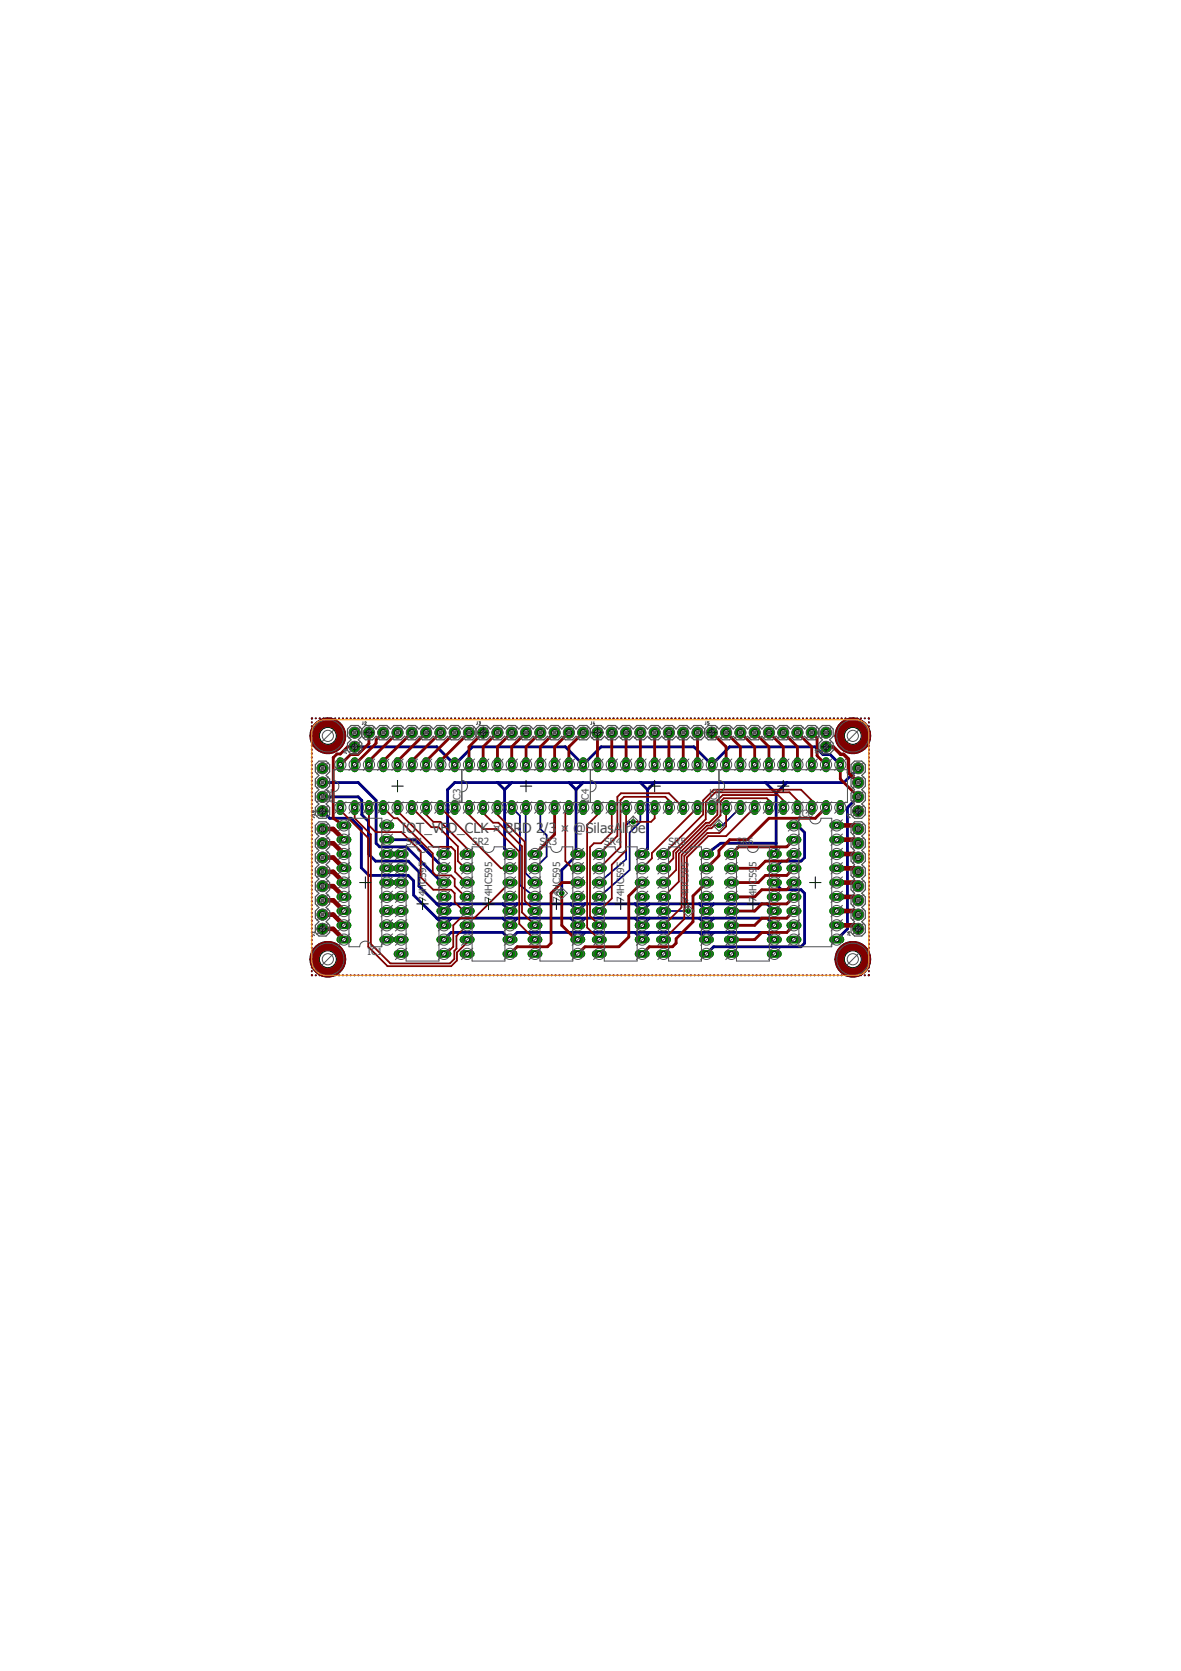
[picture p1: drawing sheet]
<svg xmlns="http://www.w3.org/2000/svg" width="210mm" height="297mm" viewBox="0 0 210 297" stroke-linecap="round" stroke-linejoin="round" font-family="sans-serif">
<defs><g id="words">
<g font-size="2.5" fill="#505050">
<text x="71.3" y="148">IOT_VF</text>
<text x="79.6" y="148">D_CLK ¤</text>
<text x="89.8" y="148">BR</text>
<text x="92.8" y="148">D 2/3</text>
<text x="99.7" y="148">¤</text>
<text x="101.8" y="148">@Silas</text>
<text x="109.1" y="148">A</text>
<text x="110.6" y="148">lroe</text>
</g>
<g font-size="1.8" fill="#505050">
<text x="59" y="142.8" transform="rotate(-90 59 142.8)">IC2</text>
<text x="81.8" y="142.8" transform="rotate(-90 81.8 142.8)">I</text>
<text x="81.8" y="142.1" transform="rotate(-90 81.8 142.1)">C3</text>
<text x="104.7" y="142.8" transform="rotate(-90 104.7 142.8)">I</text>
<text x="104.7" y="142.1" transform="rotate(-90 104.7 142.1)">C4</text>
<text x="127.5" y="142.8" transform="rotate(-90 127.5 142.8)">I</text>
<text x="127.5" y="142.1" transform="rotate(-90 127.5 142.1)">C5</text>
<text x="141.9" y="145.2">IC6</text>
<text x="72.2" y="150.2">SR1</text>
<text x="83.9" y="150.2">SR2</text>
<text x="96" y="150.2">SR3</text>
<text x="107.4" y="150.2">SR4</text>
<text x="118.8" y="150.2">SR5</text>
<text x="130.9" y="150.2">SR6</text>
<text x="134.4" y="154.2" transform="rotate(-90 134.4 154.2)">5</text>
<text x="75.7" y="160.3" transform="rotate(-90 75.7 160.3)">74HC595</text>
<text x="87.5" y="160.3" transform="rotate(-90 87.5 160.3)">74HC595</text>
<text x="99.5" y="160.3" transform="rotate(-90 99.5 160.3)">74HC595</text>
<text x="111" y="160.3" transform="rotate(-90 111 160.3)">74HC595</text>
<text x="122.4" y="160.3" transform="rotate(-90 122.4 160.3)">74HC595</text>
<text x="134.4" y="160.3" transform="rotate(-90 134.4 160.3)">74HC59</text>
<text x="65.3" y="169.8">IC1</text>
</g>
</g></defs>
<g fill="#000080" stroke="#000080" stroke-width=".18">
<path d="M56.2 168.2a3.2 3.2 0 0 1 4.9 .9 3.2 3.2 0 0 1-2.1 4.5 3.2 3.2 0 0 1-3.9-3.1h2.5a.63 .63 0 0 1 .9-.6 .63 .63 0 0 1 .2 1.1 .63 .63 0 0 1-1-.4l-.1-.1h-2.5a3.1 3.1 0 0 1 1.1-2.3z" fill-rule="evenodd"/>
<path d="M56.2 128.4a3.2 3.2 0 0 1 4.9 .9 3.2 3.2 0 0 1-2.1 4.6 3.2 3.2 0 0 1-3.9-3.1h2.5a.63 .63 0 0 1 .9-.6 .63 .63 0 0 1 .2 1 .63 .63 0 0 1-1-.3l-.1-.1h-2.5a3.2 3.2 0 0 1 1.1-2.4z" fill-rule="evenodd"/>
<path d="M149.5 128.4a3.2 3.2 0 0 1 4.9 .9 3.2 3.2 0 0 1-2.1 4.6 3.2 3.2 0 0 1-3.9-3.1h2.5a.64 .64 0 0 1 .9-.6 .64 .64 0 0 1 .2 1 .64 .64 0 0 1-1-.3l-.1-.1h-2.5a3.2 3.2 0 0 1 1.1-2.4z" fill-rule="evenodd"/>
<path d="M149.5 168.2a3.2 3.2 0 0 1 4.9 .9 3.2 3.2 0 0 1-2.1 4.5 3.2 3.2 0 0 1-3.9-3.1h2.5a.64 .64 0 0 1 .9-.6 .64 .64 0 0 1 .2 1.1 .64 .64 0 0 1-1-.4l-.1-.1h-2.5a3.1 3.1 0 0 1 1.1-2.3z" fill-rule="evenodd"/>
</g>
<g fill="none" stroke="#000080" stroke-width=".32">
<path d="M55.4 128.4v.1M55.4 129.1v.1M55.4 129.8h.1M55.4 130.5h.1M55.4 131.1v.1M55.4 131.8v.1M55.4 132.5v.1M55.4 133.2v.1M55.4 133.9v.1M55.4 134.6v.1M55.4 135.3v.1M55.4 136v.1"/>
<path d="M55.4 136.7v.1M55.4 137.4v.1M55.4 138v.1M55.4 138.7v.1M55.4 139.4v.1M55.5 127.7l-.1 .1M56.1 127.7h.1M56.8 127.7h.1M57.3 136v.6M57.5 127.7h.1M58.2 127.7h.1M58.8 127.7h.1"/>
<path d="M59.5 127.7h.1M60.2 127.7h.1M60.9 127.7h.1M61.6 127.7h.1M62.3 127.7h.1M63 127.7h.1M63 130.2l-.1 .3M63.7 127.7h.1M64.3 127.7h.1M65 127.7h.1M65.7 127.7h.1M66.4 127.7h.1"/>
<path d="M67.1 127.7h.1M67.8 127.7h.1M68.5 127.7h.1M69.2 127.7h.1M69.8 127.7h.1M70.5 127.7h.1M71.2 127.7h.1M71.9 127.7h.1M72.6 127.7h.1M73.3 127.7h.1M74 127.7h.1M74.7 127.7h.1"/>
<path d="M75.3 127.7h.1M76 127.7h.1M76.7 127.7h.1M77.4 127.7h.1M78.1 127.7h.1M78.8 127.7h.1M79.5 127.7h.1M80.2 127.7h.1M80.8 127.7h.1M81.5 127.7h.1M82.2 127.7h.1M82.9 127.7h.1"/>
<path d="M83.6 127.7h.1M84.3 127.7h.1M85 127.7h.1M85.6 127.7h.1M86.3 127.7h.1M87 127.7h.1M87.7 127.7h.1M88.4 127.7h.1M89.1 127.7h.1M89.8 127.7h.1M90.5 127.7h.1M91.1 127.7h.1"/>
<path d="M91.8 127.7h.1M92.5 127.7h.1M93.2 127.7h.1M93.9 127.7h.1M94.6 127.7h.1M95.3 127.7h.1M95.9 127.7h.1M96.6 127.7h.1M97.3 127.7h.1M98 127.7h.1M98.7 127.7h.1M99.4 127.7h.1"/>
<path d="M100.1 127.7h.1M100.8 127.7h.1M101.5 127.7h.1M102.1 127.7h.1M102.8 127.7h.1M103.5 127.7h.1M104.2 127.7h.1M104.9 127.7h.1M105.6 127.7h.1M106.3 127.7h.1M107 127.7h.1M107.6 127.7h.1"/>
<path d="M108.3 127.7h.1M109 127.7h.1M109.7 127.7h.1M110.4 127.7h.1M111.1 127.7h.1M111.8 127.7h.1M112.4 127.7h.1M113.1 127.7h.1M113.8 127.7h.1M114.5 127.7h.1M115.2 127.7h.1M115.9 127.7h.1"/>
<path d="M116.6 127.7h.1M117.3 127.7h.1M117.9 127.7h.1M118.6 127.7h.1M119.3 127.7h.1M120 127.7h.1M120.7 127.7h.1M121.4 127.7h.1M122.1 127.7h.1M122.7 127.7h.1M123.4 127.7h.1M124.1 127.7h.1"/>
<path d="M124.8 127.7h.1M125.5 127.7h.1M126.2 127.7h.1M126.9 127.7h.1M127.6 127.7h.1M128.2 127.7h.1M128.9 127.7h.1M129.6 127.7h.1M130.3 127.7h.1M131 127.7h.1M131.7 127.7h.1M132.4 127.7h.1"/>
<path d="M133.1 127.7h.1M133.8 127.7h.1M134.4 127.7h.1M135.1 127.7h.1M135.8 127.7h.1M136.5 127.7h.1M137.2 127.7h.1M137.9 127.7h.1M138.6 127.7h.1M139.2 127.7h.1M139.9 127.7h.1M140.6 127.7h.1"/>
<path d="M141.3 127.7h.1M142 127.7h.1M142.7 127.7h.1M143.4 127.7h.1M144.1 127.7h.1M144.7 127.7h.1M145.4 127.7h.1M146.1 127.7h.1M146.8 127.7h.1M147.5 127.7h.1M148.2 127.7h.1M148.9 127.7h.1"/>
<path d="M149.5 127.7h.1M150.2 127.7h.1M150.9 127.7h.1M151.6 127.7h.1M152.3 127.7h.1M153 127.7h.1M153.7 127.7h.1M154.4 127.7v.1M154.4 128.4v.1M154.4 129.1v.1M154.4 129.8h.1M154.4 130.5h.1"/>
<path d="M154.4 131.1v.1M154.4 131.8v.1M154.4 132.5v.1M154.4 133.2v.1M154.4 133.9v.1M154.4 134.6v.1M154.4 135.3v.1M154.4 136v.1M154.4 136.7v.1M154.4 137.4v.1M154.4 138v.1M154.4 138.7v.1"/>
<path d="M154.4 139.4v.1M55.4 140.1v.1M55.4 140.8v.1M55.4 141.5v.1M55.4 142.2v.1M55.4 142.9v.1M55.4 143.6v.1M55.4 144.3v.1M55.4 145v.1M55.4 145.6v.1M55.4 146.3v.1M55.4 147v.1"/>
<path d="M55.4 147.7v.1M55.4 148.4v.1M55.4 149.1v.1M55.4 149.8v.1M55.4 150.5v.1M55.4 151.2v.1M55.4 151.9v.1M55.4 152.6v.1M55.4 153.2v.1M55.4 153.9v.1M55.4 154.6v.1M55.4 155.3v.1"/>
<path d="M55.4 156v.1M55.4 156.7v.1M55.4 157.4v.1M55.4 158.1v.1M55.4 158.8v.1M55.4 159.5v.1M63 146.1l1 .9M91 143.6l1.4 1.4v12.4l2.7 2M93.5 143.6l-.1 11.6 1.7 1.7M96 143.6v3.8l1.2 1.1v3.8l-2.1 2M112.5 146.1h-.6l-.6 .6v6.1l-4.8 4.1M113.8 143.6v2.5l-1.9 1.9v6.7l-5.4 4.7"/>
<path d="M131.6 143.6l-3.2 3.1h-.6M154.4 140.1v.1M154.4 140.8v.1M154.4 141.5v.1M154.4 142.2v.1M154.4 142.9v.1M154.4 143.6v.1M154.4 144.3v.1M154.4 145v.1M154.4 145.6v.1M154.4 146.3v.1M154.4 147v.1"/>
<path d="M154.4 147.7v.1M154.4 148.4v.1M154.4 149.1v.1M154.4 149.8v.1M154.4 150.5v.1M154.4 151.2v.1M154.4 151.9v.1M154.4 152.6v.1M154.4 153.2v.1M154.4 153.9v.1M154.4 154.6v.1M154.4 155.3v.1"/>
<path d="M154.4 156v.1M154.4 156.7v.1M154.4 157.4v.1M154.4 158.1v.1M154.4 158.8v.1M154.4 159.5v.1M55.4 160.2v.1M55.4 160.9h.1M55.4 161.5v.1M55.4 162.2v.1M55.4 162.9v.1M55.4 163.6v.1"/>
<path d="M55.4 164.3v.1M55.4 165v.1M55.4 165.7v.1M55.4 166.4v.1M55.4 167.1v.1M55.4 167.8v.1M55.4 168.5h.1M55.4 169.1v.1M55.4 169.8v.1M55.4 170.5v.1M55.4 171.2v.1M55.4 171.9v.1"/>
<path d="M55.4 172.6v.1M55.4 173.3l.1 .1M56.1 173.4h.1M56.8 173.4h.1M57.5 173.4h.1M58.2 173.4h.1M58.8 173.4h.1M59.5 173.4h.1M60.2 173.4h.1M60.9 173.4h.1M61.6 173.4h.1M62.3 173.4h.1"/>
<path d="M63 173.4h.1M63.7 173.4h.1M64.3 173.4h.1M65 173.4h.1M65.7 173.4h.1M66.4 173.4h.1M67.1 173.4h.1M67.8 173.4h.1M68.5 173.4h.1M69.2 173.4h.1M69.8 173.4h.1M70.5 173.4h.1"/>
<path d="M71.2 173.4h.1M71.9 173.4h.1M72.6 173.4h.1M73.3 173.4h.1M74 173.4h.1M74.7 173.4h.1M75.3 173.4h.1M76 173.4h.1M76.7 173.4h.1M77.4 173.4h.1M78.1 173.4h.1M78.8 173.4h.1"/>
<path d="M79.5 173.4h.1M80.2 173.4h.1M80.8 173.4h.1M81.5 173.4h.1M82.2 173.4h.1M82.9 173.4h.1M83.6 173.4h.1M84.3 173.4h.1M85 173.4h.1M85.6 173.4h.1M86.3 173.4h.1M87 173.4h.1"/>
<path d="M87.7 173.4h.1M88.4 173.4h.1M89.1 173.4h.1M89.8 173.4h.1M90.5 173.4h.1M91.1 173.4h.1M91.8 173.4h.1M92.5 173.4h.1M93.2 173.4h.1M93.9 173.4h.1M94.6 173.4h.1M95.3 173.4h.1"/>
<path d="M95.9 173.4h.1M96.6 173.4h.1M97.3 173.4h.1M98 173.4h.1M98.7 173.4h.1M99.4 173.4h.1M100.1 173.4h.1M100.8 173.4h.1M101.5 173.4h.1M102.1 173.4h.1M102.8 173.4h.1M103.5 173.4h.1"/>
<path d="M104.2 173.4h.1M104.9 173.4h.1M105.6 173.4h.1M106.3 173.4h.1M107 173.4h.1M107.6 173.4h.1M108.3 173.4h.1M109 173.4h.1M109.7 173.4h.1M110.4 173.4h.1M111.1 173.4h.1M111.8 173.4h.1"/>
<path d="M112.4 173.4h.1M113.1 173.4h.1M113.8 173.4h.1M114.5 173.4h.1M115.2 173.4h.1M115.9 173.4h.1M116.6 173.4h.1M117.3 173.4h.1M117.9 173.4h.1M117.9 161.9h4.4M118.6 173.4h.1M119.3 173.4h.1"/>
<path d="M120 173.4h.1M120.7 173.4h.1M121.4 173.4h.1M122.1 173.4h.1M122.7 173.4h.1M123.4 173.4h.1M124.1 173.4h.1M124.8 173.4h.1M125.5 173.4h.1M126.2 173.4h.1M126.9 173.4h.1M127.6 173.4h.1"/>
<path d="M128.2 173.4h.1M128.9 173.4h.1M129.6 173.4h.1M130.3 173.4h.1M131 173.4h.1M131.7 173.4h.1M132.4 173.4h.1M133.1 173.4h.1M133.8 173.4h.1M134.4 173.4h.1M135.1 173.4h.1M135.8 173.4h.1"/>
<path d="M136.5 173.4h.1M137.2 173.4h.1M137.9 173.4h.1M138.6 173.4h.1M139.2 173.4h.1M139.9 173.4h.1M140.6 173.4h.1M141.3 173.4h.1M142 173.4h.1M142.7 173.4h.1M143.4 173.4h.1M144.1 173.4h.1"/>
<path d="M144.7 173.4h.1M145.4 173.4h.1M146.1 173.4h.1M146.8 173.4h.1M147.5 173.4h.1M148.2 173.4h.1M148.9 173.4h.1M149.5 173.4h.1M150.2 173.4h.1M150.9 173.4h.1M151.6 173.4h.1M152.3 173.4h.1"/>
<path d="M153 173.4h.1M153.7 173.4h.1M154.4 160.2v.1M154.4 160.9h.1M154.4 161.5v.1M154.4 162.2v.1M154.4 162.9v.1M154.4 163.6v.1M154.4 164.3v.1M154.4 165v.1M154.4 165.7v.1M154.4 166.4v.1"/>
<path d="M154.4 167.1v.1M154.4 167.8v.1M154.4 168.5h.1M154.4 169.1v.1M154.4 169.8v.1M154.4 170.5v.1M154.4 171.2v.1M154.4 171.9v.1M154.4 172.6v.1M154.4 173.3v.1"/>
</g>
<g fill="none" stroke="#000080" stroke-width=".51">
<path d="M57.3 139.1h6.4l3.1 3.2v7.6l.7 .6h4.7l6.4 6.4h.3M63 132.8h14.6l3.2 3.1 3.2-3.1h16.5l3.2 3.1 3.1-3.1h16.5l3.2 3.1 3.2-3.1h15.2l1.4 1.3h1.3l1.8 1.8M88.4 139.1l1.3 1.3M91 139.1l-1.3 1.3M101.1 139.1l1.3 1.3M103.7 139.1l-1.3 1.3M113.8 139.1l1.3 1.3M116.4 139.1l-1.3 1.3M136 139.1l1.9 1.9M139.8 139.1l-1.9 1.9M152.5 136.6l-2.5 2.5h-69.2l-1.3 1.3v10.8l-.6 .6M57.3 144.2l1.3 1.3h3.8l1.8 1.8v7l1.4 1.3h7l.9 1v2.5l5.4 5.4 1.3-1.3"/>
<path d="M57.3 141.6h6.4l.6 .7v2.5l1.2 1.2v5.8l1.3 1.3h5.8l1.9 1.9v2.5l4.4 4.4 1.3-1.2M68.7 149.3h5.1l5.1 5M89.7 140.4v10.5l.9 .9M102.4 140.4v10.8l.3 .3v.3l-2.9 2.9v4.1M115.1 140.4v10.5l-1 .9M137.6 156.9l1.3 1.3h3.5l.6 .6v8.9l-.6 .6h-15.6l-1.2 1.3M137.9 141v11.1l-.3-.3M137.9 149.9h-9.8l-2.5 1.9M141.1 146.7h.6l1.3 1.3v4.4l-.6 .7h-3.5l-1.3 1.2M152.5 141.6l-1.9 2v21.5l-1.9 1.9M77.6 163.2h58.8l1.2 1.3M77.6 160.7h58.8l1.2 1.2"/>
<path d="M78.9 167l1.3-1.2h9.2l1.2 1.2 1.3-1.2h44.5l1.2 1.2M89.4 163.2l1.2 1.3 1.3-1.3M89.4 160.7l1.2 1.2 1.3-1.2M101.4 165.8l1.3 1.2 1.3-1.2M101.4 163.2l1.3 1.3 1.3-1.3M101.4 160.7l1.3 1.2 1.3-1.2M112.9 165.8l1.2 1.2 1.3-1.2M112.9 163.2l1.2 1.3 1.3-1.3M112.9 160.7l1.2 1.2 1.3-1.2M124.3 165.8l1.3 1.2 1.2-1.2M124.3 163.2l1.3 1.3 1.2-1.3M124.3 160.7l1.3 1.2 1.2-1.2"/>
<path d="M124.6 160.7v.3"/>
</g>
<circle cx="57.3" cy="165.1" r=".93" fill="#008000" stroke="#008000" stroke-width=".18"/>
<circle cx="57.3" cy="165.1" r=".51" fill="#fff" stroke="#000" stroke-width=".18"/>
<circle cx="57.3" cy="162.6" r=".93" fill="#008000" stroke="#008000" stroke-width=".18"/>
<circle cx="57.3" cy="162.6" r=".51" fill="#fff" stroke="#000" stroke-width=".18"/>
<circle cx="57.3" cy="160" r=".93" fill="#008000" stroke="#008000" stroke-width=".18"/>
<circle cx="57.3" cy="160" r=".51" fill="#fff" stroke="#000" stroke-width=".18"/>
<circle cx="57.3" cy="157.5" r=".93" fill="#008000" stroke="#008000" stroke-width=".18"/>
<circle cx="57.3" cy="157.5" r=".51" fill="#fff" stroke="#000" stroke-width=".18"/>
<circle cx="57.3" cy="155" r=".93" fill="#008000" stroke="#008000" stroke-width=".18"/>
<circle cx="57.3" cy="155" r=".51" fill="#fff" stroke="#000" stroke-width=".18"/>
<circle cx="57.3" cy="152.4" r=".93" fill="#008000" stroke="#008000" stroke-width=".18"/>
<circle cx="57.3" cy="152.4" r=".51" fill="#fff" stroke="#000" stroke-width=".18"/>
<circle cx="57.3" cy="149.9" r=".93" fill="#008000" stroke="#008000" stroke-width=".18"/>
<circle cx="57.3" cy="149.9" r=".51" fill="#fff" stroke="#000" stroke-width=".18"/>
<circle cx="57.3" cy="147.4" r=".93" fill="#008000" stroke="#008000" stroke-width=".18"/>
<circle cx="57.3" cy="147.4" r=".51" fill="#fff" stroke="#000" stroke-width=".18"/>
<circle cx="65.6" cy="130.2" r=".93" fill="#008000" stroke="#008000" stroke-width=".18"/>
<circle cx="65.6" cy="130.2" r=".51" fill="#fff" stroke="#000" stroke-width=".18"/>
<circle cx="68.1" cy="130.2" r=".93" fill="#008000" stroke="#008000" stroke-width=".18"/>
<circle cx="68.1" cy="130.2" r=".51" fill="#fff" stroke="#000" stroke-width=".18"/>
<circle cx="70.7" cy="130.2" r=".93" fill="#008000" stroke="#008000" stroke-width=".18"/>
<circle cx="70.7" cy="130.2" r=".51" fill="#fff" stroke="#000" stroke-width=".18"/>
<circle cx="73.2" cy="130.2" r=".93" fill="#008000" stroke="#008000" stroke-width=".18"/>
<circle cx="73.2" cy="130.2" r=".51" fill="#fff" stroke="#000" stroke-width=".18"/>
<circle cx="75.7" cy="130.2" r=".93" fill="#008000" stroke="#008000" stroke-width=".18"/>
<circle cx="75.7" cy="130.2" r=".51" fill="#fff" stroke="#000" stroke-width=".18"/>
<circle cx="78.3" cy="130.2" r=".93" fill="#008000" stroke="#008000" stroke-width=".18"/>
<circle cx="78.3" cy="130.2" r=".51" fill="#fff" stroke="#000" stroke-width=".18"/>
<circle cx="80.8" cy="130.2" r=".93" fill="#008000" stroke="#008000" stroke-width=".18"/>
<circle cx="80.8" cy="130.2" r=".51" fill="#fff" stroke="#000" stroke-width=".18"/>
<circle cx="83.4" cy="130.2" r=".93" fill="#008000" stroke="#008000" stroke-width=".18"/>
<circle cx="83.4" cy="130.2" r=".51" fill="#fff" stroke="#000" stroke-width=".18"/>
<circle cx="85.9" cy="130.2" r=".93" fill="#008000" stroke="#008000" stroke-width=".18"/>
<circle cx="85.9" cy="130.2" r=".51" fill="#fff" stroke="#000" stroke-width=".18"/>
<circle cx="88.4" cy="130.2" r=".93" fill="#008000" stroke="#008000" stroke-width=".18"/>
<circle cx="88.4" cy="130.2" r=".51" fill="#fff" stroke="#000" stroke-width=".18"/>
<circle cx="91" cy="130.2" r=".93" fill="#008000" stroke="#008000" stroke-width=".18"/>
<circle cx="91" cy="130.2" r=".51" fill="#fff" stroke="#000" stroke-width=".18"/>
<circle cx="93.5" cy="130.2" r=".93" fill="#008000" stroke="#008000" stroke-width=".18"/>
<circle cx="93.5" cy="130.2" r=".51" fill="#fff" stroke="#000" stroke-width=".18"/>
<circle cx="96" cy="130.2" r=".93" fill="#008000" stroke="#008000" stroke-width=".18"/>
<circle cx="96" cy="130.2" r=".51" fill="#fff" stroke="#000" stroke-width=".18"/>
<circle cx="98.6" cy="130.2" r=".93" fill="#008000" stroke="#008000" stroke-width=".18"/>
<circle cx="98.6" cy="130.2" r=".51" fill="#fff" stroke="#000" stroke-width=".18"/>
<circle cx="101.1" cy="130.2" r=".93" fill="#008000" stroke="#008000" stroke-width=".18"/>
<circle cx="101.1" cy="130.2" r=".51" fill="#fff" stroke="#000" stroke-width=".18"/>
<circle cx="103.7" cy="130.2" r=".93" fill="#008000" stroke="#008000" stroke-width=".18"/>
<circle cx="103.7" cy="130.2" r=".51" fill="#fff" stroke="#000" stroke-width=".18"/>
<circle cx="106.2" cy="130.2" r=".93" fill="#008000" stroke="#008000" stroke-width=".18"/>
<circle cx="106.2" cy="130.2" r=".51" fill="#fff" stroke="#000" stroke-width=".18"/>
<circle cx="108.7" cy="130.2" r=".93" fill="#008000" stroke="#008000" stroke-width=".18"/>
<circle cx="108.7" cy="130.2" r=".51" fill="#fff" stroke="#000" stroke-width=".18"/>
<circle cx="111.3" cy="130.2" r=".93" fill="#008000" stroke="#008000" stroke-width=".18"/>
<circle cx="111.3" cy="130.2" r=".51" fill="#fff" stroke="#000" stroke-width=".18"/>
<circle cx="113.8" cy="130.2" r=".93" fill="#008000" stroke="#008000" stroke-width=".18"/>
<circle cx="113.8" cy="130.2" r=".51" fill="#fff" stroke="#000" stroke-width=".18"/>
<circle cx="116.4" cy="130.2" r=".93" fill="#008000" stroke="#008000" stroke-width=".18"/>
<circle cx="116.4" cy="130.2" r=".51" fill="#fff" stroke="#000" stroke-width=".18"/>
<circle cx="118.9" cy="130.2" r=".93" fill="#008000" stroke="#008000" stroke-width=".18"/>
<circle cx="118.9" cy="130.2" r=".51" fill="#fff" stroke="#000" stroke-width=".18"/>
<circle cx="121.4" cy="130.2" r=".93" fill="#008000" stroke="#008000" stroke-width=".18"/>
<circle cx="121.4" cy="130.2" r=".51" fill="#fff" stroke="#000" stroke-width=".18"/>
<circle cx="124" cy="130.2" r=".93" fill="#008000" stroke="#008000" stroke-width=".18"/>
<circle cx="124" cy="130.2" r=".51" fill="#fff" stroke="#000" stroke-width=".18"/>
<circle cx="126.5" cy="130.2" r=".93" fill="#008000" stroke="#008000" stroke-width=".18"/>
<circle cx="126.5" cy="130.2" r=".51" fill="#fff" stroke="#000" stroke-width=".18"/>
<circle cx="129.1" cy="130.2" r=".93" fill="#008000" stroke="#008000" stroke-width=".18"/>
<circle cx="129.1" cy="130.2" r=".51" fill="#fff" stroke="#000" stroke-width=".18"/>
<circle cx="131.6" cy="130.2" r=".93" fill="#008000" stroke="#008000" stroke-width=".18"/>
<circle cx="131.6" cy="130.2" r=".51" fill="#fff" stroke="#000" stroke-width=".18"/>
<circle cx="134.1" cy="130.2" r=".93" fill="#008000" stroke="#008000" stroke-width=".18"/>
<circle cx="134.1" cy="130.2" r=".51" fill="#fff" stroke="#000" stroke-width=".18"/>
<circle cx="136.7" cy="130.2" r=".93" fill="#008000" stroke="#008000" stroke-width=".18"/>
<circle cx="136.7" cy="130.2" r=".51" fill="#fff" stroke="#000" stroke-width=".18"/>
<circle cx="139.2" cy="130.2" r=".93" fill="#008000" stroke="#008000" stroke-width=".18"/>
<circle cx="139.2" cy="130.2" r=".51" fill="#fff" stroke="#000" stroke-width=".18"/>
<circle cx="141.7" cy="130.2" r=".93" fill="#008000" stroke="#008000" stroke-width=".18"/>
<circle cx="141.7" cy="130.2" r=".51" fill="#fff" stroke="#000" stroke-width=".18"/>
<circle cx="144.3" cy="130.2" r=".93" fill="#008000" stroke="#008000" stroke-width=".18"/>
<circle cx="144.3" cy="130.2" r=".51" fill="#fff" stroke="#000" stroke-width=".18"/>
<circle cx="152.5" cy="165.1" r=".93" fill="#008000" stroke="#008000" stroke-width=".18"/>
<circle cx="152.5" cy="165.1" r=".51" fill="#fff" stroke="#000" stroke-width=".18"/>
<circle cx="152.5" cy="162.6" r=".93" fill="#008000" stroke="#008000" stroke-width=".18"/>
<circle cx="152.5" cy="162.6" r=".51" fill="#fff" stroke="#000" stroke-width=".18"/>
<circle cx="152.5" cy="160" r=".93" fill="#008000" stroke="#008000" stroke-width=".18"/>
<circle cx="152.5" cy="160" r=".51" fill="#fff" stroke="#000" stroke-width=".18"/>
<circle cx="152.5" cy="157.5" r=".93" fill="#008000" stroke="#008000" stroke-width=".18"/>
<circle cx="152.5" cy="157.5" r=".51" fill="#fff" stroke="#000" stroke-width=".18"/>
<circle cx="152.5" cy="155" r=".93" fill="#008000" stroke="#008000" stroke-width=".18"/>
<circle cx="152.5" cy="155" r=".51" fill="#fff" stroke="#000" stroke-width=".18"/>
<circle cx="152.5" cy="152.4" r=".93" fill="#008000" stroke="#008000" stroke-width=".18"/>
<circle cx="152.5" cy="152.4" r=".51" fill="#fff" stroke="#000" stroke-width=".18"/>
<circle cx="152.5" cy="149.9" r=".93" fill="#008000" stroke="#008000" stroke-width=".18"/>
<circle cx="152.5" cy="149.9" r=".51" fill="#fff" stroke="#000" stroke-width=".18"/>
<circle cx="152.5" cy="147.4" r=".93" fill="#008000" stroke="#008000" stroke-width=".18"/>
<circle cx="152.5" cy="147.4" r=".51" fill="#fff" stroke="#000" stroke-width=".18"/>
<circle cx="63" cy="132.8" r=".93" fill="#008000" stroke="#008000" stroke-width=".18"/>
<circle cx="63" cy="132.8" r=".51" fill="#fff" stroke="#000" stroke-width=".18"/>
<circle cx="63" cy="130.2" r=".93" fill="#008000" stroke="#008000" stroke-width=".18"/>
<circle cx="63" cy="130.2" r=".51" fill="#fff" stroke="#000" stroke-width=".18"/>
<circle cx="146.8" cy="132.8" r=".93" fill="#008000" stroke="#008000" stroke-width=".18"/>
<circle cx="146.8" cy="132.8" r=".51" fill="#fff" stroke="#000" stroke-width=".18"/>
<circle cx="146.8" cy="130.2" r=".93" fill="#008000" stroke="#008000" stroke-width=".18"/>
<circle cx="146.8" cy="130.2" r=".51" fill="#fff" stroke="#000" stroke-width=".18"/>
<path d="M68.1 167h1.3" fill="none" stroke="#008000" stroke-width="1.3"/>
<circle cx="68.7" cy="167" r=".4" fill="#fff" stroke="#000" stroke-width=".18"/>
<path d="M68.1 164.5h1.3" fill="none" stroke="#008000" stroke-width="1.3"/>
<circle cx="68.7" cy="164.5" r=".4" fill="#fff" stroke="#000" stroke-width=".18"/>
<path d="M68.1 151.8h1.3" fill="none" stroke="#008000" stroke-width="1.3"/>
<circle cx="68.7" cy="151.8" r=".4" fill="#fff" stroke="#000" stroke-width=".18"/>
<path d="M68.1 149.3h1.3" fill="none" stroke="#008000" stroke-width="1.3"/>
<circle cx="68.7" cy="149.3" r=".4" fill="#fff" stroke="#000" stroke-width=".18"/>
<path d="M68.1 161.9h1.3" fill="none" stroke="#008000" stroke-width="1.3"/>
<circle cx="68.7" cy="161.9" r=".4" fill="#fff" stroke="#000" stroke-width=".18"/>
<path d="M68.1 159.4h1.3" fill="none" stroke="#008000" stroke-width="1.3"/>
<circle cx="68.7" cy="159.4" r=".4" fill="#fff" stroke="#000" stroke-width=".18"/>
<path d="M68.1 154.3h1.3" fill="none" stroke="#008000" stroke-width="1.3"/>
<circle cx="68.7" cy="154.3" r=".4" fill="#fff" stroke="#000" stroke-width=".18"/>
<path d="M68.1 156.9h1.3" fill="none" stroke="#008000" stroke-width="1.3"/>
<circle cx="68.7" cy="156.9" r=".4" fill="#fff" stroke="#000" stroke-width=".18"/>
<path d="M68.1 146.7h1.3" fill="none" stroke="#008000" stroke-width="1.3"/>
<circle cx="68.7" cy="146.7" r=".4" fill="#fff" stroke="#000" stroke-width=".18"/>
<path d="M60.5 146.7h1.3" fill="none" stroke="#008000" stroke-width="1.3"/>
<circle cx="61.1" cy="146.7" r=".4" fill="#fff" stroke="#000" stroke-width=".18"/>
<path d="M60.5 149.3h1.3" fill="none" stroke="#008000" stroke-width="1.3"/>
<circle cx="61.1" cy="149.3" r=".4" fill="#fff" stroke="#000" stroke-width=".18"/>
<path d="M60.5 151.8h1.3" fill="none" stroke="#008000" stroke-width="1.3"/>
<circle cx="61.1" cy="151.8" r=".4" fill="#fff" stroke="#000" stroke-width=".18"/>
<path d="M60.5 154.3h1.3" fill="none" stroke="#008000" stroke-width="1.3"/>
<circle cx="61.1" cy="154.3" r=".4" fill="#fff" stroke="#000" stroke-width=".18"/>
<path d="M60.5 156.9h1.3" fill="none" stroke="#008000" stroke-width="1.3"/>
<circle cx="61.1" cy="156.9" r=".4" fill="#fff" stroke="#000" stroke-width=".18"/>
<path d="M60.5 159.4h1.3" fill="none" stroke="#008000" stroke-width="1.3"/>
<circle cx="61.1" cy="159.4" r=".4" fill="#fff" stroke="#000" stroke-width=".18"/>
<path d="M60.5 161.9h1.3" fill="none" stroke="#008000" stroke-width="1.3"/>
<circle cx="61.1" cy="161.9" r=".4" fill="#fff" stroke="#000" stroke-width=".18"/>
<path d="M60.5 164.5h1.3" fill="none" stroke="#008000" stroke-width="1.3"/>
<circle cx="61.1" cy="164.5" r=".4" fill="#fff" stroke="#000" stroke-width=".18"/>
<path d="M60.5 167h1.3" fill="none" stroke="#008000" stroke-width="1.3"/>
<circle cx="61.1" cy="167" r=".4" fill="#fff" stroke="#000" stroke-width=".18"/>
<path d="M60.5 142.9v1.3" fill="none" stroke="#008000" stroke-width="1.3"/>
<circle cx="60.5" cy="143.6" r=".4" fill="#fff" stroke="#000" stroke-width=".18"/>
<path d="M63 142.9v1.3" fill="none" stroke="#008000" stroke-width="1.3"/>
<circle cx="63" cy="143.6" r=".4" fill="#fff" stroke="#000" stroke-width=".18"/>
<path d="M75.7 142.9v1.3" fill="none" stroke="#008000" stroke-width="1.3"/>
<circle cx="75.7" cy="143.6" r=".4" fill="#fff" stroke="#000" stroke-width=".18"/>
<path d="M78.3 142.9v1.3" fill="none" stroke="#008000" stroke-width="1.3"/>
<circle cx="78.3" cy="143.6" r=".4" fill="#fff" stroke="#000" stroke-width=".18"/>
<path d="M65.6 142.9v1.3" fill="none" stroke="#008000" stroke-width="1.3"/>
<circle cx="65.6" cy="143.6" r=".4" fill="#fff" stroke="#000" stroke-width=".18"/>
<path d="M68.1 142.9v1.3" fill="none" stroke="#008000" stroke-width="1.3"/>
<circle cx="68.1" cy="143.6" r=".4" fill="#fff" stroke="#000" stroke-width=".18"/>
<path d="M73.2 142.9v1.3" fill="none" stroke="#008000" stroke-width="1.3"/>
<circle cx="73.2" cy="143.6" r=".4" fill="#fff" stroke="#000" stroke-width=".18"/>
<path d="M70.7 142.9v1.3" fill="none" stroke="#008000" stroke-width="1.3"/>
<circle cx="70.7" cy="143.6" r=".4" fill="#fff" stroke="#000" stroke-width=".18"/>
<path d="M80.8 142.9v1.3" fill="none" stroke="#008000" stroke-width="1.3"/>
<circle cx="80.8" cy="143.6" r=".4" fill="#fff" stroke="#000" stroke-width=".18"/>
<path d="M80.8 135.3v1.3" fill="none" stroke="#008000" stroke-width="1.3"/>
<circle cx="80.8" cy="135.9" r=".4" fill="#fff" stroke="#000" stroke-width=".18"/>
<path d="M78.3 135.3v1.3" fill="none" stroke="#008000" stroke-width="1.3"/>
<circle cx="78.3" cy="135.9" r=".4" fill="#fff" stroke="#000" stroke-width=".18"/>
<path d="M75.7 135.3v1.3" fill="none" stroke="#008000" stroke-width="1.3"/>
<circle cx="75.7" cy="135.9" r=".4" fill="#fff" stroke="#000" stroke-width=".18"/>
<path d="M73.2 135.3v1.3" fill="none" stroke="#008000" stroke-width="1.3"/>
<circle cx="73.2" cy="135.9" r=".4" fill="#fff" stroke="#000" stroke-width=".18"/>
<path d="M70.7 135.3v1.3" fill="none" stroke="#008000" stroke-width="1.3"/>
<circle cx="70.7" cy="135.9" r=".4" fill="#fff" stroke="#000" stroke-width=".18"/>
<path d="M68.1 135.3v1.3" fill="none" stroke="#008000" stroke-width="1.3"/>
<circle cx="68.1" cy="135.9" r=".4" fill="#fff" stroke="#000" stroke-width=".18"/>
<path d="M65.6 135.3v1.3" fill="none" stroke="#008000" stroke-width="1.3"/>
<circle cx="65.6" cy="135.9" r=".4" fill="#fff" stroke="#000" stroke-width=".18"/>
<path d="M63 135.3v1.3" fill="none" stroke="#008000" stroke-width="1.3"/>
<circle cx="63" cy="135.9" r=".4" fill="#fff" stroke="#000" stroke-width=".18"/>
<path d="M60.5 135.3v1.3" fill="none" stroke="#008000" stroke-width="1.3"/>
<circle cx="60.5" cy="135.9" r=".4" fill="#fff" stroke="#000" stroke-width=".18"/>
<path d="M83.4 142.9v1.3" fill="none" stroke="#008000" stroke-width="1.3"/>
<circle cx="83.4" cy="143.6" r=".4" fill="#fff" stroke="#000" stroke-width=".18"/>
<path d="M85.9 142.9v1.3" fill="none" stroke="#008000" stroke-width="1.3"/>
<circle cx="85.9" cy="143.6" r=".4" fill="#fff" stroke="#000" stroke-width=".18"/>
<path d="M98.6 142.9v1.3" fill="none" stroke="#008000" stroke-width="1.3"/>
<circle cx="98.6" cy="143.6" r=".4" fill="#fff" stroke="#000" stroke-width=".18"/>
<path d="M101.1 142.9v1.3" fill="none" stroke="#008000" stroke-width="1.3"/>
<circle cx="101.1" cy="143.6" r=".4" fill="#fff" stroke="#000" stroke-width=".18"/>
<path d="M88.4 142.9v1.3" fill="none" stroke="#008000" stroke-width="1.3"/>
<circle cx="88.4" cy="143.6" r=".4" fill="#fff" stroke="#000" stroke-width=".18"/>
<path d="M91 142.9v1.3" fill="none" stroke="#008000" stroke-width="1.3"/>
<circle cx="91" cy="143.6" r=".4" fill="#fff" stroke="#000" stroke-width=".18"/>
<path d="M96 142.9v1.3" fill="none" stroke="#008000" stroke-width="1.3"/>
<circle cx="96" cy="143.6" r=".4" fill="#fff" stroke="#000" stroke-width=".18"/>
<path d="M93.5 142.9v1.3" fill="none" stroke="#008000" stroke-width="1.3"/>
<circle cx="93.5" cy="143.6" r=".4" fill="#fff" stroke="#000" stroke-width=".18"/>
<path d="M103.7 142.9v1.3" fill="none" stroke="#008000" stroke-width="1.3"/>
<circle cx="103.7" cy="143.6" r=".4" fill="#fff" stroke="#000" stroke-width=".18"/>
<path d="M103.7 135.3v1.3" fill="none" stroke="#008000" stroke-width="1.3"/>
<circle cx="103.7" cy="135.9" r=".4" fill="#fff" stroke="#000" stroke-width=".18"/>
<path d="M101.1 135.3v1.3" fill="none" stroke="#008000" stroke-width="1.3"/>
<circle cx="101.1" cy="135.9" r=".4" fill="#fff" stroke="#000" stroke-width=".18"/>
<path d="M98.6 135.3v1.3" fill="none" stroke="#008000" stroke-width="1.3"/>
<circle cx="98.6" cy="135.9" r=".4" fill="#fff" stroke="#000" stroke-width=".18"/>
<path d="M96 135.3v1.3" fill="none" stroke="#008000" stroke-width="1.3"/>
<circle cx="96" cy="135.9" r=".4" fill="#fff" stroke="#000" stroke-width=".18"/>
<path d="M93.5 135.3v1.3" fill="none" stroke="#008000" stroke-width="1.3"/>
<circle cx="93.5" cy="135.9" r=".4" fill="#fff" stroke="#000" stroke-width=".18"/>
<path d="M91 135.3v1.3" fill="none" stroke="#008000" stroke-width="1.3"/>
<circle cx="91" cy="135.9" r=".4" fill="#fff" stroke="#000" stroke-width=".18"/>
<path d="M88.4 135.3v1.3" fill="none" stroke="#008000" stroke-width="1.3"/>
<circle cx="88.4" cy="135.9" r=".4" fill="#fff" stroke="#000" stroke-width=".18"/>
<path d="M85.9 135.3v1.3" fill="none" stroke="#008000" stroke-width="1.3"/>
<circle cx="85.9" cy="135.9" r=".4" fill="#fff" stroke="#000" stroke-width=".18"/>
<path d="M83.4 135.3v1.3" fill="none" stroke="#008000" stroke-width="1.3"/>
<circle cx="83.4" cy="135.9" r=".4" fill="#fff" stroke="#000" stroke-width=".18"/>
<path d="M106.2 142.9v1.3" fill="none" stroke="#008000" stroke-width="1.3"/>
<circle cx="106.2" cy="143.6" r=".4" fill="#fff" stroke="#000" stroke-width=".18"/>
<path d="M108.7 142.9v1.3" fill="none" stroke="#008000" stroke-width="1.3"/>
<circle cx="108.7" cy="143.6" r=".4" fill="#fff" stroke="#000" stroke-width=".18"/>
<path d="M121.4 142.9v1.3" fill="none" stroke="#008000" stroke-width="1.3"/>
<circle cx="121.4" cy="143.6" r=".4" fill="#fff" stroke="#000" stroke-width=".18"/>
<path d="M124 142.9v1.3" fill="none" stroke="#008000" stroke-width="1.3"/>
<circle cx="124" cy="143.6" r=".4" fill="#fff" stroke="#000" stroke-width=".18"/>
<path d="M111.3 142.9v1.3" fill="none" stroke="#008000" stroke-width="1.3"/>
<circle cx="111.3" cy="143.6" r=".4" fill="#fff" stroke="#000" stroke-width=".18"/>
<path d="M113.8 142.9v1.3" fill="none" stroke="#008000" stroke-width="1.3"/>
<circle cx="113.8" cy="143.6" r=".4" fill="#fff" stroke="#000" stroke-width=".18"/>
<path d="M118.9 142.9v1.3" fill="none" stroke="#008000" stroke-width="1.3"/>
<circle cx="118.9" cy="143.6" r=".4" fill="#fff" stroke="#000" stroke-width=".18"/>
<path d="M116.4 142.9v1.3" fill="none" stroke="#008000" stroke-width="1.3"/>
<circle cx="116.4" cy="143.6" r=".4" fill="#fff" stroke="#000" stroke-width=".18"/>
<path d="M126.5 142.9v1.3" fill="none" stroke="#008000" stroke-width="1.3"/>
<circle cx="126.5" cy="143.6" r=".4" fill="#fff" stroke="#000" stroke-width=".18"/>
<path d="M126.5 135.3v1.3" fill="none" stroke="#008000" stroke-width="1.3"/>
<circle cx="126.5" cy="135.9" r=".4" fill="#fff" stroke="#000" stroke-width=".18"/>
<path d="M124 135.3v1.3" fill="none" stroke="#008000" stroke-width="1.3"/>
<circle cx="124" cy="135.9" r=".4" fill="#fff" stroke="#000" stroke-width=".18"/>
<path d="M121.4 135.3v1.3" fill="none" stroke="#008000" stroke-width="1.3"/>
<circle cx="121.4" cy="135.9" r=".4" fill="#fff" stroke="#000" stroke-width=".18"/>
<path d="M118.9 135.3v1.3" fill="none" stroke="#008000" stroke-width="1.3"/>
<circle cx="118.9" cy="135.9" r=".4" fill="#fff" stroke="#000" stroke-width=".18"/>
<path d="M116.4 135.3v1.3" fill="none" stroke="#008000" stroke-width="1.3"/>
<circle cx="116.4" cy="135.9" r=".4" fill="#fff" stroke="#000" stroke-width=".18"/>
<path d="M113.8 135.3v1.3" fill="none" stroke="#008000" stroke-width="1.3"/>
<circle cx="113.8" cy="135.9" r=".4" fill="#fff" stroke="#000" stroke-width=".18"/>
<path d="M111.3 135.3v1.3" fill="none" stroke="#008000" stroke-width="1.3"/>
<circle cx="111.3" cy="135.9" r=".4" fill="#fff" stroke="#000" stroke-width=".18"/>
<path d="M108.7 135.3v1.3" fill="none" stroke="#008000" stroke-width="1.3"/>
<circle cx="108.7" cy="135.9" r=".4" fill="#fff" stroke="#000" stroke-width=".18"/>
<path d="M106.2 135.3v1.3" fill="none" stroke="#008000" stroke-width="1.3"/>
<circle cx="106.2" cy="135.9" r=".4" fill="#fff" stroke="#000" stroke-width=".18"/>
<path d="M129.1 142.9v1.3" fill="none" stroke="#008000" stroke-width="1.3"/>
<circle cx="129.1" cy="143.6" r=".4" fill="#fff" stroke="#000" stroke-width=".18"/>
<path d="M131.6 142.9v1.3" fill="none" stroke="#008000" stroke-width="1.3"/>
<circle cx="131.6" cy="143.6" r=".4" fill="#fff" stroke="#000" stroke-width=".18"/>
<path d="M144.3 142.9v1.3" fill="none" stroke="#008000" stroke-width="1.3"/>
<circle cx="144.3" cy="143.6" r=".4" fill="#fff" stroke="#000" stroke-width=".18"/>
<path d="M146.8 142.9v1.3" fill="none" stroke="#008000" stroke-width="1.3"/>
<circle cx="146.8" cy="143.6" r=".4" fill="#fff" stroke="#000" stroke-width=".18"/>
<path d="M134.1 142.9v1.3" fill="none" stroke="#008000" stroke-width="1.3"/>
<circle cx="134.1" cy="143.6" r=".4" fill="#fff" stroke="#000" stroke-width=".18"/>
<path d="M136.7 142.9v1.3" fill="none" stroke="#008000" stroke-width="1.3"/>
<circle cx="136.7" cy="143.6" r=".4" fill="#fff" stroke="#000" stroke-width=".18"/>
<path d="M141.7 142.9v1.3" fill="none" stroke="#008000" stroke-width="1.3"/>
<circle cx="141.7" cy="143.6" r=".4" fill="#fff" stroke="#000" stroke-width=".18"/>
<path d="M139.2 142.9v1.3" fill="none" stroke="#008000" stroke-width="1.3"/>
<circle cx="139.2" cy="143.6" r=".4" fill="#fff" stroke="#000" stroke-width=".18"/>
<path d="M149.4 142.9v1.3" fill="none" stroke="#008000" stroke-width="1.3"/>
<circle cx="149.4" cy="143.6" r=".4" fill="#fff" stroke="#000" stroke-width=".18"/>
<path d="M149.4 135.3v1.3" fill="none" stroke="#008000" stroke-width="1.3"/>
<circle cx="149.4" cy="135.9" r=".4" fill="#fff" stroke="#000" stroke-width=".18"/>
<path d="M146.8 135.3v1.3" fill="none" stroke="#008000" stroke-width="1.3"/>
<circle cx="146.8" cy="135.9" r=".4" fill="#fff" stroke="#000" stroke-width=".18"/>
<path d="M144.3 135.3v1.3" fill="none" stroke="#008000" stroke-width="1.3"/>
<circle cx="144.3" cy="135.9" r=".4" fill="#fff" stroke="#000" stroke-width=".18"/>
<path d="M141.7 135.3v1.3" fill="none" stroke="#008000" stroke-width="1.3"/>
<circle cx="141.7" cy="135.9" r=".4" fill="#fff" stroke="#000" stroke-width=".18"/>
<path d="M139.2 135.3v1.3" fill="none" stroke="#008000" stroke-width="1.3"/>
<circle cx="139.2" cy="135.9" r=".4" fill="#fff" stroke="#000" stroke-width=".18"/>
<path d="M136.7 135.3v1.3" fill="none" stroke="#008000" stroke-width="1.3"/>
<circle cx="136.7" cy="135.9" r=".4" fill="#fff" stroke="#000" stroke-width=".18"/>
<path d="M134.1 135.3v1.3" fill="none" stroke="#008000" stroke-width="1.3"/>
<circle cx="134.1" cy="135.9" r=".4" fill="#fff" stroke="#000" stroke-width=".18"/>
<path d="M131.6 135.3v1.3" fill="none" stroke="#008000" stroke-width="1.3"/>
<circle cx="131.6" cy="135.9" r=".4" fill="#fff" stroke="#000" stroke-width=".18"/>
<path d="M129.1 135.3v1.3" fill="none" stroke="#008000" stroke-width="1.3"/>
<circle cx="129.1" cy="135.9" r=".4" fill="#fff" stroke="#000" stroke-width=".18"/>
<path d="M140.4 146.7h1.4" fill="none" stroke="#008000" stroke-width="1.3"/>
<circle cx="141.1" cy="146.7" r=".4" fill="#fff" stroke="#000" stroke-width=".18"/>
<path d="M140.4 149.3h1.4" fill="none" stroke="#008000" stroke-width="1.3"/>
<circle cx="141.1" cy="149.3" r=".4" fill="#fff" stroke="#000" stroke-width=".18"/>
<path d="M140.4 161.9h1.4" fill="none" stroke="#008000" stroke-width="1.3"/>
<circle cx="141.1" cy="161.9" r=".4" fill="#fff" stroke="#000" stroke-width=".18"/>
<path d="M140.4 164.5h1.4" fill="none" stroke="#008000" stroke-width="1.3"/>
<circle cx="141.1" cy="164.5" r=".4" fill="#fff" stroke="#000" stroke-width=".18"/>
<path d="M140.4 151.8h1.4" fill="none" stroke="#008000" stroke-width="1.3"/>
<circle cx="141.1" cy="151.8" r=".4" fill="#fff" stroke="#000" stroke-width=".18"/>
<path d="M140.4 154.3h1.4" fill="none" stroke="#008000" stroke-width="1.3"/>
<circle cx="141.1" cy="154.3" r=".4" fill="#fff" stroke="#000" stroke-width=".18"/>
<path d="M140.4 159.4h1.4" fill="none" stroke="#008000" stroke-width="1.3"/>
<circle cx="141.1" cy="159.4" r=".4" fill="#fff" stroke="#000" stroke-width=".18"/>
<path d="M140.4 156.9h1.4" fill="none" stroke="#008000" stroke-width="1.3"/>
<circle cx="141.1" cy="156.9" r=".4" fill="#fff" stroke="#000" stroke-width=".18"/>
<path d="M140.4 167h1.4" fill="none" stroke="#008000" stroke-width="1.3"/>
<circle cx="141.1" cy="167" r=".4" fill="#fff" stroke="#000" stroke-width=".18"/>
<path d="M148.1 167h1.3" fill="none" stroke="#008000" stroke-width="1.3"/>
<circle cx="148.7" cy="167" r=".4" fill="#fff" stroke="#000" stroke-width=".18"/>
<path d="M148.1 164.5h1.3" fill="none" stroke="#008000" stroke-width="1.3"/>
<circle cx="148.7" cy="164.5" r=".4" fill="#fff" stroke="#000" stroke-width=".18"/>
<path d="M148.1 161.9h1.3" fill="none" stroke="#008000" stroke-width="1.3"/>
<circle cx="148.7" cy="161.9" r=".4" fill="#fff" stroke="#000" stroke-width=".18"/>
<path d="M148.1 159.4h1.3" fill="none" stroke="#008000" stroke-width="1.3"/>
<circle cx="148.7" cy="159.4" r=".4" fill="#fff" stroke="#000" stroke-width=".18"/>
<path d="M148.1 156.9h1.3" fill="none" stroke="#008000" stroke-width="1.3"/>
<circle cx="148.7" cy="156.9" r=".4" fill="#fff" stroke="#000" stroke-width=".18"/>
<path d="M148.1 154.3h1.3" fill="none" stroke="#008000" stroke-width="1.3"/>
<circle cx="148.7" cy="154.3" r=".4" fill="#fff" stroke="#000" stroke-width=".18"/>
<path d="M148.1 151.8h1.3" fill="none" stroke="#008000" stroke-width="1.3"/>
<circle cx="148.7" cy="151.8" r=".4" fill="#fff" stroke="#000" stroke-width=".18"/>
<path d="M148.1 149.3h1.3" fill="none" stroke="#008000" stroke-width="1.3"/>
<circle cx="148.7" cy="149.3" r=".4" fill="#fff" stroke="#000" stroke-width=".18"/>
<path d="M148.1 146.7h1.3" fill="none" stroke="#008000" stroke-width="1.3"/>
<circle cx="148.7" cy="146.7" r=".4" fill="#fff" stroke="#000" stroke-width=".18"/>
<path d="M70.6 151.8h1.3" fill="none" stroke="#008000" stroke-width="1.3"/>
<circle cx="71.3" cy="151.8" r=".4" fill="#fff" stroke="#000" stroke-width=".18"/>
<path d="M70.6 154.3h1.3" fill="none" stroke="#008000" stroke-width="1.3"/>
<circle cx="71.3" cy="154.3" r=".4" fill="#fff" stroke="#000" stroke-width=".18"/>
<path d="M70.6 167h1.3" fill="none" stroke="#008000" stroke-width="1.3"/>
<circle cx="71.3" cy="167" r=".4" fill="#fff" stroke="#000" stroke-width=".18"/>
<path d="M70.6 169.6h1.3" fill="none" stroke="#008000" stroke-width="1.3"/>
<circle cx="71.3" cy="169.6" r=".4" fill="#fff" stroke="#000" stroke-width=".18"/>
<path d="M70.6 156.9h1.3" fill="none" stroke="#008000" stroke-width="1.3"/>
<circle cx="71.3" cy="156.9" r=".4" fill="#fff" stroke="#000" stroke-width=".18"/>
<path d="M70.6 159.4h1.3" fill="none" stroke="#008000" stroke-width="1.3"/>
<circle cx="71.3" cy="159.4" r=".4" fill="#fff" stroke="#000" stroke-width=".18"/>
<path d="M70.6 164.5h1.3" fill="none" stroke="#008000" stroke-width="1.3"/>
<circle cx="71.3" cy="164.5" r=".4" fill="#fff" stroke="#000" stroke-width=".18"/>
<path d="M70.6 161.9h1.3" fill="none" stroke="#008000" stroke-width="1.3"/>
<circle cx="71.3" cy="161.9" r=".4" fill="#fff" stroke="#000" stroke-width=".18"/>
<path d="M78.2 169.6h1.4" fill="none" stroke="#008000" stroke-width="1.3"/>
<circle cx="78.9" cy="169.6" r=".4" fill="#fff" stroke="#000" stroke-width=".18"/>
<path d="M78.2 167h1.4" fill="none" stroke="#008000" stroke-width="1.3"/>
<circle cx="78.9" cy="167" r=".4" fill="#fff" stroke="#000" stroke-width=".18"/>
<path d="M78.2 164.5h1.4" fill="none" stroke="#008000" stroke-width="1.3"/>
<circle cx="78.9" cy="164.5" r=".4" fill="#fff" stroke="#000" stroke-width=".18"/>
<path d="M78.2 161.9h1.4" fill="none" stroke="#008000" stroke-width="1.3"/>
<circle cx="78.9" cy="161.9" r=".4" fill="#fff" stroke="#000" stroke-width=".18"/>
<path d="M78.2 159.4h1.4" fill="none" stroke="#008000" stroke-width="1.3"/>
<circle cx="78.9" cy="159.4" r=".4" fill="#fff" stroke="#000" stroke-width=".18"/>
<path d="M78.2 156.9h1.4" fill="none" stroke="#008000" stroke-width="1.3"/>
<circle cx="78.9" cy="156.9" r=".4" fill="#fff" stroke="#000" stroke-width=".18"/>
<path d="M78.2 154.3h1.4" fill="none" stroke="#008000" stroke-width="1.3"/>
<circle cx="78.9" cy="154.3" r=".4" fill="#fff" stroke="#000" stroke-width=".18"/>
<path d="M78.2 151.8h1.4" fill="none" stroke="#008000" stroke-width="1.3"/>
<circle cx="78.9" cy="151.8" r=".4" fill="#fff" stroke="#000" stroke-width=".18"/>
<path d="M82.4 151.8h1.3" fill="none" stroke="#008000" stroke-width="1.3"/>
<circle cx="83" cy="151.8" r=".4" fill="#fff" stroke="#000" stroke-width=".18"/>
<path d="M82.4 154.3h1.3" fill="none" stroke="#008000" stroke-width="1.3"/>
<circle cx="83" cy="154.3" r=".4" fill="#fff" stroke="#000" stroke-width=".18"/>
<path d="M82.4 167h1.3" fill="none" stroke="#008000" stroke-width="1.3"/>
<circle cx="83" cy="167" r=".4" fill="#fff" stroke="#000" stroke-width=".18"/>
<path d="M82.4 169.6h1.3" fill="none" stroke="#008000" stroke-width="1.3"/>
<circle cx="83" cy="169.6" r=".4" fill="#fff" stroke="#000" stroke-width=".18"/>
<path d="M82.4 156.9h1.3" fill="none" stroke="#008000" stroke-width="1.3"/>
<circle cx="83" cy="156.9" r=".4" fill="#fff" stroke="#000" stroke-width=".18"/>
<path d="M82.4 159.4h1.3" fill="none" stroke="#008000" stroke-width="1.3"/>
<circle cx="83" cy="159.4" r=".4" fill="#fff" stroke="#000" stroke-width=".18"/>
<path d="M82.4 164.5h1.3" fill="none" stroke="#008000" stroke-width="1.3"/>
<circle cx="83" cy="164.5" r=".4" fill="#fff" stroke="#000" stroke-width=".18"/>
<path d="M82.4 161.9h1.3" fill="none" stroke="#008000" stroke-width="1.3"/>
<circle cx="83" cy="161.9" r=".4" fill="#fff" stroke="#000" stroke-width=".18"/>
<path d="M90 169.6h1.3" fill="none" stroke="#008000" stroke-width="1.3"/>
<circle cx="90.6" cy="169.6" r=".4" fill="#fff" stroke="#000" stroke-width=".18"/>
<path d="M90 167h1.3" fill="none" stroke="#008000" stroke-width="1.3"/>
<circle cx="90.6" cy="167" r=".4" fill="#fff" stroke="#000" stroke-width=".18"/>
<path d="M90 164.5h1.3" fill="none" stroke="#008000" stroke-width="1.3"/>
<circle cx="90.6" cy="164.5" r=".4" fill="#fff" stroke="#000" stroke-width=".18"/>
<path d="M90 161.9h1.3" fill="none" stroke="#008000" stroke-width="1.3"/>
<circle cx="90.6" cy="161.9" r=".4" fill="#fff" stroke="#000" stroke-width=".18"/>
<path d="M90 159.4h1.3" fill="none" stroke="#008000" stroke-width="1.3"/>
<circle cx="90.6" cy="159.4" r=".4" fill="#fff" stroke="#000" stroke-width=".18"/>
<path d="M90 156.9h1.3" fill="none" stroke="#008000" stroke-width="1.3"/>
<circle cx="90.6" cy="156.9" r=".4" fill="#fff" stroke="#000" stroke-width=".18"/>
<path d="M90 154.3h1.3" fill="none" stroke="#008000" stroke-width="1.3"/>
<circle cx="90.6" cy="154.3" r=".4" fill="#fff" stroke="#000" stroke-width=".18"/>
<path d="M90 151.8h1.3" fill="none" stroke="#008000" stroke-width="1.3"/>
<circle cx="90.6" cy="151.8" r=".4" fill="#fff" stroke="#000" stroke-width=".18"/>
<path d="M94.4 151.8h1.3" fill="none" stroke="#008000" stroke-width="1.3"/>
<circle cx="95.1" cy="151.8" r=".4" fill="#fff" stroke="#000" stroke-width=".18"/>
<path d="M94.4 154.3h1.3" fill="none" stroke="#008000" stroke-width="1.3"/>
<circle cx="95.1" cy="154.3" r=".4" fill="#fff" stroke="#000" stroke-width=".18"/>
<path d="M94.4 167h1.3" fill="none" stroke="#008000" stroke-width="1.3"/>
<circle cx="95.1" cy="167" r=".4" fill="#fff" stroke="#000" stroke-width=".18"/>
<path d="M94.4 169.6h1.3" fill="none" stroke="#008000" stroke-width="1.3"/>
<circle cx="95.1" cy="169.6" r=".4" fill="#fff" stroke="#000" stroke-width=".18"/>
<path d="M94.4 156.9h1.3" fill="none" stroke="#008000" stroke-width="1.3"/>
<circle cx="95.1" cy="156.9" r=".4" fill="#fff" stroke="#000" stroke-width=".18"/>
<path d="M94.4 159.4h1.3" fill="none" stroke="#008000" stroke-width="1.3"/>
<circle cx="95.1" cy="159.4" r=".4" fill="#fff" stroke="#000" stroke-width=".18"/>
<path d="M94.4 164.5h1.3" fill="none" stroke="#008000" stroke-width="1.3"/>
<circle cx="95.1" cy="164.5" r=".4" fill="#fff" stroke="#000" stroke-width=".18"/>
<path d="M94.4 161.9h1.3" fill="none" stroke="#008000" stroke-width="1.3"/>
<circle cx="95.1" cy="161.9" r=".4" fill="#fff" stroke="#000" stroke-width=".18"/>
<path d="M102 169.6h1.4" fill="none" stroke="#008000" stroke-width="1.3"/>
<circle cx="102.7" cy="169.6" r=".4" fill="#fff" stroke="#000" stroke-width=".18"/>
<path d="M102 167h1.4" fill="none" stroke="#008000" stroke-width="1.3"/>
<circle cx="102.7" cy="167" r=".4" fill="#fff" stroke="#000" stroke-width=".18"/>
<path d="M102 164.5h1.4" fill="none" stroke="#008000" stroke-width="1.3"/>
<circle cx="102.7" cy="164.5" r=".4" fill="#fff" stroke="#000" stroke-width=".18"/>
<path d="M102 161.9h1.4" fill="none" stroke="#008000" stroke-width="1.3"/>
<circle cx="102.7" cy="161.9" r=".4" fill="#fff" stroke="#000" stroke-width=".18"/>
<path d="M102 159.4h1.4" fill="none" stroke="#008000" stroke-width="1.3"/>
<circle cx="102.7" cy="159.4" r=".4" fill="#fff" stroke="#000" stroke-width=".18"/>
<path d="M102 156.9h1.4" fill="none" stroke="#008000" stroke-width="1.3"/>
<circle cx="102.7" cy="156.9" r=".4" fill="#fff" stroke="#000" stroke-width=".18"/>
<path d="M102 154.3h1.4" fill="none" stroke="#008000" stroke-width="1.3"/>
<circle cx="102.7" cy="154.3" r=".4" fill="#fff" stroke="#000" stroke-width=".18"/>
<path d="M102 151.8h1.4" fill="none" stroke="#008000" stroke-width="1.3"/>
<circle cx="102.7" cy="151.8" r=".4" fill="#fff" stroke="#000" stroke-width=".18"/>
<path d="M105.9 151.8h1.3" fill="none" stroke="#008000" stroke-width="1.3"/>
<circle cx="106.5" cy="151.8" r=".4" fill="#fff" stroke="#000" stroke-width=".18"/>
<path d="M105.9 154.3h1.3" fill="none" stroke="#008000" stroke-width="1.3"/>
<circle cx="106.5" cy="154.3" r=".4" fill="#fff" stroke="#000" stroke-width=".18"/>
<path d="M105.9 167h1.3" fill="none" stroke="#008000" stroke-width="1.3"/>
<circle cx="106.5" cy="167" r=".4" fill="#fff" stroke="#000" stroke-width=".18"/>
<path d="M105.9 169.6h1.3" fill="none" stroke="#008000" stroke-width="1.3"/>
<circle cx="106.5" cy="169.6" r=".4" fill="#fff" stroke="#000" stroke-width=".18"/>
<path d="M105.9 156.9h1.3" fill="none" stroke="#008000" stroke-width="1.3"/>
<circle cx="106.5" cy="156.9" r=".4" fill="#fff" stroke="#000" stroke-width=".18"/>
<path d="M105.9 159.4h1.3" fill="none" stroke="#008000" stroke-width="1.3"/>
<circle cx="106.5" cy="159.4" r=".4" fill="#fff" stroke="#000" stroke-width=".18"/>
<path d="M105.9 164.5h1.3" fill="none" stroke="#008000" stroke-width="1.3"/>
<circle cx="106.5" cy="164.5" r=".4" fill="#fff" stroke="#000" stroke-width=".18"/>
<path d="M105.9 161.9h1.3" fill="none" stroke="#008000" stroke-width="1.3"/>
<circle cx="106.5" cy="161.9" r=".4" fill="#fff" stroke="#000" stroke-width=".18"/>
<path d="M113.5 169.6h1.3" fill="none" stroke="#008000" stroke-width="1.3"/>
<circle cx="114.1" cy="169.6" r=".4" fill="#fff" stroke="#000" stroke-width=".18"/>
<path d="M113.5 167h1.3" fill="none" stroke="#008000" stroke-width="1.3"/>
<circle cx="114.1" cy="167" r=".4" fill="#fff" stroke="#000" stroke-width=".18"/>
<path d="M113.5 164.5h1.3" fill="none" stroke="#008000" stroke-width="1.3"/>
<circle cx="114.1" cy="164.5" r=".4" fill="#fff" stroke="#000" stroke-width=".18"/>
<path d="M113.5 161.9h1.3" fill="none" stroke="#008000" stroke-width="1.3"/>
<circle cx="114.1" cy="161.9" r=".4" fill="#fff" stroke="#000" stroke-width=".18"/>
<path d="M113.5 159.4h1.3" fill="none" stroke="#008000" stroke-width="1.3"/>
<circle cx="114.1" cy="159.4" r=".4" fill="#fff" stroke="#000" stroke-width=".18"/>
<path d="M113.5 156.9h1.3" fill="none" stroke="#008000" stroke-width="1.3"/>
<circle cx="114.1" cy="156.9" r=".4" fill="#fff" stroke="#000" stroke-width=".18"/>
<path d="M113.5 154.3h1.3" fill="none" stroke="#008000" stroke-width="1.3"/>
<circle cx="114.1" cy="154.3" r=".4" fill="#fff" stroke="#000" stroke-width=".18"/>
<path d="M113.5 151.8h1.3" fill="none" stroke="#008000" stroke-width="1.3"/>
<circle cx="114.1" cy="151.8" r=".4" fill="#fff" stroke="#000" stroke-width=".18"/>
<path d="M117.3 151.8h1.3" fill="none" stroke="#008000" stroke-width="1.3"/>
<circle cx="117.9" cy="151.8" r=".4" fill="#fff" stroke="#000" stroke-width=".18"/>
<path d="M117.3 154.3h1.3" fill="none" stroke="#008000" stroke-width="1.3"/>
<circle cx="117.9" cy="154.3" r=".4" fill="#fff" stroke="#000" stroke-width=".18"/>
<path d="M117.3 167h1.3" fill="none" stroke="#008000" stroke-width="1.3"/>
<circle cx="117.9" cy="167" r=".4" fill="#fff" stroke="#000" stroke-width=".18"/>
<path d="M117.3 169.6h1.3" fill="none" stroke="#008000" stroke-width="1.3"/>
<circle cx="117.9" cy="169.6" r=".4" fill="#fff" stroke="#000" stroke-width=".18"/>
<path d="M117.3 156.9h1.3" fill="none" stroke="#008000" stroke-width="1.3"/>
<circle cx="117.9" cy="156.9" r=".4" fill="#fff" stroke="#000" stroke-width=".18"/>
<path d="M117.3 159.4h1.3" fill="none" stroke="#008000" stroke-width="1.3"/>
<circle cx="117.9" cy="159.4" r=".4" fill="#fff" stroke="#000" stroke-width=".18"/>
<path d="M117.3 164.5h1.3" fill="none" stroke="#008000" stroke-width="1.3"/>
<circle cx="117.9" cy="164.5" r=".4" fill="#fff" stroke="#000" stroke-width=".18"/>
<path d="M117.3 161.9h1.3" fill="none" stroke="#008000" stroke-width="1.3"/>
<circle cx="117.9" cy="161.9" r=".4" fill="#fff" stroke="#000" stroke-width=".18"/>
<path d="M124.9 169.6h1.3" fill="none" stroke="#008000" stroke-width="1.3"/>
<circle cx="125.6" cy="169.6" r=".4" fill="#fff" stroke="#000" stroke-width=".18"/>
<path d="M124.9 167h1.3" fill="none" stroke="#008000" stroke-width="1.3"/>
<circle cx="125.6" cy="167" r=".4" fill="#fff" stroke="#000" stroke-width=".18"/>
<path d="M124.9 164.5h1.3" fill="none" stroke="#008000" stroke-width="1.3"/>
<circle cx="125.6" cy="164.5" r=".4" fill="#fff" stroke="#000" stroke-width=".18"/>
<path d="M124.9 161.9h1.3" fill="none" stroke="#008000" stroke-width="1.3"/>
<circle cx="125.6" cy="161.9" r=".4" fill="#fff" stroke="#000" stroke-width=".18"/>
<path d="M124.9 159.4h1.3" fill="none" stroke="#008000" stroke-width="1.3"/>
<circle cx="125.6" cy="159.4" r=".4" fill="#fff" stroke="#000" stroke-width=".18"/>
<path d="M124.9 156.9h1.3" fill="none" stroke="#008000" stroke-width="1.3"/>
<circle cx="125.6" cy="156.9" r=".4" fill="#fff" stroke="#000" stroke-width=".18"/>
<path d="M124.9 154.3h1.3" fill="none" stroke="#008000" stroke-width="1.3"/>
<circle cx="125.6" cy="154.3" r=".4" fill="#fff" stroke="#000" stroke-width=".18"/>
<path d="M124.9 151.8h1.3" fill="none" stroke="#008000" stroke-width="1.3"/>
<circle cx="125.6" cy="151.8" r=".4" fill="#fff" stroke="#000" stroke-width=".18"/>
<path d="M129.3 151.8h1.4" fill="none" stroke="#008000" stroke-width="1.3"/>
<circle cx="130" cy="151.8" r=".4" fill="#fff" stroke="#000" stroke-width=".18"/>
<path d="M129.3 154.3h1.4" fill="none" stroke="#008000" stroke-width="1.3"/>
<circle cx="130" cy="154.3" r=".4" fill="#fff" stroke="#000" stroke-width=".18"/>
<path d="M129.3 167h1.4" fill="none" stroke="#008000" stroke-width="1.3"/>
<circle cx="130" cy="167" r=".4" fill="#fff" stroke="#000" stroke-width=".18"/>
<path d="M129.3 169.6h1.4" fill="none" stroke="#008000" stroke-width="1.3"/>
<circle cx="130" cy="169.6" r=".4" fill="#fff" stroke="#000" stroke-width=".18"/>
<path d="M129.3 156.9h1.4" fill="none" stroke="#008000" stroke-width="1.3"/>
<circle cx="130" cy="156.9" r=".4" fill="#fff" stroke="#000" stroke-width=".18"/>
<path d="M129.3 159.4h1.4" fill="none" stroke="#008000" stroke-width="1.3"/>
<circle cx="130" cy="159.4" r=".4" fill="#fff" stroke="#000" stroke-width=".18"/>
<path d="M129.3 164.5h1.4" fill="none" stroke="#008000" stroke-width="1.3"/>
<circle cx="130" cy="164.5" r=".4" fill="#fff" stroke="#000" stroke-width=".18"/>
<path d="M129.3 161.9h1.4" fill="none" stroke="#008000" stroke-width="1.3"/>
<circle cx="130" cy="161.9" r=".4" fill="#fff" stroke="#000" stroke-width=".18"/>
<path d="M136.9 169.6h1.4" fill="none" stroke="#008000" stroke-width="1.3"/>
<circle cx="137.6" cy="169.6" r=".4" fill="#fff" stroke="#000" stroke-width=".18"/>
<path d="M136.9 167h1.4" fill="none" stroke="#008000" stroke-width="1.3"/>
<circle cx="137.6" cy="167" r=".4" fill="#fff" stroke="#000" stroke-width=".18"/>
<path d="M136.9 164.5h1.4" fill="none" stroke="#008000" stroke-width="1.3"/>
<circle cx="137.6" cy="164.5" r=".4" fill="#fff" stroke="#000" stroke-width=".18"/>
<path d="M136.9 161.9h1.4" fill="none" stroke="#008000" stroke-width="1.3"/>
<circle cx="137.6" cy="161.9" r=".4" fill="#fff" stroke="#000" stroke-width=".18"/>
<path d="M136.9 159.4h1.4" fill="none" stroke="#008000" stroke-width="1.3"/>
<circle cx="137.6" cy="159.4" r=".4" fill="#fff" stroke="#000" stroke-width=".18"/>
<path d="M136.9 156.9h1.4" fill="none" stroke="#008000" stroke-width="1.3"/>
<circle cx="137.6" cy="156.9" r=".4" fill="#fff" stroke="#000" stroke-width=".18"/>
<path d="M136.9 154.3h1.4" fill="none" stroke="#008000" stroke-width="1.3"/>
<circle cx="137.6" cy="154.3" r=".4" fill="#fff" stroke="#000" stroke-width=".18"/>
<path d="M136.9 151.8h1.4" fill="none" stroke="#008000" stroke-width="1.3"/>
<circle cx="137.6" cy="151.8" r=".4" fill="#fff" stroke="#000" stroke-width=".18"/>
<circle cx="152.5" cy="144.2" r=".93" fill="#008000" stroke="#008000" stroke-width=".18"/>
<circle cx="152.5" cy="144.2" r=".51" fill="#fff" stroke="#000" stroke-width=".18"/>
<circle cx="152.5" cy="141.6" r=".93" fill="#008000" stroke="#008000" stroke-width=".18"/>
<circle cx="152.5" cy="141.6" r=".51" fill="#fff" stroke="#000" stroke-width=".18"/>
<circle cx="152.5" cy="139.1" r=".93" fill="#008000" stroke="#008000" stroke-width=".18"/>
<circle cx="152.5" cy="139.1" r=".51" fill="#fff" stroke="#000" stroke-width=".18"/>
<circle cx="152.5" cy="136.6" r=".93" fill="#008000" stroke="#008000" stroke-width=".18"/>
<circle cx="152.5" cy="136.6" r=".51" fill="#fff" stroke="#000" stroke-width=".18"/>
<circle cx="57.3" cy="144.2" r=".93" fill="#008000" stroke="#008000" stroke-width=".18"/>
<circle cx="57.3" cy="144.2" r=".51" fill="#fff" stroke="#000" stroke-width=".18"/>
<circle cx="57.3" cy="141.6" r=".93" fill="#008000" stroke="#008000" stroke-width=".18"/>
<circle cx="57.3" cy="141.6" r=".51" fill="#fff" stroke="#000" stroke-width=".18"/>
<circle cx="57.3" cy="139.1" r=".93" fill="#008000" stroke="#008000" stroke-width=".18"/>
<circle cx="57.3" cy="139.1" r=".51" fill="#fff" stroke="#000" stroke-width=".18"/>
<circle cx="57.3" cy="136.6" r=".93" fill="#008000" stroke="#008000" stroke-width=".18"/>
<circle cx="57.3" cy="136.6" r=".51" fill="#fff" stroke="#000" stroke-width=".18"/>
<circle cx="99.8" cy="158.8" r=".38" fill="#008000" stroke="#008000" stroke-width=".18"/>
<circle cx="99.8" cy="158.8" r=".17" fill="#fff" stroke="#000" stroke-width=".18"/>
<circle cx="112.5" cy="146.1" r=".38" fill="#008000" stroke="#008000" stroke-width=".18"/>
<circle cx="112.5" cy="146.1" r=".17" fill="#fff" stroke="#000" stroke-width=".18"/>
<circle cx="122.3" cy="161.9" r=".38" fill="#008000" stroke="#008000" stroke-width=".18"/>
<circle cx="122.3" cy="161.9" r=".17" fill="#fff" stroke="#000" stroke-width=".18"/>
<circle cx="127.8" cy="146.7" r=".38" fill="#008000" stroke="#008000" stroke-width=".18"/>
<circle cx="127.8" cy="146.7" r=".17" fill="#fff" stroke="#000" stroke-width=".18"/>
<g fill="none" stroke="#800000" stroke-width=".32">
<path d="M55.4 128.4v.1M55.4 129.1v.1M55.4 129.8h.1M55.4 130.5h.1M55.4 131.1v.1M55.4 131.8v.1M55.4 132.5v.1M55.4 133.2v.1M55.4 133.9v.1M55.4 134.6v.1M55.4 135.3v.1M55.4 136v.1"/>
<path d="M55.4 136.7v.1M55.4 137.4v.1M55.4 138v.1M55.4 138.7v.1M55.4 139.4v.1M55.5 127.7l-.1 .1M56.1 127.7h.1M56.8 127.7h.1M57.5 127.7h.1M58.2 127.7h.1M58.8 127.7h.1M59.5 127.7h.1"/>
<path d="M60.2 127.7h.1M60.9 127.7h.1M61.6 127.7h.1M62.3 127.7h.1M63 127.7h.1M63.7 127.7h.1M64.3 127.7h.1M65 127.7h.1M65.7 127.7h.1M66.4 127.7h.1M67.1 127.7h.1M67.8 127.7h.1"/>
<path d="M68.5 127.7h.1M69.2 127.7h.1M69.8 127.7h.1M70.5 127.7h.1M71.2 127.7h.1M71.9 127.7h.1M72.6 127.7h.1M73.3 127.7h.1M74 127.7h.1M74.7 127.7h.1M75.3 127.7h.1M76 127.7h.1"/>
<path d="M76.7 127.7h.1M77.4 127.7h.1M78.1 127.7h.1M78.8 127.7h.1M79.5 127.7h.1M80.2 127.7h.1M80.8 127.7h.1M81.5 127.7h.1M82.2 127.7h.1M82.9 127.7h.1M83.6 127.7h.1M84.3 127.7h.1"/>
<path d="M85 127.7h.1M85.6 127.7h.1M86.3 127.7h.1M87 127.7h.1M87.7 127.7h.1M88.4 127.7h.1M89.1 127.7h.1M89.8 127.7h.1M90.5 127.7h.1M91.1 127.7h.1M91.8 127.7h.1M92.5 127.7h.1"/>
<path d="M93.2 127.7h.1M93.9 127.7h.1M94.6 127.7h.1M95.3 127.7h.1M95.9 127.7h.1M96.6 127.7h.1M97.3 127.7h.1M98 127.7h.1M98.7 127.7h.1M99.4 127.7h.1M100.1 127.7h.1M100.8 127.7h.1"/>
<path d="M101.5 127.7h.1M102.1 127.7h.1M102.8 127.7h.1M103.5 127.7h.1M103.7 135.9v.1M104.2 127.7h.1M104.9 127.7h.1M105.6 127.7h.1M106.3 127.7h.1M107 127.7h.1M107.6 127.7h.1M108.3 127.7h.1"/>
<path d="M109 127.7h.1M109.7 127.7h.1M110.4 127.7h.1M111.1 127.7h.1M111.8 127.7h.1M112.4 127.7h.1M113.1 127.7h.1M113.8 127.7h.1M114.5 127.7h.1M115.2 127.7h.1M115.9 127.7h.1M116.6 127.7h.1"/>
<path d="M117.3 127.7h.1M117.9 127.7h.1M118.6 127.7h.1M119.3 127.7h.1M120 127.7h.1M120.7 127.7h.1M121.4 127.7h.1M122.1 127.7h.1M122.7 127.7h.1M123.4 127.7h.1M124.1 127.7h.1M124.8 127.7h.1"/>
<path d="M125.5 127.7h.1M126.2 127.7h.1M126.9 127.7h.1M127.6 127.7h.1M128.2 127.7h.1M128.9 127.7h.1M129.6 127.7h.1M130.3 127.7h.1M131 127.7h.1M131.7 127.7h.1M132.4 127.7h.1M133.1 127.7h.1"/>
<path d="M133.8 127.7h.1M134.4 127.7h.1M135.1 127.7h.1M135.8 127.7h.1M136.5 127.7h.1M137.2 127.7h.1M137.9 127.7h.1M138.6 127.7h.1M139.2 127.7h.1M139.9 127.7h.1M140.6 127.7h.1M141.3 127.7h.1"/>
<path d="M142 127.7h.1M142.7 127.7h.1M143.4 127.7h.1M144.1 127.7h.1M144.7 127.7h.1M145.4 127.7h.1M146.1 127.7h.1M146.8 127.7h.1M147.5 127.7h.1M148.2 127.7h.1M148.9 127.7h.1M149.5 127.7h.1"/>
<path d="M150.2 127.7h.1M150.9 127.7h.1M151.6 127.7h.1M152.3 127.7h.1M153 127.7h.1M153.7 127.7h.1M154.4 127.7v.1M154.4 128.4v.1M154.4 129.1v.1M154.4 129.8h.1M154.4 130.5h.1M154.4 131.1v.1"/>
<path d="M154.4 131.8v.1M154.4 132.5v.1M154.4 133.2v.1M154.4 133.9v.1M154.4 134.6v.1M154.4 135.3v.1M154.4 136v.1M154.4 136.7v.1M154.4 137.4v.1M154.4 138v.1M154.4 138.7v.1M154.4 139.4v.1"/>
<path d="M55.4 140.1v.1M55.4 140.8v.1M55.4 141.5v.1M55.4 142.2v.1M55.4 142.9v.1M55.4 143.6v.1M55.4 144.3v.1M55.4 145v.1M55.4 145.6v.1M55.4 146.3v.1M55.4 147v.1M55.4 147.7v.1"/>
<path d="M55.4 148.4v.1M55.4 149.1v.1M55.4 149.8v.1M55.4 150.5v.1M55.4 151.2v.1M55.4 151.9v.1M55.4 152.6v.1M55.4 153.2v.1M55.4 153.9v.1M55.4 154.6v.1M55.4 155.3v.1M55.4 156v.1"/>
<path d="M55.4 156.7v.1M55.4 157.4v.1M55.4 158.1v.1M55.4 158.8v.1M55.4 159.5v.1M60.5 143.6v.4l4.9 5v19.3l3.5 3.4h11.3l1-1v-1.4l1.8-1.8v-.5M63 143.6v1.9l2.9 2.8v19.5l3.5 3.5h10.6l.8-.8v-1.5l.3-.4v-2.2l1.9-1.9M65.6 143.6v3.1l1.2 1.2h4.6l3.4 3.4v4.6l2.2 2.3h3.2l.6 .6v1.6l1.6 1.5h.6M68.1 143.6l1.9 1.9h.7l6.2 6.2v3.3l.6 .6h2.7l.6 .7v1.2l1.9 1.9h.3M70.7 143.6v.6l6.3 6.3h3.2l.7 .8v3.7l1.9 1.9h.2M73.2 143.6l3.5 3.4h1.3l3.4 3.5v2.6l1.3 1.2h.3M75.7 143.6v1.2l1.3 1.3h1.3l4.7 4.8v.9"/>
<path d="M78.3 143.6l10.7 10.7h1.6M83.4 143.6v1.2l2.5 2.6h2.4l4 4v12.8l2.8 2.8M85.9 143.6v.9l1.7 1.7h1l4.2 4.3v11.7l2.3 2.3M88.4 143.6v1.2l4.9 4.8v10.5l1.8 1.8M90.6 156.9l-6.3 6.3h-2.5l-1.2 1.3v3.8l-1.7 1.6v-.3M101.1 143.6l-.6 .6v8.9l1.2 1.2h1M106.2 143.6v1.2l-1.8 1.9v18.2l2.1 2.1M108.7 143.6v4.4l-1.9 1.9h-1.2l-.7 .7v12.2l1.6 1.7M111.3 143.6v7.6l-2.6 2.5v6l-2.2 2.2M116.4 143.6v1.9l-.7 .6h-3.2M118.9 143.6v-1.3l-.6-.7h-7.4l-.6 .7v8.3l-3.8 3.7M121.4 143.6l-2.5-2.6h-8.5l-.7 .6v7l-3.2 3.2"/>
<path d="M124 143.6l-8.1 8v1l-1.8 1.7M127.8 146.7h-.8l-.6 .5h-.5l-4.8 4.8v9.3l-3.2 3.2M129.1 143.6v3.3l-1.2 1.2h-2.2l-4.1 4.1v11.2l-3.7 3.6M134.1 143.6l-5 5h-3.2l-3.8 3.8v8.1l.2 .2v1.2M136.7 143.6v-1.3l-.4-.4h-7.7l-.5 .6v2.4l-1.8 1.8h-.6l-5.1 5.1v4.9l-2.7 2.7M139.2 143.6v-1.3l-.9-1h-9.8l-1 1v2.5l-1.5 1.5h-.5l-5.3 5.3v3l-2.3 2.3M141.7 143.6v-1.3l-1.4-1.5h-13.2l-1.7 1.8v3l-5.7 5.8v1.2l-1.8 1.7M144.3 143.6v-1.3l-1.9-1.9h-15.5l-1.9 1.9v2.5l-7.1 7M152.4 141.5l.1 .1M154.4 140.1v.1M154.4 140.8v.1M154.4 141.5v.1"/>
<path d="M154.4 142.2v.1M154.4 142.9v.1M154.4 143.6v.1M154.4 144.3v.1M154.4 145v.1M154.4 145.6v.1M154.4 146.3v.1M154.4 147v.1M154.4 147.7v.1M154.4 148.4v.1M154.4 149.1v.1M154.4 149.8v.1"/>
<path d="M154.4 150.5v.1M154.4 151.2v.1M154.4 151.9v.1M154.4 152.6v.1M154.4 153.2v.1M154.4 153.9v.1M154.4 154.6v.1M154.4 155.3v.1M154.4 156v.1M154.4 156.7v.1M154.4 157.4v.1M154.4 158.1v.1"/>
<path d="M154.4 158.8v.1M154.4 159.5v.1M55.4 160.2v.1M55.4 160.9h.1M55.4 161.5v.1M55.4 162.2v.1M55.4 162.9v.1M55.4 163.6v.1M55.4 164.3v.1M55.4 165v.1M55.4 165.7v.1M55.4 166.4v.1"/>
<path d="M55.4 167.1v.1M55.4 167.8v.1M55.4 168.5h.1M55.4 169.1v.1M55.4 169.8v.1M55.4 170.5v.1M55.4 171.2v.1M55.4 171.9v.1M55.4 172.6v.1M55.4 173.3l.1 .1M56.1 173.4h.1M56.8 173.4h.1"/>
<path d="M57.5 173.4h.1M58.2 173.4h.1M58.8 173.4h.1M59.5 173.4h.1M60.2 173.4h.1M60.9 173.4h.1M61.6 173.4h.1M62.3 173.4h.1M63 173.4h.1M63.7 173.4h.1M64.3 173.4h.1M65 173.4h.1"/>
<path d="M65.7 173.4h.1M66.4 173.4h.1M67.1 173.4h.1M67.8 173.4h.1M68.5 173.4h.1M69.2 173.4h.1M69.8 173.4h.1M70.5 173.4h.1M71.2 173.4h.1M71.3 169.6v.4M71.9 173.4h.1M72.6 173.4h.1"/>
<path d="M73.3 173.4h.1M74 173.4h.1M74.7 173.4h.1M75.3 173.4h.1M76 173.4h.1M76.7 173.4h.1M77.4 173.4h.1M78.1 173.4h.1M78.8 173.4h.1M79.5 173.4h.1M80.2 173.4h.1M80.8 173.4h.1"/>
<path d="M81.5 173.4h.1M82.2 173.4h.1M82.9 173.4h.1M83.6 173.4h.1M84.3 173.4h.1M85 173.4h.1M85.6 173.4h.1M86.3 173.4h.1M87 173.4h.1M87.7 173.4h.1M88.4 173.4h.1M89.1 173.4h.1"/>
<path d="M89.8 173.4h.1M90.5 173.4h.1M91.1 173.4h.1M91.8 173.4h.1M92.5 173.4h.1M93.2 173.4h.1M93.9 173.4h.1M94.6 173.4h.1M95.3 173.4h.1M95.9 173.4h.1M96.6 173.4h.1M97.3 173.4h.1"/>
<path d="M98 173.4h.1M98.7 173.4h.1M99.4 173.4h.1M100.1 173.4h.1M100.8 173.4h.1M101.5 173.4h.1M102.1 173.4h.1M102.8 173.4h.1M103.5 173.4h.1M104.2 173.4h.1M104.9 173.4h.1M105.6 173.4h.1"/>
<path d="M106.3 173.4h.1M107 173.4h.1M107.6 173.4h.1M108.3 173.4h.1M109 173.4h.1M109.7 173.4h.1M110.4 173.4h.1M111.1 173.4h.1M111.8 173.4h.1M112.4 173.4h.1M113.1 173.4h.1M113.8 173.4h.1"/>
<path d="M114.5 173.4h.1M115.2 173.4h.1M115.9 173.4h.1M116.6 173.4h.1M117.3 173.4h.1M117.9 173.4h.1M118.6 173.4h.1M119.3 173.4h.1M120 173.4h.1M120.7 173.4h.1M121.4 173.4h.1M122.1 173.4h.1"/>
<path d="M122.7 173.4h.1M123.4 173.4h.1M124.1 173.4h.1M124.8 173.4h.1M125.5 173.4h.1M126.2 173.4h.1M126.9 173.4h.1M127.6 173.4h.1M128.2 173.4h.1M128.9 173.4h.1M129.6 173.4h.1M130.3 173.4h.1"/>
<path d="M131 173.4h.1M131.7 173.4h.1M132.4 173.4h.1M133.1 173.4h.1M133.8 173.4h.1M134.4 173.4h.1M135.1 173.4h.1M135.8 173.4h.1M136.5 173.4h.1M137.2 173.4h.1M137.9 173.4h.1M138.6 173.4h.1"/>
<path d="M139.2 173.4h.1M139.9 173.4h.1M140.6 173.4h.1M141.3 173.4h.1M142 173.4h.1M142.7 173.4h.1M143.4 173.4h.1M144.1 173.4h.1M144.7 173.4h.1M145.4 173.4h.1M146.1 173.4h.1M146.8 173.4h.1"/>
<path d="M147.5 173.4h.1M148.2 173.4h.1M148.9 173.4h.1M149.5 173.4h.1M150.2 173.4h.1M150.9 173.4h.1M151.6 173.4h.1M152.3 173.4h.1M153 173.4h.1M153.7 173.4h.1M154.4 160.2v.1M154.4 160.9h.1"/>
<path d="M154.4 161.5v.1M154.4 162.2v.1M154.4 162.9v.1M154.4 163.6v.1M154.4 164.3v.1M154.4 165v.1M154.4 165.7v.1M154.4 166.4v.1M154.4 167.1v.1M154.4 167.8v.1M154.4 168.5h.1M154.4 169.1v.1"/>
<path d="M154.4 169.8v.1M154.4 170.5v.1M154.4 171.2v.1M154.4 171.9v.1M154.4 172.6v.1M154.4 173.3v.1"/>
</g>
<path d="M146.8 132.8h1.3l1.3 1.3h.5l.9 .8v2.5l1.7 1.7" fill="none" stroke="#800000" stroke-width=".61"/>
<g fill="none" stroke="#800000" stroke-width=".51">
<path d="M59.2 134.7v10.8l1.9 1.2M59.2 134.7h.1M63 132.8h-1.2l-1.3 1.2h-.6l-.7 .7M65.6 130.2v2l-2 1.9h-1.3l-1.8 1.8M68.1 130.2l-1.3 1.3v.6l-3.8 3.8M70.7 130.2l-5.1 5.1v.6M73.2 130.2l-5.1 5.1v.6M75.7 130.2l-5 5.1v.6M78.3 130.2l-5.1 5.1v.6M80.8 130.2l-5.1 5.1v.6M83.4 130.2l-5.1 5.1v.6M85.9 130.2l-2.5 2.6v3.1"/>
<path d="M88.4 130.2l-2.5 2.6v3.1M91 130.2l-2.6 2.6v3.1M93.5 130.2l-2.5 2.6v3.1M96 130.2l-2.5 2.6v3.1M98.6 130.2l-2.6 2.6v3.1M101.1 130.2l-2.5 2.6v3.1M103.7 130.2l-2.6 2.6v3.1M106.2 130.2v5.7M108.7 130.2v5.7M111.3 130.2v5.7M113.8 130.2v5.7M116.4 130.2v5.7"/>
<path d="M118.9 130.2v5.7M121.4 130.2v5.7M124 130.2v5.7M126.5 130.2l2.6 2.6v3.1M129.1 130.2l2.5 2.6v3.1M131.6 130.2l2.5 2.6v3.1M134.1 130.2l2.6 2.6v3.1M136.7 130.2l2.5 2.6v3.1M139.2 130.2l2.5 2.6v3.1M141.7 130.2l2.6 2.6v3.1M144.3 130.2l.9 1v3.1l1.6 1.6M149.4 135.9v2.6l3.1 3.1"/>
<path d="M98.6 143.6v4.7l-3.5 3.5M99.8 158.8v5.7l2.6 2.5h.3M102.7 156.9h-2.9l-1.9 1.9v8.9l-.6 .6h-5.4l-1.3 1.3M114.1 156.9l-2.3 2.4v7.3l-1.8 1.7h-6l-1.3 1.3M125.6 156.9l-2.4 2.4v4.6l-3 3v.8l-.7 .6h-4.1l-1.3 1.3M141.1 154.3l-1.3 1.3h-3.8l-1.2 1.3h-4.8M141.1 149.3l-1.3 1.2h-8.5l-1.3 1.3M141.1 151.8l-1.3 1.3h-3.8l-1.2 1.2h-4.8M141.1 156.9l-1.3 1.3h-4.4l-1.3 1.2h-4.1M141.1 159.4l-1.3 1.3h-4.4l-1.3 1.2h-4.1M146.8 143.6l-1.9 1.9h-8.2l-3.8 3.8h-3.2l-1.9 1.9v.9l-2.2 2.2M141.1 164.5l-1.3 1.3h-4.4l-1.3 1.2h-4.1"/>
<path d="M141.1 161.9l-1.3 1.3h-4.4l-1.3 1.3h-4.1"/>
</g>
<g fill="none" stroke="#800000" stroke-width=".83">
<path d="M57.3 147.4h1.9l1.9 1.9M57.3 149.9h1.9l1.9 1.9M57.3 157.5h1.9l1.9 1.9M57.3 155h1.9l1.9 1.9M57.3 152.4h1.9l1.9 1.9M68.7 151.8h2.6M68.7 154.3h2.6M68.7 156.9h2.6M68.7 159.4h2.6M148.7 151.8h3.2l.6 .6M148.7 154.3h3.2l.6 .7M148.7 156.9h3.2l.6 .6"/>
<path d="M148.7 159.4h3.2l.6 .6M148.7 149.3h3.2l.6 .6M148.7 146.7h3.2l.6 .7M57.3 165.1h1.9l1.9 1.9M57.3 162.6h1.9l1.9 1.9M57.3 160h1.9l1.9 1.9M68.7 161.9h2.6M68.7 164.5h2.6M68.7 167h2.6M148.7 161.9h3.2l.6 .7M148.7 164.5h3.2l.6 .6"/>
</g>
<circle cx="57.3" cy="165.1" r=".93" fill="#008000" stroke="#008000" stroke-width=".18"/>
<circle cx="57.3" cy="165.1" r=".51" fill="#fff" stroke="#000" stroke-width=".18"/>
<circle cx="57.3" cy="162.6" r=".93" fill="#008000" stroke="#008000" stroke-width=".18"/>
<circle cx="57.3" cy="162.6" r=".51" fill="#fff" stroke="#000" stroke-width=".18"/>
<circle cx="57.3" cy="160" r=".93" fill="#008000" stroke="#008000" stroke-width=".18"/>
<circle cx="57.3" cy="160" r=".51" fill="#fff" stroke="#000" stroke-width=".18"/>
<circle cx="57.3" cy="157.5" r=".93" fill="#008000" stroke="#008000" stroke-width=".18"/>
<circle cx="57.3" cy="157.5" r=".51" fill="#fff" stroke="#000" stroke-width=".18"/>
<circle cx="57.3" cy="155" r=".93" fill="#008000" stroke="#008000" stroke-width=".18"/>
<circle cx="57.3" cy="155" r=".51" fill="#fff" stroke="#000" stroke-width=".18"/>
<circle cx="57.3" cy="152.4" r=".93" fill="#008000" stroke="#008000" stroke-width=".18"/>
<circle cx="57.3" cy="152.4" r=".51" fill="#fff" stroke="#000" stroke-width=".18"/>
<circle cx="57.3" cy="149.9" r=".93" fill="#008000" stroke="#008000" stroke-width=".18"/>
<circle cx="57.3" cy="149.9" r=".51" fill="#fff" stroke="#000" stroke-width=".18"/>
<circle cx="57.3" cy="147.4" r=".93" fill="#008000" stroke="#008000" stroke-width=".18"/>
<circle cx="57.3" cy="147.4" r=".51" fill="#fff" stroke="#000" stroke-width=".18"/>
<circle cx="65.6" cy="130.2" r=".93" fill="#008000" stroke="#008000" stroke-width=".18"/>
<circle cx="65.6" cy="130.2" r=".51" fill="#fff" stroke="#000" stroke-width=".18"/>
<circle cx="68.1" cy="130.2" r=".93" fill="#008000" stroke="#008000" stroke-width=".18"/>
<circle cx="68.1" cy="130.2" r=".51" fill="#fff" stroke="#000" stroke-width=".18"/>
<circle cx="70.7" cy="130.2" r=".93" fill="#008000" stroke="#008000" stroke-width=".18"/>
<circle cx="70.7" cy="130.2" r=".51" fill="#fff" stroke="#000" stroke-width=".18"/>
<circle cx="73.2" cy="130.2" r=".93" fill="#008000" stroke="#008000" stroke-width=".18"/>
<circle cx="73.2" cy="130.2" r=".51" fill="#fff" stroke="#000" stroke-width=".18"/>
<circle cx="75.7" cy="130.2" r=".93" fill="#008000" stroke="#008000" stroke-width=".18"/>
<circle cx="75.7" cy="130.2" r=".51" fill="#fff" stroke="#000" stroke-width=".18"/>
<circle cx="78.3" cy="130.2" r=".93" fill="#008000" stroke="#008000" stroke-width=".18"/>
<circle cx="78.3" cy="130.2" r=".51" fill="#fff" stroke="#000" stroke-width=".18"/>
<circle cx="80.8" cy="130.2" r=".93" fill="#008000" stroke="#008000" stroke-width=".18"/>
<circle cx="80.8" cy="130.2" r=".51" fill="#fff" stroke="#000" stroke-width=".18"/>
<circle cx="83.4" cy="130.2" r=".93" fill="#008000" stroke="#008000" stroke-width=".18"/>
<circle cx="83.4" cy="130.2" r=".51" fill="#fff" stroke="#000" stroke-width=".18"/>
<circle cx="85.9" cy="130.2" r=".93" fill="#008000" stroke="#008000" stroke-width=".18"/>
<circle cx="85.9" cy="130.2" r=".51" fill="#fff" stroke="#000" stroke-width=".18"/>
<circle cx="88.4" cy="130.2" r=".93" fill="#008000" stroke="#008000" stroke-width=".18"/>
<circle cx="88.4" cy="130.2" r=".51" fill="#fff" stroke="#000" stroke-width=".18"/>
<circle cx="91" cy="130.2" r=".93" fill="#008000" stroke="#008000" stroke-width=".18"/>
<circle cx="91" cy="130.2" r=".51" fill="#fff" stroke="#000" stroke-width=".18"/>
<circle cx="93.5" cy="130.2" r=".93" fill="#008000" stroke="#008000" stroke-width=".18"/>
<circle cx="93.5" cy="130.2" r=".51" fill="#fff" stroke="#000" stroke-width=".18"/>
<circle cx="96" cy="130.2" r=".93" fill="#008000" stroke="#008000" stroke-width=".18"/>
<circle cx="96" cy="130.2" r=".51" fill="#fff" stroke="#000" stroke-width=".18"/>
<circle cx="98.6" cy="130.2" r=".93" fill="#008000" stroke="#008000" stroke-width=".18"/>
<circle cx="98.6" cy="130.2" r=".51" fill="#fff" stroke="#000" stroke-width=".18"/>
<circle cx="101.1" cy="130.2" r=".93" fill="#008000" stroke="#008000" stroke-width=".18"/>
<circle cx="101.1" cy="130.2" r=".51" fill="#fff" stroke="#000" stroke-width=".18"/>
<circle cx="103.7" cy="130.2" r=".93" fill="#008000" stroke="#008000" stroke-width=".18"/>
<circle cx="103.7" cy="130.2" r=".51" fill="#fff" stroke="#000" stroke-width=".18"/>
<circle cx="106.2" cy="130.2" r=".93" fill="#008000" stroke="#008000" stroke-width=".18"/>
<circle cx="106.2" cy="130.2" r=".51" fill="#fff" stroke="#000" stroke-width=".18"/>
<circle cx="108.7" cy="130.2" r=".93" fill="#008000" stroke="#008000" stroke-width=".18"/>
<circle cx="108.7" cy="130.2" r=".51" fill="#fff" stroke="#000" stroke-width=".18"/>
<circle cx="111.3" cy="130.2" r=".93" fill="#008000" stroke="#008000" stroke-width=".18"/>
<circle cx="111.3" cy="130.2" r=".51" fill="#fff" stroke="#000" stroke-width=".18"/>
<circle cx="113.8" cy="130.2" r=".93" fill="#008000" stroke="#008000" stroke-width=".18"/>
<circle cx="113.8" cy="130.2" r=".51" fill="#fff" stroke="#000" stroke-width=".18"/>
<circle cx="116.4" cy="130.2" r=".93" fill="#008000" stroke="#008000" stroke-width=".18"/>
<circle cx="116.4" cy="130.2" r=".51" fill="#fff" stroke="#000" stroke-width=".18"/>
<circle cx="118.9" cy="130.2" r=".93" fill="#008000" stroke="#008000" stroke-width=".18"/>
<circle cx="118.9" cy="130.2" r=".51" fill="#fff" stroke="#000" stroke-width=".18"/>
<circle cx="121.4" cy="130.2" r=".93" fill="#008000" stroke="#008000" stroke-width=".18"/>
<circle cx="121.4" cy="130.2" r=".51" fill="#fff" stroke="#000" stroke-width=".18"/>
<circle cx="124" cy="130.2" r=".93" fill="#008000" stroke="#008000" stroke-width=".18"/>
<circle cx="124" cy="130.2" r=".51" fill="#fff" stroke="#000" stroke-width=".18"/>
<circle cx="126.5" cy="130.2" r=".93" fill="#008000" stroke="#008000" stroke-width=".18"/>
<circle cx="126.5" cy="130.2" r=".51" fill="#fff" stroke="#000" stroke-width=".18"/>
<circle cx="129.1" cy="130.2" r=".93" fill="#008000" stroke="#008000" stroke-width=".18"/>
<circle cx="129.1" cy="130.2" r=".51" fill="#fff" stroke="#000" stroke-width=".18"/>
<circle cx="131.6" cy="130.2" r=".93" fill="#008000" stroke="#008000" stroke-width=".18"/>
<circle cx="131.6" cy="130.2" r=".51" fill="#fff" stroke="#000" stroke-width=".18"/>
<circle cx="134.1" cy="130.2" r=".93" fill="#008000" stroke="#008000" stroke-width=".18"/>
<circle cx="134.1" cy="130.2" r=".51" fill="#fff" stroke="#000" stroke-width=".18"/>
<circle cx="136.7" cy="130.2" r=".93" fill="#008000" stroke="#008000" stroke-width=".18"/>
<circle cx="136.7" cy="130.2" r=".51" fill="#fff" stroke="#000" stroke-width=".18"/>
<circle cx="139.2" cy="130.2" r=".93" fill="#008000" stroke="#008000" stroke-width=".18"/>
<circle cx="139.2" cy="130.2" r=".51" fill="#fff" stroke="#000" stroke-width=".18"/>
<circle cx="141.7" cy="130.2" r=".93" fill="#008000" stroke="#008000" stroke-width=".18"/>
<circle cx="141.7" cy="130.2" r=".51" fill="#fff" stroke="#000" stroke-width=".18"/>
<circle cx="144.3" cy="130.2" r=".93" fill="#008000" stroke="#008000" stroke-width=".18"/>
<circle cx="144.3" cy="130.2" r=".51" fill="#fff" stroke="#000" stroke-width=".18"/>
<circle cx="152.5" cy="165.1" r=".93" fill="#008000" stroke="#008000" stroke-width=".18"/>
<circle cx="152.5" cy="165.1" r=".51" fill="#fff" stroke="#000" stroke-width=".18"/>
<circle cx="152.5" cy="162.6" r=".93" fill="#008000" stroke="#008000" stroke-width=".18"/>
<circle cx="152.5" cy="162.6" r=".51" fill="#fff" stroke="#000" stroke-width=".18"/>
<circle cx="152.5" cy="160" r=".93" fill="#008000" stroke="#008000" stroke-width=".18"/>
<circle cx="152.5" cy="160" r=".51" fill="#fff" stroke="#000" stroke-width=".18"/>
<circle cx="152.5" cy="157.5" r=".93" fill="#008000" stroke="#008000" stroke-width=".18"/>
<circle cx="152.5" cy="157.5" r=".51" fill="#fff" stroke="#000" stroke-width=".18"/>
<circle cx="152.5" cy="155" r=".93" fill="#008000" stroke="#008000" stroke-width=".18"/>
<circle cx="152.5" cy="155" r=".51" fill="#fff" stroke="#000" stroke-width=".18"/>
<circle cx="152.5" cy="152.4" r=".93" fill="#008000" stroke="#008000" stroke-width=".18"/>
<circle cx="152.5" cy="152.4" r=".51" fill="#fff" stroke="#000" stroke-width=".18"/>
<circle cx="152.5" cy="149.9" r=".93" fill="#008000" stroke="#008000" stroke-width=".18"/>
<circle cx="152.5" cy="149.9" r=".51" fill="#fff" stroke="#000" stroke-width=".18"/>
<circle cx="152.5" cy="147.4" r=".93" fill="#008000" stroke="#008000" stroke-width=".18"/>
<circle cx="152.5" cy="147.4" r=".51" fill="#fff" stroke="#000" stroke-width=".18"/>
<circle cx="63" cy="132.8" r=".93" fill="#008000" stroke="#008000" stroke-width=".18"/>
<circle cx="63" cy="132.8" r=".51" fill="#fff" stroke="#000" stroke-width=".18"/>
<circle cx="63" cy="130.2" r=".93" fill="#008000" stroke="#008000" stroke-width=".18"/>
<circle cx="63" cy="130.2" r=".51" fill="#fff" stroke="#000" stroke-width=".18"/>
<circle cx="146.8" cy="132.8" r=".93" fill="#008000" stroke="#008000" stroke-width=".18"/>
<circle cx="146.8" cy="132.8" r=".51" fill="#fff" stroke="#000" stroke-width=".18"/>
<circle cx="146.8" cy="130.2" r=".93" fill="#008000" stroke="#008000" stroke-width=".18"/>
<circle cx="146.8" cy="130.2" r=".51" fill="#fff" stroke="#000" stroke-width=".18"/>
<path d="M68.1 167h1.3" fill="none" stroke="#008000" stroke-width="1.3"/>
<circle cx="68.7" cy="167" r=".4" fill="#fff" stroke="#000" stroke-width=".18"/>
<path d="M68.1 164.5h1.3" fill="none" stroke="#008000" stroke-width="1.3"/>
<circle cx="68.7" cy="164.5" r=".4" fill="#fff" stroke="#000" stroke-width=".18"/>
<path d="M68.1 151.8h1.3" fill="none" stroke="#008000" stroke-width="1.3"/>
<circle cx="68.7" cy="151.8" r=".4" fill="#fff" stroke="#000" stroke-width=".18"/>
<path d="M68.1 149.3h1.3" fill="none" stroke="#008000" stroke-width="1.3"/>
<circle cx="68.7" cy="149.3" r=".4" fill="#fff" stroke="#000" stroke-width=".18"/>
<path d="M68.1 161.9h1.3" fill="none" stroke="#008000" stroke-width="1.3"/>
<circle cx="68.7" cy="161.9" r=".4" fill="#fff" stroke="#000" stroke-width=".18"/>
<path d="M68.1 159.4h1.3" fill="none" stroke="#008000" stroke-width="1.3"/>
<circle cx="68.7" cy="159.4" r=".4" fill="#fff" stroke="#000" stroke-width=".18"/>
<path d="M68.1 154.3h1.3" fill="none" stroke="#008000" stroke-width="1.3"/>
<circle cx="68.7" cy="154.3" r=".4" fill="#fff" stroke="#000" stroke-width=".18"/>
<path d="M68.1 156.9h1.3" fill="none" stroke="#008000" stroke-width="1.3"/>
<circle cx="68.7" cy="156.9" r=".4" fill="#fff" stroke="#000" stroke-width=".18"/>
<path d="M68.1 146.7h1.3" fill="none" stroke="#008000" stroke-width="1.3"/>
<circle cx="68.7" cy="146.7" r=".4" fill="#fff" stroke="#000" stroke-width=".18"/>
<path d="M60.5 146.7h1.3" fill="none" stroke="#008000" stroke-width="1.3"/>
<circle cx="61.1" cy="146.7" r=".4" fill="#fff" stroke="#000" stroke-width=".18"/>
<path d="M60.5 149.3h1.3" fill="none" stroke="#008000" stroke-width="1.3"/>
<circle cx="61.1" cy="149.3" r=".4" fill="#fff" stroke="#000" stroke-width=".18"/>
<path d="M60.5 151.8h1.3" fill="none" stroke="#008000" stroke-width="1.3"/>
<circle cx="61.1" cy="151.8" r=".4" fill="#fff" stroke="#000" stroke-width=".18"/>
<path d="M60.5 154.3h1.3" fill="none" stroke="#008000" stroke-width="1.3"/>
<circle cx="61.1" cy="154.3" r=".4" fill="#fff" stroke="#000" stroke-width=".18"/>
<path d="M60.5 156.9h1.3" fill="none" stroke="#008000" stroke-width="1.3"/>
<circle cx="61.1" cy="156.9" r=".4" fill="#fff" stroke="#000" stroke-width=".18"/>
<path d="M60.5 159.4h1.3" fill="none" stroke="#008000" stroke-width="1.3"/>
<circle cx="61.1" cy="159.4" r=".4" fill="#fff" stroke="#000" stroke-width=".18"/>
<path d="M60.5 161.9h1.3" fill="none" stroke="#008000" stroke-width="1.3"/>
<circle cx="61.1" cy="161.9" r=".4" fill="#fff" stroke="#000" stroke-width=".18"/>
<path d="M60.5 164.5h1.3" fill="none" stroke="#008000" stroke-width="1.3"/>
<circle cx="61.1" cy="164.5" r=".4" fill="#fff" stroke="#000" stroke-width=".18"/>
<path d="M60.5 167h1.3" fill="none" stroke="#008000" stroke-width="1.3"/>
<circle cx="61.1" cy="167" r=".4" fill="#fff" stroke="#000" stroke-width=".18"/>
<path d="M60.5 142.9v1.3" fill="none" stroke="#008000" stroke-width="1.3"/>
<circle cx="60.5" cy="143.6" r=".4" fill="#fff" stroke="#000" stroke-width=".18"/>
<path d="M63 142.9v1.3" fill="none" stroke="#008000" stroke-width="1.3"/>
<circle cx="63" cy="143.6" r=".4" fill="#fff" stroke="#000" stroke-width=".18"/>
<path d="M75.7 142.9v1.3" fill="none" stroke="#008000" stroke-width="1.3"/>
<circle cx="75.7" cy="143.6" r=".4" fill="#fff" stroke="#000" stroke-width=".18"/>
<path d="M78.3 142.9v1.3" fill="none" stroke="#008000" stroke-width="1.3"/>
<circle cx="78.3" cy="143.6" r=".4" fill="#fff" stroke="#000" stroke-width=".18"/>
<path d="M65.6 142.9v1.3" fill="none" stroke="#008000" stroke-width="1.3"/>
<circle cx="65.6" cy="143.6" r=".4" fill="#fff" stroke="#000" stroke-width=".18"/>
<path d="M68.1 142.9v1.3" fill="none" stroke="#008000" stroke-width="1.3"/>
<circle cx="68.1" cy="143.6" r=".4" fill="#fff" stroke="#000" stroke-width=".18"/>
<path d="M73.2 142.9v1.3" fill="none" stroke="#008000" stroke-width="1.3"/>
<circle cx="73.2" cy="143.6" r=".4" fill="#fff" stroke="#000" stroke-width=".18"/>
<path d="M70.7 142.9v1.3" fill="none" stroke="#008000" stroke-width="1.3"/>
<circle cx="70.7" cy="143.6" r=".4" fill="#fff" stroke="#000" stroke-width=".18"/>
<path d="M80.8 142.9v1.3" fill="none" stroke="#008000" stroke-width="1.3"/>
<circle cx="80.8" cy="143.6" r=".4" fill="#fff" stroke="#000" stroke-width=".18"/>
<path d="M80.8 135.3v1.3" fill="none" stroke="#008000" stroke-width="1.3"/>
<circle cx="80.8" cy="135.9" r=".4" fill="#fff" stroke="#000" stroke-width=".18"/>
<path d="M78.3 135.3v1.3" fill="none" stroke="#008000" stroke-width="1.3"/>
<circle cx="78.3" cy="135.9" r=".4" fill="#fff" stroke="#000" stroke-width=".18"/>
<path d="M75.7 135.3v1.3" fill="none" stroke="#008000" stroke-width="1.3"/>
<circle cx="75.7" cy="135.9" r=".4" fill="#fff" stroke="#000" stroke-width=".18"/>
<path d="M73.2 135.3v1.3" fill="none" stroke="#008000" stroke-width="1.3"/>
<circle cx="73.2" cy="135.9" r=".4" fill="#fff" stroke="#000" stroke-width=".18"/>
<path d="M70.7 135.3v1.3" fill="none" stroke="#008000" stroke-width="1.3"/>
<circle cx="70.7" cy="135.9" r=".4" fill="#fff" stroke="#000" stroke-width=".18"/>
<path d="M68.1 135.3v1.3" fill="none" stroke="#008000" stroke-width="1.3"/>
<circle cx="68.1" cy="135.9" r=".4" fill="#fff" stroke="#000" stroke-width=".18"/>
<path d="M65.6 135.3v1.3" fill="none" stroke="#008000" stroke-width="1.3"/>
<circle cx="65.6" cy="135.9" r=".4" fill="#fff" stroke="#000" stroke-width=".18"/>
<path d="M63 135.3v1.3" fill="none" stroke="#008000" stroke-width="1.3"/>
<circle cx="63" cy="135.9" r=".4" fill="#fff" stroke="#000" stroke-width=".18"/>
<path d="M60.5 135.3v1.3" fill="none" stroke="#008000" stroke-width="1.3"/>
<circle cx="60.5" cy="135.9" r=".4" fill="#fff" stroke="#000" stroke-width=".18"/>
<path d="M83.4 142.9v1.3" fill="none" stroke="#008000" stroke-width="1.3"/>
<circle cx="83.4" cy="143.6" r=".4" fill="#fff" stroke="#000" stroke-width=".18"/>
<path d="M85.9 142.9v1.3" fill="none" stroke="#008000" stroke-width="1.3"/>
<circle cx="85.9" cy="143.6" r=".4" fill="#fff" stroke="#000" stroke-width=".18"/>
<path d="M98.6 142.9v1.3" fill="none" stroke="#008000" stroke-width="1.3"/>
<circle cx="98.6" cy="143.6" r=".4" fill="#fff" stroke="#000" stroke-width=".18"/>
<path d="M101.1 142.9v1.3" fill="none" stroke="#008000" stroke-width="1.3"/>
<circle cx="101.1" cy="143.6" r=".4" fill="#fff" stroke="#000" stroke-width=".18"/>
<path d="M88.4 142.9v1.3" fill="none" stroke="#008000" stroke-width="1.3"/>
<circle cx="88.4" cy="143.6" r=".4" fill="#fff" stroke="#000" stroke-width=".18"/>
<path d="M91 142.9v1.3" fill="none" stroke="#008000" stroke-width="1.3"/>
<circle cx="91" cy="143.6" r=".4" fill="#fff" stroke="#000" stroke-width=".18"/>
<path d="M96 142.9v1.3" fill="none" stroke="#008000" stroke-width="1.3"/>
<circle cx="96" cy="143.6" r=".4" fill="#fff" stroke="#000" stroke-width=".18"/>
<path d="M93.5 142.9v1.3" fill="none" stroke="#008000" stroke-width="1.3"/>
<circle cx="93.5" cy="143.6" r=".4" fill="#fff" stroke="#000" stroke-width=".18"/>
<path d="M103.7 142.9v1.3" fill="none" stroke="#008000" stroke-width="1.3"/>
<circle cx="103.7" cy="143.6" r=".4" fill="#fff" stroke="#000" stroke-width=".18"/>
<path d="M103.7 135.3v1.3" fill="none" stroke="#008000" stroke-width="1.3"/>
<circle cx="103.7" cy="135.9" r=".4" fill="#fff" stroke="#000" stroke-width=".18"/>
<path d="M101.1 135.3v1.3" fill="none" stroke="#008000" stroke-width="1.3"/>
<circle cx="101.1" cy="135.9" r=".4" fill="#fff" stroke="#000" stroke-width=".18"/>
<path d="M98.6 135.3v1.3" fill="none" stroke="#008000" stroke-width="1.3"/>
<circle cx="98.6" cy="135.9" r=".4" fill="#fff" stroke="#000" stroke-width=".18"/>
<path d="M96 135.3v1.3" fill="none" stroke="#008000" stroke-width="1.3"/>
<circle cx="96" cy="135.9" r=".4" fill="#fff" stroke="#000" stroke-width=".18"/>
<path d="M93.5 135.3v1.3" fill="none" stroke="#008000" stroke-width="1.3"/>
<circle cx="93.5" cy="135.9" r=".4" fill="#fff" stroke="#000" stroke-width=".18"/>
<path d="M91 135.3v1.3" fill="none" stroke="#008000" stroke-width="1.3"/>
<circle cx="91" cy="135.9" r=".4" fill="#fff" stroke="#000" stroke-width=".18"/>
<path d="M88.4 135.3v1.3" fill="none" stroke="#008000" stroke-width="1.3"/>
<circle cx="88.4" cy="135.9" r=".4" fill="#fff" stroke="#000" stroke-width=".18"/>
<path d="M85.9 135.3v1.3" fill="none" stroke="#008000" stroke-width="1.3"/>
<circle cx="85.9" cy="135.9" r=".4" fill="#fff" stroke="#000" stroke-width=".18"/>
<path d="M83.4 135.3v1.3" fill="none" stroke="#008000" stroke-width="1.3"/>
<circle cx="83.4" cy="135.9" r=".4" fill="#fff" stroke="#000" stroke-width=".18"/>
<path d="M106.2 142.9v1.3" fill="none" stroke="#008000" stroke-width="1.3"/>
<circle cx="106.2" cy="143.6" r=".4" fill="#fff" stroke="#000" stroke-width=".18"/>
<path d="M108.7 142.9v1.3" fill="none" stroke="#008000" stroke-width="1.3"/>
<circle cx="108.7" cy="143.6" r=".4" fill="#fff" stroke="#000" stroke-width=".18"/>
<path d="M121.4 142.9v1.3" fill="none" stroke="#008000" stroke-width="1.3"/>
<circle cx="121.4" cy="143.6" r=".4" fill="#fff" stroke="#000" stroke-width=".18"/>
<path d="M124 142.9v1.3" fill="none" stroke="#008000" stroke-width="1.3"/>
<circle cx="124" cy="143.6" r=".4" fill="#fff" stroke="#000" stroke-width=".18"/>
<path d="M111.3 142.9v1.3" fill="none" stroke="#008000" stroke-width="1.3"/>
<circle cx="111.3" cy="143.6" r=".4" fill="#fff" stroke="#000" stroke-width=".18"/>
<path d="M113.8 142.9v1.3" fill="none" stroke="#008000" stroke-width="1.3"/>
<circle cx="113.8" cy="143.6" r=".4" fill="#fff" stroke="#000" stroke-width=".18"/>
<path d="M118.9 142.9v1.3" fill="none" stroke="#008000" stroke-width="1.3"/>
<circle cx="118.9" cy="143.6" r=".4" fill="#fff" stroke="#000" stroke-width=".18"/>
<path d="M116.4 142.9v1.3" fill="none" stroke="#008000" stroke-width="1.3"/>
<circle cx="116.4" cy="143.6" r=".4" fill="#fff" stroke="#000" stroke-width=".18"/>
<path d="M126.5 142.9v1.3" fill="none" stroke="#008000" stroke-width="1.3"/>
<circle cx="126.5" cy="143.6" r=".4" fill="#fff" stroke="#000" stroke-width=".18"/>
<path d="M126.5 135.3v1.3" fill="none" stroke="#008000" stroke-width="1.3"/>
<circle cx="126.5" cy="135.9" r=".4" fill="#fff" stroke="#000" stroke-width=".18"/>
<path d="M124 135.3v1.3" fill="none" stroke="#008000" stroke-width="1.3"/>
<circle cx="124" cy="135.9" r=".4" fill="#fff" stroke="#000" stroke-width=".18"/>
<path d="M121.4 135.3v1.3" fill="none" stroke="#008000" stroke-width="1.3"/>
<circle cx="121.4" cy="135.9" r=".4" fill="#fff" stroke="#000" stroke-width=".18"/>
<path d="M118.9 135.3v1.3" fill="none" stroke="#008000" stroke-width="1.3"/>
<circle cx="118.9" cy="135.9" r=".4" fill="#fff" stroke="#000" stroke-width=".18"/>
<path d="M116.4 135.3v1.3" fill="none" stroke="#008000" stroke-width="1.3"/>
<circle cx="116.4" cy="135.9" r=".4" fill="#fff" stroke="#000" stroke-width=".18"/>
<path d="M113.8 135.3v1.3" fill="none" stroke="#008000" stroke-width="1.3"/>
<circle cx="113.8" cy="135.9" r=".4" fill="#fff" stroke="#000" stroke-width=".18"/>
<path d="M111.3 135.3v1.3" fill="none" stroke="#008000" stroke-width="1.3"/>
<circle cx="111.3" cy="135.9" r=".4" fill="#fff" stroke="#000" stroke-width=".18"/>
<path d="M108.7 135.3v1.3" fill="none" stroke="#008000" stroke-width="1.3"/>
<circle cx="108.7" cy="135.9" r=".4" fill="#fff" stroke="#000" stroke-width=".18"/>
<path d="M106.2 135.3v1.3" fill="none" stroke="#008000" stroke-width="1.3"/>
<circle cx="106.2" cy="135.9" r=".4" fill="#fff" stroke="#000" stroke-width=".18"/>
<path d="M129.1 142.9v1.3" fill="none" stroke="#008000" stroke-width="1.3"/>
<circle cx="129.1" cy="143.6" r=".4" fill="#fff" stroke="#000" stroke-width=".18"/>
<path d="M131.6 142.9v1.3" fill="none" stroke="#008000" stroke-width="1.3"/>
<circle cx="131.6" cy="143.6" r=".4" fill="#fff" stroke="#000" stroke-width=".18"/>
<path d="M144.3 142.9v1.3" fill="none" stroke="#008000" stroke-width="1.3"/>
<circle cx="144.3" cy="143.6" r=".4" fill="#fff" stroke="#000" stroke-width=".18"/>
<path d="M146.8 142.9v1.3" fill="none" stroke="#008000" stroke-width="1.3"/>
<circle cx="146.8" cy="143.6" r=".4" fill="#fff" stroke="#000" stroke-width=".18"/>
<path d="M134.1 142.9v1.3" fill="none" stroke="#008000" stroke-width="1.3"/>
<circle cx="134.1" cy="143.6" r=".4" fill="#fff" stroke="#000" stroke-width=".18"/>
<path d="M136.7 142.9v1.3" fill="none" stroke="#008000" stroke-width="1.3"/>
<circle cx="136.7" cy="143.6" r=".4" fill="#fff" stroke="#000" stroke-width=".18"/>
<path d="M141.7 142.9v1.3" fill="none" stroke="#008000" stroke-width="1.3"/>
<circle cx="141.7" cy="143.6" r=".4" fill="#fff" stroke="#000" stroke-width=".18"/>
<path d="M139.2 142.9v1.3" fill="none" stroke="#008000" stroke-width="1.3"/>
<circle cx="139.2" cy="143.6" r=".4" fill="#fff" stroke="#000" stroke-width=".18"/>
<path d="M149.4 142.9v1.3" fill="none" stroke="#008000" stroke-width="1.3"/>
<circle cx="149.4" cy="143.6" r=".4" fill="#fff" stroke="#000" stroke-width=".18"/>
<path d="M149.4 135.3v1.3" fill="none" stroke="#008000" stroke-width="1.3"/>
<circle cx="149.4" cy="135.9" r=".4" fill="#fff" stroke="#000" stroke-width=".18"/>
<path d="M146.8 135.3v1.3" fill="none" stroke="#008000" stroke-width="1.3"/>
<circle cx="146.8" cy="135.9" r=".4" fill="#fff" stroke="#000" stroke-width=".18"/>
<path d="M144.3 135.3v1.3" fill="none" stroke="#008000" stroke-width="1.3"/>
<circle cx="144.3" cy="135.9" r=".4" fill="#fff" stroke="#000" stroke-width=".18"/>
<path d="M141.7 135.3v1.3" fill="none" stroke="#008000" stroke-width="1.3"/>
<circle cx="141.7" cy="135.9" r=".4" fill="#fff" stroke="#000" stroke-width=".18"/>
<path d="M139.2 135.3v1.3" fill="none" stroke="#008000" stroke-width="1.3"/>
<circle cx="139.2" cy="135.9" r=".4" fill="#fff" stroke="#000" stroke-width=".18"/>
<path d="M136.7 135.3v1.3" fill="none" stroke="#008000" stroke-width="1.3"/>
<circle cx="136.7" cy="135.9" r=".4" fill="#fff" stroke="#000" stroke-width=".18"/>
<path d="M134.1 135.3v1.3" fill="none" stroke="#008000" stroke-width="1.3"/>
<circle cx="134.1" cy="135.9" r=".4" fill="#fff" stroke="#000" stroke-width=".18"/>
<path d="M131.6 135.3v1.3" fill="none" stroke="#008000" stroke-width="1.3"/>
<circle cx="131.6" cy="135.9" r=".4" fill="#fff" stroke="#000" stroke-width=".18"/>
<path d="M129.1 135.3v1.3" fill="none" stroke="#008000" stroke-width="1.3"/>
<circle cx="129.1" cy="135.9" r=".4" fill="#fff" stroke="#000" stroke-width=".18"/>
<path d="M140.4 146.7h1.4" fill="none" stroke="#008000" stroke-width="1.3"/>
<circle cx="141.1" cy="146.7" r=".4" fill="#fff" stroke="#000" stroke-width=".18"/>
<path d="M140.4 149.3h1.4" fill="none" stroke="#008000" stroke-width="1.3"/>
<circle cx="141.1" cy="149.3" r=".4" fill="#fff" stroke="#000" stroke-width=".18"/>
<path d="M140.4 161.9h1.4" fill="none" stroke="#008000" stroke-width="1.3"/>
<circle cx="141.1" cy="161.9" r=".4" fill="#fff" stroke="#000" stroke-width=".18"/>
<path d="M140.4 164.5h1.4" fill="none" stroke="#008000" stroke-width="1.3"/>
<circle cx="141.1" cy="164.5" r=".4" fill="#fff" stroke="#000" stroke-width=".18"/>
<path d="M140.4 151.8h1.4" fill="none" stroke="#008000" stroke-width="1.3"/>
<circle cx="141.1" cy="151.8" r=".4" fill="#fff" stroke="#000" stroke-width=".18"/>
<path d="M140.4 154.3h1.4" fill="none" stroke="#008000" stroke-width="1.3"/>
<circle cx="141.1" cy="154.3" r=".4" fill="#fff" stroke="#000" stroke-width=".18"/>
<path d="M140.4 159.4h1.4" fill="none" stroke="#008000" stroke-width="1.3"/>
<circle cx="141.1" cy="159.4" r=".4" fill="#fff" stroke="#000" stroke-width=".18"/>
<path d="M140.4 156.9h1.4" fill="none" stroke="#008000" stroke-width="1.3"/>
<circle cx="141.1" cy="156.9" r=".4" fill="#fff" stroke="#000" stroke-width=".18"/>
<path d="M140.4 167h1.4" fill="none" stroke="#008000" stroke-width="1.3"/>
<circle cx="141.1" cy="167" r=".4" fill="#fff" stroke="#000" stroke-width=".18"/>
<path d="M148.1 167h1.3" fill="none" stroke="#008000" stroke-width="1.3"/>
<circle cx="148.7" cy="167" r=".4" fill="#fff" stroke="#000" stroke-width=".18"/>
<path d="M148.1 164.5h1.3" fill="none" stroke="#008000" stroke-width="1.3"/>
<circle cx="148.7" cy="164.5" r=".4" fill="#fff" stroke="#000" stroke-width=".18"/>
<path d="M148.1 161.9h1.3" fill="none" stroke="#008000" stroke-width="1.3"/>
<circle cx="148.7" cy="161.9" r=".4" fill="#fff" stroke="#000" stroke-width=".18"/>
<path d="M148.1 159.4h1.3" fill="none" stroke="#008000" stroke-width="1.3"/>
<circle cx="148.7" cy="159.4" r=".4" fill="#fff" stroke="#000" stroke-width=".18"/>
<path d="M148.1 156.9h1.3" fill="none" stroke="#008000" stroke-width="1.3"/>
<circle cx="148.7" cy="156.9" r=".4" fill="#fff" stroke="#000" stroke-width=".18"/>
<path d="M148.1 154.3h1.3" fill="none" stroke="#008000" stroke-width="1.3"/>
<circle cx="148.7" cy="154.3" r=".4" fill="#fff" stroke="#000" stroke-width=".18"/>
<path d="M148.1 151.8h1.3" fill="none" stroke="#008000" stroke-width="1.3"/>
<circle cx="148.7" cy="151.8" r=".4" fill="#fff" stroke="#000" stroke-width=".18"/>
<path d="M148.1 149.3h1.3" fill="none" stroke="#008000" stroke-width="1.3"/>
<circle cx="148.7" cy="149.3" r=".4" fill="#fff" stroke="#000" stroke-width=".18"/>
<path d="M148.1 146.7h1.3" fill="none" stroke="#008000" stroke-width="1.3"/>
<circle cx="148.7" cy="146.7" r=".4" fill="#fff" stroke="#000" stroke-width=".18"/>
<path d="M70.6 151.8h1.3" fill="none" stroke="#008000" stroke-width="1.3"/>
<circle cx="71.3" cy="151.8" r=".4" fill="#fff" stroke="#000" stroke-width=".18"/>
<path d="M70.6 154.3h1.3" fill="none" stroke="#008000" stroke-width="1.3"/>
<circle cx="71.3" cy="154.3" r=".4" fill="#fff" stroke="#000" stroke-width=".18"/>
<path d="M70.6 167h1.3" fill="none" stroke="#008000" stroke-width="1.3"/>
<circle cx="71.3" cy="167" r=".4" fill="#fff" stroke="#000" stroke-width=".18"/>
<path d="M70.6 169.6h1.3" fill="none" stroke="#008000" stroke-width="1.3"/>
<circle cx="71.3" cy="169.6" r=".4" fill="#fff" stroke="#000" stroke-width=".18"/>
<path d="M70.6 156.9h1.3" fill="none" stroke="#008000" stroke-width="1.3"/>
<circle cx="71.3" cy="156.9" r=".4" fill="#fff" stroke="#000" stroke-width=".18"/>
<path d="M70.6 159.4h1.3" fill="none" stroke="#008000" stroke-width="1.3"/>
<circle cx="71.3" cy="159.4" r=".4" fill="#fff" stroke="#000" stroke-width=".18"/>
<path d="M70.6 164.5h1.3" fill="none" stroke="#008000" stroke-width="1.3"/>
<circle cx="71.3" cy="164.5" r=".4" fill="#fff" stroke="#000" stroke-width=".18"/>
<path d="M70.6 161.9h1.3" fill="none" stroke="#008000" stroke-width="1.3"/>
<circle cx="71.3" cy="161.9" r=".4" fill="#fff" stroke="#000" stroke-width=".18"/>
<path d="M78.2 169.6h1.4" fill="none" stroke="#008000" stroke-width="1.3"/>
<circle cx="78.9" cy="169.6" r=".4" fill="#fff" stroke="#000" stroke-width=".18"/>
<path d="M78.2 167h1.4" fill="none" stroke="#008000" stroke-width="1.3"/>
<circle cx="78.9" cy="167" r=".4" fill="#fff" stroke="#000" stroke-width=".18"/>
<path d="M78.2 164.5h1.4" fill="none" stroke="#008000" stroke-width="1.3"/>
<circle cx="78.9" cy="164.5" r=".4" fill="#fff" stroke="#000" stroke-width=".18"/>
<path d="M78.2 161.9h1.4" fill="none" stroke="#008000" stroke-width="1.3"/>
<circle cx="78.9" cy="161.9" r=".4" fill="#fff" stroke="#000" stroke-width=".18"/>
<path d="M78.2 159.4h1.4" fill="none" stroke="#008000" stroke-width="1.3"/>
<circle cx="78.9" cy="159.4" r=".4" fill="#fff" stroke="#000" stroke-width=".18"/>
<path d="M78.2 156.9h1.4" fill="none" stroke="#008000" stroke-width="1.3"/>
<circle cx="78.9" cy="156.9" r=".4" fill="#fff" stroke="#000" stroke-width=".18"/>
<path d="M78.2 154.3h1.4" fill="none" stroke="#008000" stroke-width="1.3"/>
<circle cx="78.9" cy="154.3" r=".4" fill="#fff" stroke="#000" stroke-width=".18"/>
<path d="M78.2 151.8h1.4" fill="none" stroke="#008000" stroke-width="1.3"/>
<circle cx="78.9" cy="151.8" r=".4" fill="#fff" stroke="#000" stroke-width=".18"/>
<path d="M82.4 151.8h1.3" fill="none" stroke="#008000" stroke-width="1.3"/>
<circle cx="83" cy="151.8" r=".4" fill="#fff" stroke="#000" stroke-width=".18"/>
<path d="M82.4 154.3h1.3" fill="none" stroke="#008000" stroke-width="1.3"/>
<circle cx="83" cy="154.3" r=".4" fill="#fff" stroke="#000" stroke-width=".18"/>
<path d="M82.4 167h1.3" fill="none" stroke="#008000" stroke-width="1.3"/>
<circle cx="83" cy="167" r=".4" fill="#fff" stroke="#000" stroke-width=".18"/>
<path d="M82.4 169.6h1.3" fill="none" stroke="#008000" stroke-width="1.3"/>
<circle cx="83" cy="169.6" r=".4" fill="#fff" stroke="#000" stroke-width=".18"/>
<path d="M82.4 156.9h1.3" fill="none" stroke="#008000" stroke-width="1.3"/>
<circle cx="83" cy="156.9" r=".4" fill="#fff" stroke="#000" stroke-width=".18"/>
<path d="M82.4 159.4h1.3" fill="none" stroke="#008000" stroke-width="1.3"/>
<circle cx="83" cy="159.4" r=".4" fill="#fff" stroke="#000" stroke-width=".18"/>
<path d="M82.4 164.5h1.3" fill="none" stroke="#008000" stroke-width="1.3"/>
<circle cx="83" cy="164.5" r=".4" fill="#fff" stroke="#000" stroke-width=".18"/>
<path d="M82.4 161.9h1.3" fill="none" stroke="#008000" stroke-width="1.3"/>
<circle cx="83" cy="161.9" r=".4" fill="#fff" stroke="#000" stroke-width=".18"/>
<path d="M90 169.6h1.3" fill="none" stroke="#008000" stroke-width="1.3"/>
<circle cx="90.6" cy="169.6" r=".4" fill="#fff" stroke="#000" stroke-width=".18"/>
<path d="M90 167h1.3" fill="none" stroke="#008000" stroke-width="1.3"/>
<circle cx="90.6" cy="167" r=".4" fill="#fff" stroke="#000" stroke-width=".18"/>
<path d="M90 164.5h1.3" fill="none" stroke="#008000" stroke-width="1.3"/>
<circle cx="90.6" cy="164.5" r=".4" fill="#fff" stroke="#000" stroke-width=".18"/>
<path d="M90 161.9h1.3" fill="none" stroke="#008000" stroke-width="1.3"/>
<circle cx="90.6" cy="161.9" r=".4" fill="#fff" stroke="#000" stroke-width=".18"/>
<path d="M90 159.4h1.3" fill="none" stroke="#008000" stroke-width="1.3"/>
<circle cx="90.6" cy="159.4" r=".4" fill="#fff" stroke="#000" stroke-width=".18"/>
<path d="M90 156.9h1.3" fill="none" stroke="#008000" stroke-width="1.3"/>
<circle cx="90.6" cy="156.9" r=".4" fill="#fff" stroke="#000" stroke-width=".18"/>
<path d="M90 154.3h1.3" fill="none" stroke="#008000" stroke-width="1.3"/>
<circle cx="90.6" cy="154.3" r=".4" fill="#fff" stroke="#000" stroke-width=".18"/>
<path d="M90 151.8h1.3" fill="none" stroke="#008000" stroke-width="1.3"/>
<circle cx="90.6" cy="151.8" r=".4" fill="#fff" stroke="#000" stroke-width=".18"/>
<path d="M94.4 151.8h1.3" fill="none" stroke="#008000" stroke-width="1.3"/>
<circle cx="95.1" cy="151.8" r=".4" fill="#fff" stroke="#000" stroke-width=".18"/>
<path d="M94.4 154.3h1.3" fill="none" stroke="#008000" stroke-width="1.3"/>
<circle cx="95.1" cy="154.3" r=".4" fill="#fff" stroke="#000" stroke-width=".18"/>
<path d="M94.4 167h1.3" fill="none" stroke="#008000" stroke-width="1.3"/>
<circle cx="95.1" cy="167" r=".4" fill="#fff" stroke="#000" stroke-width=".18"/>
<path d="M94.4 169.6h1.3" fill="none" stroke="#008000" stroke-width="1.3"/>
<circle cx="95.1" cy="169.6" r=".4" fill="#fff" stroke="#000" stroke-width=".18"/>
<path d="M94.4 156.9h1.3" fill="none" stroke="#008000" stroke-width="1.3"/>
<circle cx="95.1" cy="156.9" r=".4" fill="#fff" stroke="#000" stroke-width=".18"/>
<path d="M94.4 159.4h1.3" fill="none" stroke="#008000" stroke-width="1.3"/>
<circle cx="95.1" cy="159.4" r=".4" fill="#fff" stroke="#000" stroke-width=".18"/>
<path d="M94.4 164.5h1.3" fill="none" stroke="#008000" stroke-width="1.3"/>
<circle cx="95.1" cy="164.5" r=".4" fill="#fff" stroke="#000" stroke-width=".18"/>
<path d="M94.4 161.9h1.3" fill="none" stroke="#008000" stroke-width="1.3"/>
<circle cx="95.1" cy="161.9" r=".4" fill="#fff" stroke="#000" stroke-width=".18"/>
<path d="M102 169.6h1.4" fill="none" stroke="#008000" stroke-width="1.3"/>
<circle cx="102.7" cy="169.6" r=".4" fill="#fff" stroke="#000" stroke-width=".18"/>
<path d="M102 167h1.4" fill="none" stroke="#008000" stroke-width="1.3"/>
<circle cx="102.7" cy="167" r=".4" fill="#fff" stroke="#000" stroke-width=".18"/>
<path d="M102 164.5h1.4" fill="none" stroke="#008000" stroke-width="1.3"/>
<circle cx="102.7" cy="164.5" r=".4" fill="#fff" stroke="#000" stroke-width=".18"/>
<path d="M102 161.9h1.4" fill="none" stroke="#008000" stroke-width="1.3"/>
<circle cx="102.7" cy="161.9" r=".4" fill="#fff" stroke="#000" stroke-width=".18"/>
<path d="M102 159.4h1.4" fill="none" stroke="#008000" stroke-width="1.3"/>
<circle cx="102.7" cy="159.4" r=".4" fill="#fff" stroke="#000" stroke-width=".18"/>
<path d="M102 156.9h1.4" fill="none" stroke="#008000" stroke-width="1.3"/>
<circle cx="102.7" cy="156.9" r=".4" fill="#fff" stroke="#000" stroke-width=".18"/>
<path d="M102 154.3h1.4" fill="none" stroke="#008000" stroke-width="1.3"/>
<circle cx="102.7" cy="154.3" r=".4" fill="#fff" stroke="#000" stroke-width=".18"/>
<path d="M102 151.8h1.4" fill="none" stroke="#008000" stroke-width="1.3"/>
<circle cx="102.7" cy="151.8" r=".4" fill="#fff" stroke="#000" stroke-width=".18"/>
<path d="M105.9 151.8h1.3" fill="none" stroke="#008000" stroke-width="1.3"/>
<circle cx="106.5" cy="151.8" r=".4" fill="#fff" stroke="#000" stroke-width=".18"/>
<path d="M105.9 154.3h1.3" fill="none" stroke="#008000" stroke-width="1.3"/>
<circle cx="106.5" cy="154.3" r=".4" fill="#fff" stroke="#000" stroke-width=".18"/>
<path d="M105.9 167h1.3" fill="none" stroke="#008000" stroke-width="1.3"/>
<circle cx="106.5" cy="167" r=".4" fill="#fff" stroke="#000" stroke-width=".18"/>
<path d="M105.9 169.6h1.3" fill="none" stroke="#008000" stroke-width="1.3"/>
<circle cx="106.5" cy="169.6" r=".4" fill="#fff" stroke="#000" stroke-width=".18"/>
<path d="M105.9 156.9h1.3" fill="none" stroke="#008000" stroke-width="1.3"/>
<circle cx="106.5" cy="156.9" r=".4" fill="#fff" stroke="#000" stroke-width=".18"/>
<path d="M105.9 159.4h1.3" fill="none" stroke="#008000" stroke-width="1.3"/>
<circle cx="106.5" cy="159.4" r=".4" fill="#fff" stroke="#000" stroke-width=".18"/>
<path d="M105.9 164.5h1.3" fill="none" stroke="#008000" stroke-width="1.3"/>
<circle cx="106.5" cy="164.5" r=".4" fill="#fff" stroke="#000" stroke-width=".18"/>
<path d="M105.9 161.9h1.3" fill="none" stroke="#008000" stroke-width="1.3"/>
<circle cx="106.5" cy="161.9" r=".4" fill="#fff" stroke="#000" stroke-width=".18"/>
<path d="M113.5 169.6h1.3" fill="none" stroke="#008000" stroke-width="1.3"/>
<circle cx="114.1" cy="169.6" r=".4" fill="#fff" stroke="#000" stroke-width=".18"/>
<path d="M113.5 167h1.3" fill="none" stroke="#008000" stroke-width="1.3"/>
<circle cx="114.1" cy="167" r=".4" fill="#fff" stroke="#000" stroke-width=".18"/>
<path d="M113.5 164.5h1.3" fill="none" stroke="#008000" stroke-width="1.3"/>
<circle cx="114.1" cy="164.5" r=".4" fill="#fff" stroke="#000" stroke-width=".18"/>
<path d="M113.5 161.9h1.3" fill="none" stroke="#008000" stroke-width="1.3"/>
<circle cx="114.1" cy="161.9" r=".4" fill="#fff" stroke="#000" stroke-width=".18"/>
<path d="M113.5 159.4h1.3" fill="none" stroke="#008000" stroke-width="1.3"/>
<circle cx="114.1" cy="159.4" r=".4" fill="#fff" stroke="#000" stroke-width=".18"/>
<path d="M113.5 156.9h1.3" fill="none" stroke="#008000" stroke-width="1.3"/>
<circle cx="114.1" cy="156.9" r=".4" fill="#fff" stroke="#000" stroke-width=".18"/>
<path d="M113.5 154.3h1.3" fill="none" stroke="#008000" stroke-width="1.3"/>
<circle cx="114.1" cy="154.3" r=".4" fill="#fff" stroke="#000" stroke-width=".18"/>
<path d="M113.5 151.8h1.3" fill="none" stroke="#008000" stroke-width="1.3"/>
<circle cx="114.1" cy="151.8" r=".4" fill="#fff" stroke="#000" stroke-width=".18"/>
<path d="M117.3 151.8h1.3" fill="none" stroke="#008000" stroke-width="1.3"/>
<circle cx="117.9" cy="151.8" r=".4" fill="#fff" stroke="#000" stroke-width=".18"/>
<path d="M117.3 154.3h1.3" fill="none" stroke="#008000" stroke-width="1.3"/>
<circle cx="117.9" cy="154.3" r=".4" fill="#fff" stroke="#000" stroke-width=".18"/>
<path d="M117.3 167h1.3" fill="none" stroke="#008000" stroke-width="1.3"/>
<circle cx="117.9" cy="167" r=".4" fill="#fff" stroke="#000" stroke-width=".18"/>
<path d="M117.3 169.6h1.3" fill="none" stroke="#008000" stroke-width="1.3"/>
<circle cx="117.9" cy="169.6" r=".4" fill="#fff" stroke="#000" stroke-width=".18"/>
<path d="M117.3 156.9h1.3" fill="none" stroke="#008000" stroke-width="1.3"/>
<circle cx="117.9" cy="156.9" r=".4" fill="#fff" stroke="#000" stroke-width=".18"/>
<path d="M117.3 159.4h1.3" fill="none" stroke="#008000" stroke-width="1.3"/>
<circle cx="117.9" cy="159.4" r=".4" fill="#fff" stroke="#000" stroke-width=".18"/>
<path d="M117.3 164.5h1.3" fill="none" stroke="#008000" stroke-width="1.3"/>
<circle cx="117.9" cy="164.5" r=".4" fill="#fff" stroke="#000" stroke-width=".18"/>
<path d="M117.3 161.9h1.3" fill="none" stroke="#008000" stroke-width="1.3"/>
<circle cx="117.9" cy="161.9" r=".4" fill="#fff" stroke="#000" stroke-width=".18"/>
<path d="M124.9 169.6h1.3" fill="none" stroke="#008000" stroke-width="1.3"/>
<circle cx="125.6" cy="169.6" r=".4" fill="#fff" stroke="#000" stroke-width=".18"/>
<path d="M124.9 167h1.3" fill="none" stroke="#008000" stroke-width="1.3"/>
<circle cx="125.6" cy="167" r=".4" fill="#fff" stroke="#000" stroke-width=".18"/>
<path d="M124.9 164.5h1.3" fill="none" stroke="#008000" stroke-width="1.3"/>
<circle cx="125.6" cy="164.5" r=".4" fill="#fff" stroke="#000" stroke-width=".18"/>
<path d="M124.9 161.9h1.3" fill="none" stroke="#008000" stroke-width="1.3"/>
<circle cx="125.6" cy="161.9" r=".4" fill="#fff" stroke="#000" stroke-width=".18"/>
<path d="M124.9 159.4h1.3" fill="none" stroke="#008000" stroke-width="1.3"/>
<circle cx="125.6" cy="159.4" r=".4" fill="#fff" stroke="#000" stroke-width=".18"/>
<path d="M124.9 156.9h1.3" fill="none" stroke="#008000" stroke-width="1.3"/>
<circle cx="125.6" cy="156.9" r=".4" fill="#fff" stroke="#000" stroke-width=".18"/>
<path d="M124.9 154.3h1.3" fill="none" stroke="#008000" stroke-width="1.3"/>
<circle cx="125.6" cy="154.3" r=".4" fill="#fff" stroke="#000" stroke-width=".18"/>
<path d="M124.9 151.8h1.3" fill="none" stroke="#008000" stroke-width="1.3"/>
<circle cx="125.6" cy="151.8" r=".4" fill="#fff" stroke="#000" stroke-width=".18"/>
<path d="M129.3 151.8h1.4" fill="none" stroke="#008000" stroke-width="1.3"/>
<circle cx="130" cy="151.8" r=".4" fill="#fff" stroke="#000" stroke-width=".18"/>
<path d="M129.3 154.3h1.4" fill="none" stroke="#008000" stroke-width="1.3"/>
<circle cx="130" cy="154.3" r=".4" fill="#fff" stroke="#000" stroke-width=".18"/>
<path d="M129.3 167h1.4" fill="none" stroke="#008000" stroke-width="1.3"/>
<circle cx="130" cy="167" r=".4" fill="#fff" stroke="#000" stroke-width=".18"/>
<path d="M129.3 169.6h1.4" fill="none" stroke="#008000" stroke-width="1.3"/>
<circle cx="130" cy="169.6" r=".4" fill="#fff" stroke="#000" stroke-width=".18"/>
<path d="M129.3 156.9h1.4" fill="none" stroke="#008000" stroke-width="1.3"/>
<circle cx="130" cy="156.9" r=".4" fill="#fff" stroke="#000" stroke-width=".18"/>
<path d="M129.3 159.4h1.4" fill="none" stroke="#008000" stroke-width="1.3"/>
<circle cx="130" cy="159.4" r=".4" fill="#fff" stroke="#000" stroke-width=".18"/>
<path d="M129.3 164.5h1.4" fill="none" stroke="#008000" stroke-width="1.3"/>
<circle cx="130" cy="164.5" r=".4" fill="#fff" stroke="#000" stroke-width=".18"/>
<path d="M129.3 161.9h1.4" fill="none" stroke="#008000" stroke-width="1.3"/>
<circle cx="130" cy="161.9" r=".4" fill="#fff" stroke="#000" stroke-width=".18"/>
<path d="M136.9 169.6h1.4" fill="none" stroke="#008000" stroke-width="1.3"/>
<circle cx="137.6" cy="169.6" r=".4" fill="#fff" stroke="#000" stroke-width=".18"/>
<path d="M136.9 167h1.4" fill="none" stroke="#008000" stroke-width="1.3"/>
<circle cx="137.6" cy="167" r=".4" fill="#fff" stroke="#000" stroke-width=".18"/>
<path d="M136.9 164.5h1.4" fill="none" stroke="#008000" stroke-width="1.3"/>
<circle cx="137.6" cy="164.5" r=".4" fill="#fff" stroke="#000" stroke-width=".18"/>
<path d="M136.9 161.9h1.4" fill="none" stroke="#008000" stroke-width="1.3"/>
<circle cx="137.6" cy="161.9" r=".4" fill="#fff" stroke="#000" stroke-width=".18"/>
<path d="M136.9 159.4h1.4" fill="none" stroke="#008000" stroke-width="1.3"/>
<circle cx="137.6" cy="159.4" r=".4" fill="#fff" stroke="#000" stroke-width=".18"/>
<path d="M136.9 156.9h1.4" fill="none" stroke="#008000" stroke-width="1.3"/>
<circle cx="137.6" cy="156.9" r=".4" fill="#fff" stroke="#000" stroke-width=".18"/>
<path d="M136.9 154.3h1.4" fill="none" stroke="#008000" stroke-width="1.3"/>
<circle cx="137.6" cy="154.3" r=".4" fill="#fff" stroke="#000" stroke-width=".18"/>
<path d="M136.9 151.8h1.4" fill="none" stroke="#008000" stroke-width="1.3"/>
<circle cx="137.6" cy="151.8" r=".4" fill="#fff" stroke="#000" stroke-width=".18"/>
<circle cx="152.5" cy="144.2" r=".93" fill="#008000" stroke="#008000" stroke-width=".18"/>
<circle cx="152.5" cy="144.2" r=".51" fill="#fff" stroke="#000" stroke-width=".18"/>
<circle cx="152.5" cy="141.6" r=".93" fill="#008000" stroke="#008000" stroke-width=".18"/>
<circle cx="152.5" cy="141.6" r=".51" fill="#fff" stroke="#000" stroke-width=".18"/>
<circle cx="152.5" cy="139.1" r=".93" fill="#008000" stroke="#008000" stroke-width=".18"/>
<circle cx="152.5" cy="139.1" r=".51" fill="#fff" stroke="#000" stroke-width=".18"/>
<circle cx="152.5" cy="136.6" r=".93" fill="#008000" stroke="#008000" stroke-width=".18"/>
<circle cx="152.5" cy="136.6" r=".51" fill="#fff" stroke="#000" stroke-width=".18"/>
<circle cx="57.3" cy="144.2" r=".93" fill="#008000" stroke="#008000" stroke-width=".18"/>
<circle cx="57.3" cy="144.2" r=".51" fill="#fff" stroke="#000" stroke-width=".18"/>
<circle cx="57.3" cy="141.6" r=".93" fill="#008000" stroke="#008000" stroke-width=".18"/>
<circle cx="57.3" cy="141.6" r=".51" fill="#fff" stroke="#000" stroke-width=".18"/>
<circle cx="57.3" cy="139.1" r=".93" fill="#008000" stroke="#008000" stroke-width=".18"/>
<circle cx="57.3" cy="139.1" r=".51" fill="#fff" stroke="#000" stroke-width=".18"/>
<circle cx="57.3" cy="136.6" r=".93" fill="#008000" stroke="#008000" stroke-width=".18"/>
<circle cx="57.3" cy="136.6" r=".51" fill="#fff" stroke="#000" stroke-width=".18"/>
<circle cx="99.8" cy="158.8" r=".38" fill="#008000" stroke="#008000" stroke-width=".18"/>
<circle cx="99.8" cy="158.8" r=".17" fill="#fff" stroke="#000" stroke-width=".18"/>
<circle cx="112.5" cy="146.1" r=".38" fill="#008000" stroke="#008000" stroke-width=".18"/>
<circle cx="112.5" cy="146.1" r=".17" fill="#fff" stroke="#000" stroke-width=".18"/>
<circle cx="122.3" cy="161.9" r=".38" fill="#008000" stroke="#008000" stroke-width=".18"/>
<circle cx="122.3" cy="161.9" r=".17" fill="#fff" stroke="#000" stroke-width=".18"/>
<circle cx="127.8" cy="146.7" r=".38" fill="#008000" stroke="#008000" stroke-width=".18"/>
<circle cx="127.8" cy="146.7" r=".17" fill="#fff" stroke="#000" stroke-width=".18"/>
<g fill="#800000" stroke="#800000" stroke-width=".18">
<path d="M56.2 168.2a3.2 3.2 0 0 1 4.9 .9 3.2 3.2 0 0 1-2.1 4.5 3.2 3.2 0 0 1-3.9-3.1h2.5a.63 .63 0 0 1 .9-.6 .63 .63 0 0 1 .2 1.1 .63 .63 0 0 1-1-.4l-.1-.1h-2.5a3.1 3.1 0 0 1 1.1-2.3z" fill-rule="evenodd"/>
<path d="M149.5 168.2a3.2 3.2 0 0 1 4.9 .9 3.2 3.2 0 0 1-2.1 4.5 3.2 3.2 0 0 1-3.9-3.1h2.5a.64 .64 0 0 1 .9-.6 .64 .64 0 0 1 .2 1.1 .64 .64 0 0 1-1-.4l-.1-.1h-2.5a3.1 3.1 0 0 1 1.1-2.3z" fill-rule="evenodd"/>
<path d="M56.2 128.4a3.2 3.2 0 0 1 4.9 .9 3.2 3.2 0 0 1-2.1 4.6 3.2 3.2 0 0 1-3.9-3.1h2.5a.63 .63 0 0 1 .9-.6 .63 .63 0 0 1 .2 1 .63 .63 0 0 1-1-.3l-.1-.1h-2.5a3.2 3.2 0 0 1 1.1-2.4z" fill-rule="evenodd"/>
<path d="M149.5 128.4a3.2 3.2 0 0 1 4.9 .9 3.2 3.2 0 0 1-2.1 4.6 3.2 3.2 0 0 1-3.9-3.1h2.5a.64 .64 0 0 1 .9-.6 .64 .64 0 0 1 .2 1 .64 .64 0 0 1-1-.3l-.1-.1h-2.5a3.2 3.2 0 0 1 1.1-2.4z" fill-rule="evenodd"/>
</g>
<g fill="none" stroke="#505050" stroke-width=".18">
<path d="M59.2 136.8h91.4v5.9h-91.4v-1.9a1.02 1.02 0 0 0 1-1.1 1.02 1.02 0 0 0-1-1zM61.1 133.8h.4l.1 .2M64.5 128.3v.4l-.1 .1M64.8 128.4h.3l-.3 .4h.3M82.1 138.7a1.02 1.02 0 0 1 1 1 1.02 1.02 0 0 1-1 1.1M82.1 136.8v5.9M84.8 128.3v.4l-.1 .1M85.1 128.3l.3 .1-.2 .1M85.3 128.5l.1 .2-.3 .1M104.9 138.7a1.02 1.02 0 0 1 1.1 1 1.02 1.02 0 0 1-1.1 1.1M104.9 136.8v5.9M105.2 128.3v.4l-.2 .1"/>
<path d="M105.6 128.3l-.1 .4h.2M105.6 128.5v.3M125.5 128.3v.4l-.2 .1M126 128.3h-.2v.2l.2 .1v.2h-.2M127.8 138.7a1.02 1.02 0 0 1 1 1 1.02 1.02 0 0 1-1 1.1M127.8 136.8v5.9M144.9 133.8h.3l.2 .2M145 133.5h.1M145.1 133.2l-.1 .3M145.1 133.2l-.2 .1 .1 .2M145.1 133.2l.3 .3M55.4 145.2h.4l.1 .2"/>
<path d="M55.4 144.2a.22 .22 0 0 1 .3-.1 .22 .22 0 0 1 .1 .3h-.4zM55.5 144.1l.3 .3M55.9 144.7v.2M55.9 144.8h-.5l.1 .1M62 145.5h5.9v22.8h-1.9a1.02 1.02 0 0 0-1.1-1 1.02 1.02 0 0 0-1 1h-1.9zM72.2 150.5h1.9a1.02 1.02 0 0 0 1 1 1.02 1.02 0 0 0 1-1h1.9v20.3h-5.8zM83.9 150.5h1.9a1.02 1.02 0 0 0 1 1 1.02 1.02 0 0 0 1-1h1.9v20.3h-5.8zM96 150.5h1.9a1.02 1.02 0 0 0 1 1 1.02 1.02 0 0 0 1-1h1.9v20.3h-5.8zM107.4 150.5h1.9a1.02 1.02 0 0 0 1 1 1.02 1.02 0 0 0 1-1h1.9v20.3h-5.8zM118.8 150.5h1.9a1.02 1.02 0 0 0 1.1 1 1.02 1.02 0 0 0 1-1h1.9v20.3h-5.9zM130.9 150.5h1.9a1.02 1.02 0 0 0 1 1 1.02 1.02 0 0 0 1-1h1.9v20.3h-5.8zM142 145.5h1.9a1.02 1.02 0 0 0 1 1 1.02 1.02 0 0 0 1-1h1.9v22.8h-5.8z"/>
<path d="M150.6 145.2h.4l.1 .2M151.1 144.8l-.5-.1v.2M55.4 166.2h.4l.1 .1M55.9 165.6v.3M55.9 165.7h-.5l.1 .2M150.6 166.2h.4l.1 .1M150.6 165.7l.2 .2M150.9 165.6l-.1 .3M150.9 165.6h.1M150.9 165.6l.2 .2-.3 .1"/>
<circle cx="58.3" cy="130.8" r="2.86"/>
<circle cx="61.2" cy="133.4" r=".11"/>
<circle cx="61.4" cy="133.4" r=".14"/>
<circle cx="151.6" cy="130.8" r="2.86"/>
<circle cx="58.3" cy="170.5" r="2.86"/>
<circle cx="151.6" cy="170.5" r="2.86"/>
</g>
<g fill="none" stroke="#505050" stroke-width=".21">
<path d="M56.7 135.3h1.3l.6 .6v1.3l-.6 .6 .6 .7v1.2l-.6 .7 .6 .6v1.3l-.6 .6 .6 .7v1.2l-.6 .7h-1.3l-.7-.7v-1.2l.7-.7-.7-.6v-1.3l.7-.6-.7-.7v-1.2l.7-.7-.7-.6v-1.3zM64.3 130.9l.6 .6h1.3l.6-.6 .7 .6h1.2l.7-.6 .6 .6h1.3l.6-.6 .7 .6h1.2l.7-.6 .6 .6h1.3l.6-.6 .6 .6h1.3l.6-.6 .7 .6h1.2l.7-.6 .6 .6h1.3l.6-.6M64.3 129.6l.6-.6h1.3l.6 .6 .7-.6h1.2l.7 .6 .6-.6h1.3l.6 .6 .7-.6h1.2l.7 .6 .6-.6h1.3l.6 .6 .6-.6h1.3l.6 .6 .7-.6h1.2l.7 .6 .6-.6h1.3l.6 .6M64.3 129.6l-.6-.6h-1.3l-.6 .6v1.3l.6 .6-.6 .6v1.3l.6 .6h1.3l.6-.6v-1.3l-.6-.6 .6-.6M64.3 129.6v1.3M84.6 129.6l.6-.6h1.3l.6 .6 .7-.6h1.2l.7 .6 .6-.6h1.3l.6 .6 .7-.6h1.2l.7 .6 .6-.6h1.3l.6 .6 .6-.6h1.3l.6 .6 .7-.6h1.2l.7 .6 .6-.6h1.3l.6 .6M84.6 130.9l.6 .6h1.3l.6-.6 .7 .6h1.2l.7-.6 .6 .6h1.3l.6-.6 .7 .6h1.2l.7-.6 .6 .6h1.3l.6-.6 .6 .6h1.3l.6-.6 .7 .6h1.2l.7-.6 .6 .6h1.3l.6-.6M84.6 129.6v1.3M104.9 129.6l.7-.6h1.2l.7 .6 .6-.6h1.3l.6 .6 .6-.6h1.3l.6 .6 .7-.6h1.2l.7 .6 .6-.6h1.3l.6 .6 .7-.6h1.2l.7 .6 .6-.6h1.3l.6 .6 .6-.6h1.3l.6 .6M104.9 130.9l.7 .6h1.2l.7-.6 .6 .6h1.3l.6-.6 .6 .6h1.3l.6-.6 .7 .6h1.2l.7-.6 .6 .6h1.3l.6-.6 .7 .6h1.2l.7-.6 .6 .6h1.3l.6-.6 .6 .6h1.3l.6-.6M104.9 129.6v1.3M125.2 129.6l.7-.6h1.2l.7 .6 .6-.6h1.3l.6 .6 .7-.6h1.2l.7 .6 .6-.6h1.3l.6 .6 .6-.6h1.3l.6 .6 .7-.6h1.2l.7 .6 .6-.6h1.3l.6 .6 .6-.6h1.3l.6 .6"/>
<path d="M125.2 130.9l.7 .6h1.2l.7-.6 .6 .6h1.3l.6-.6 .7 .6h1.2l.7-.6 .6 .6h1.3l.6-.6 .6 .6h1.3l.6-.6 .7 .6h1.2l.7-.6 .6 .6h1.3l.6-.6 .6 .6h1.3l.6-.6M125.2 129.6v1.3M145.5 129.6l.7-.6h1.2l.7 .6v1.3l-.7 .6 .7 .6v1.3l-.7 .6h-1.2l-.7-.6v-1.3l.7-.6-.7-.6M145.5 129.6v1.3M151.9 135.3h1.3l.6 .6v1.3l-.6 .6 .6 .7v1.2l-.6 .7 .6 .6v1.3l-.6 .6 .6 .7v1.2l-.6 .7h-1.3l-.6-.7v-1.2l.6-.7-.6-.6v-1.3l.6-.6-.6-.7v-1.2l.6-.7-.6-.6v-1.3zM56.7 146.1h1.3l.6 .6v1.3l-.6 .6 .6 .7v1.2l-.6 .7 .6 .6v1.3l-.6 .6 .6 .6v1.3l-.6 .7 .6 .6v1.3l-.6 .6 .6 .6v1.3l-.6 .6 .6 .6v1.3l-.6 .7 .6 .6v1.3l-.6 .6h-1.3l-.7-.6v-1.3l.7-.6-.7-.7v-1.3l.7-.6-.7-.6v-1.3l.7-.6-.7-.6v-1.3l.7-.6-.7-.7v-1.3l.7-.6-.7-.6v-1.3l.7-.6-.7-.7v-1.2l.7-.7-.7-.6v-1.3zM151.3 146.7l.6-.6h1.3l.6 .6v1.3l-.6 .6 .6 .7v1.2l-.6 .7 .6 .6v1.3l-.6 .6 .6 .6v1.3l-.6 .7 .6 .6v1.3l-.6 .6 .6 .6v1.3l-.6 .6 .6 .6v1.3l-.6 .7 .6 .6v1.3l-.6 .6h-1.3l-.6-.6v-1.3l.6-.6-.6-.7v-1.3l.6-.6-.6-.6v-1.3l.6-.6-.6-.6v-1.3l.6-.6-.6-.7v-1.3l.6-.6-.6-.6v-1.3l.6-.6-.6-.7v-1.2l.6-.7-.6-.6z"/>
</g>
<g fill="#505050" stroke="#505050" stroke-width=".18">
<path d="M57.1 149.6h.5v.6h-.5z"/>
<path d="M57.1 152.2h.5v.5h-.5z"/>
<path d="M57.1 154.7h.5v.5h-.5z"/>
<path d="M57.1 157.3h.5v.5h-.5z"/>
<path d="M57.1 159.8h.5v.5h-.5z"/>
<path d="M57.1 162.3h.5v.5h-.5z"/>
<path d="M57.1 164.9h.5v.5h-.5z"/>
<path d="M57.1 147.1h.5v.5h-.5z"/>
<path d="M80.6 130h.5v.5h-.5z"/>
<path d="M78 130h.5v.5h-.5z"/>
<path d="M75.5 130h.5v.5h-.5z"/>
<path d="M72.9 130h.5v.5h-.5z"/>
<path d="M70.4 130h.5v.5h-.5z"/>
<path d="M67.9 130h.5v.5h-.5z"/>
<path d="M65.3 130h.5v.5h-.5z"/>
<path d="M83.1 130h.5v.5h-.5z"/>
<path d="M100.9 130h.5v.5h-.5z"/>
<path d="M98.3 130h.5v.5h-.5z"/>
<path d="M95.8 130h.5v.5h-.5z"/>
<path d="M93.2 130h.5v.5h-.5z"/>
<path d="M90.7 130h.5v.5h-.5z"/>
<path d="M88.2 130h.5v.5h-.5z"/>
<path d="M85.6 130h.5v.5h-.5z"/>
<path d="M103.4 130h.5v.5h-.5z"/>
<path d="M121.2 130h.5v.5h-.5z"/>
<path d="M118.6 130h.5v.5h-.5z"/>
<path d="M116.1 130h.5v.5h-.5z"/>
<path d="M113.6 130h.5v.5h-.5z"/>
<path d="M111 130h.5v.5h-.5z"/>
<path d="M108.5 130h.5v.5h-.5z"/>
<path d="M105.9 130h.5v.5h-.5z"/>
<path d="M123.7 130h.5v.5h-.5z"/>
<path d="M141.5 130h.5v.5h-.5z"/>
<path d="M139 130h.5v.5h-.5z"/>
<path d="M136.4 130h.5v.5h-.5z"/>
<path d="M133.9 130h.5v.5h-.5z"/>
<path d="M131.3 130h.5v.5h-.5z"/>
<path d="M128.8 130h.5v.5h-.5z"/>
<path d="M126.3 130h.5v.5h-.5z"/>
<path d="M144 130h.5v.5h-.5z"/>
<path d="M152.3 149.6h.5v.6h-.5z"/>
<path d="M152.3 152.2h.5v.5h-.5z"/>
<path d="M152.3 154.7h.5v.5h-.5z"/>
<path d="M152.3 157.3h.5v.5h-.5z"/>
<path d="M152.3 159.8h.5v.5h-.5z"/>
<path d="M152.3 162.3h.5v.5h-.5z"/>
<path d="M152.3 164.9h.5v.5h-.5z"/>
<path d="M152.3 147.1h.5v.5h-.5z"/>
<path d="M62.8 130h.5v.5h-.5z"/>
<path d="M62.8 132.5h.5v.5h-.5z"/>
<path d="M146.6 130h.5v.5h-.5z"/>
<path d="M146.6 132.5h.5v.5h-.5z"/>
<path d="M152.3 136.3h.5v.5h-.5z"/>
<path d="M152.3 138.9h.5v.5h-.5z"/>
<path d="M152.3 141.4h.5v.5h-.5z"/>
<path d="M152.3 143.9h.5v.5h-.5z"/>
<path d="M57.1 136.3h.5v.5h-.5z"/>
<path d="M57.1 138.9h.5v.5h-.5z"/>
<path d="M57.1 141.4h.5v.5h-.5z"/>
<path d="M57.1 143.9h.5v.5h-.5z"/>
</g>
<g fill="none" stroke="#000" stroke-width=".18">
<path d="M62 132.8h2.1M63 131.8v2M64.6 130.2h2M65.6 129.2v2.1M69.6 139.7h2.1M70.7 138.7v2.1M84.9 130.2h2M85.9 129.2v2.1M92.5 139.7h2M93.5 138.7v2.1M105.2 130.2h2M106.2 129.2v2.1"/>
<path d="M115.3 139.7h2.1M116.4 138.7v2.1M125.5 130.2h2M126.5 129.2v2.1M138.2 139.7h2M139.2 138.7v2.1M145.8 132.8h2M146.8 131.8v2M56.3 144.2h2M57.3 143.2v2M63.9 156.9h2.1M64.9 155.9v2"/>
<path d="M75.1 159.7v2M86.8 159.7v2M98.9 159.7v2M110.3 159.7v2M121.8 159.7v2M133.8 159.7v2M143.9 156.9h2M144.9 155.9v2M151.5 144.2h2M152.5 143.2v2M56.3 165.1h2M57.3 164.1v2"/>
<path d="M74.1 160.7h2M85.8 160.7h2M97.9 160.7h2M109.3 160.7h2M120.7 160.7h2.1M132.8 160.7h2M151.5 165.1h2M152.5 164.1v2"/>
</g>
<g fill="none" stroke="#f90" stroke-width=".18">
<path d="M55.9 128.8l.3-.3a2.12 2.12 0 0 1 1.5-.5h94.4a2.26 2.26 0 0 1 2.3 2.2v40.9a2.29 2.29 0 0 1-2.3 2.3h-94.1a2.54 2.54 0 0 1-2.6-2.6v-40.6l.2-.7z"/>
<circle cx="58.3" cy="170.5" r="1.5"/>
</g>
<circle cx="58.3" cy="170.5" r="1.5" fill="#fff" stroke="#000" stroke-width=".18"/>
<circle cx="58.3" cy="130.8" r="1.5" fill="none" stroke="#f90" stroke-width=".18"/>
<circle cx="58.3" cy="130.8" r="1.5" fill="#fff" stroke="#000" stroke-width=".18"/>
<circle cx="151.6" cy="130.8" r="1.5" fill="none" stroke="#f90" stroke-width=".18"/>
<circle cx="151.6" cy="130.8" r="1.5" fill="#fff" stroke="#000" stroke-width=".18"/>
<circle cx="151.6" cy="170.5" r="1.5" fill="none" stroke="#f90" stroke-width=".18"/>
<circle cx="151.6" cy="170.5" r="1.5" fill="#fff" stroke="#000" stroke-width=".18"/>
<g fill="none" stroke="#505050" stroke-width=".18">
<path d="M58.3 138.1l-2 2M58.3 135.6l-2 2M59.3 129.8l-2 2M61.5 134.9l-2 2M64.1 131.8l-2.1 2M64.1 129.2l-2.1 2.1M64.1 134.9l-2.1 2M66.6 129.2l-2 2.1M66.6 134.9l-2 2M69.1 129.2l-2 2.1M69.1 134.9l-2 2M71.7 129.2l-2.1 2.1"/>
<path d="M71.7 134.9l-2.1 2M74.2 129.2l-2 2.1M74.2 134.9l-2 2M76.8 129.2l-2.1 2.1M76.8 134.9l-2.1 2M79.3 129.2l-2 2.1M79.3 134.9l-2 2M81.8 129.2l-2 2.1M81.8 134.9l-2 2M84.3 129.2l-2 2.1M84.3 134.9l-2 2M86.9 129.2l-2 2.1"/>
<path d="M86.9 134.9l-2 2M89.4 129.2l-2 2.1M89.4 134.9l-2 2M92 129.2l-2.1 2.1M92 134.9l-2.1 2M94.5 129.2l-2 2.1M94.5 134.9l-2 2M97 129.2l-2 2.1M97 134.9l-2 2M99.6 129.2l-2 2.1M99.6 134.9l-2 2M102.1 129.2l-2 2.1"/>
<path d="M102.1 134.9l-2 2M104.7 129.2l-2.1 2.1M104.7 134.9l-2.1 2M107.2 129.2l-2 2.1M107.2 134.9l-2 2M109.7 129.2l-2 2.1M109.7 134.9l-2 2M112.3 129.2l-2 2.1M112.3 134.9l-2 2M114.8 129.2l-2 2.1M114.8 134.9l-2 2M117.4 129.2l-2.1 2.1"/>
<path d="M117.4 134.9l-2.1 2M119.9 129.2l-2 2.1M119.9 134.9l-2 2M122.4 129.2l-2 2.1M122.4 134.9l-2 2M125 129.2l-2 2.1M125 134.9l-2 2M127.5 129.2l-2 2.1M127.5 134.9l-2 2M130.1 129.2l-2.1 2.1M130.1 134.9l-2.1 2M132.6 129.2l-2 2.1"/>
<path d="M132.6 134.9l-2 2M135.1 129.2l-2 2.1M135.1 134.9l-2 2M137.7 129.2l-2 2.1M137.7 134.9l-2 2M140.2 129.2l-2 2.1M140.2 134.9l-2 2M142.7 129.2l-2 2.1M142.7 134.9l-2 2M145.3 129.2l-2 2.1M145.3 134.9l-2 2M147.8 131.8l-2 2"/>
<path d="M147.8 129.2l-2 2.1M147.8 134.9l-2 2M150.4 134.9l-2.1 2M152.6 129.8l-2 2M153.5 138.1l-2 2M153.5 135.6l-2 2M58.3 159l-2 2.1M58.3 156.5l-2 2M58.3 154l-2 2M58.3 151.4l-2 2.1M58.3 148.9l-2 2M58.3 146.3l-2 2.1"/>
<path d="M58.3 140.6l-2 2.1M58.3 143.2l-2 2M61.5 142.5l-2 2.1M62.1 155.9l-2 2M62.1 153.3l-2 2.1M62.1 145.7l-2 2M62.1 148.3l-2 2M62.1 150.8l-2 2M62.1 158.4l-2 2M64.1 142.5l-2.1 2.1M66.6 142.5l-2 2.1M69.1 142.5l-2 2.1"/>
<path d="M69.8 150.8l-2.1 2M69.8 148.3l-2.1 2M69.8 158.4l-2.1 2M69.8 153.3l-2.1 2.1M69.8 155.9l-2.1 2M69.8 145.7l-2.1 2M71.7 142.5l-2.1 2.1M72.3 150.8l-2 2M72.3 155.9l-2 2M72.3 153.3l-2 2.1M72.3 158.4l-2 2M74.2 142.5l-2 2.1"/>
<path d="M76.8 142.5l-2.1 2.1M79.3 142.5l-2 2.1M79.9 155.9l-2 2M79.9 150.8l-2 2M79.9 158.4l-2 2M79.9 153.3l-2 2.1M81.8 142.5l-2 2.1M84 150.8l-2 2M84 153.3l-2 2.1M84 155.9l-2 2M84 158.4l-2 2M84.3 142.5l-2 2.1"/>
<path d="M86.9 142.5l-2 2.1M89.4 142.5l-2 2.1M91.7 150.8l-2.1 2M91.7 158.4l-2.1 2M91.7 155.9l-2.1 2M91.7 153.3l-2.1 2.1M92 142.5l-2.1 2.1M94.5 142.5l-2 2.1M96.1 150.8l-2 2M96.1 153.3l-2 2.1M96.1 155.9l-2 2M96.1 158.4l-2 2"/>
<path d="M97 142.5l-2 2.1M98.8 158.8l1-1 1.1 1-1.1 1zM99.6 142.5l-2 2.1M99.8 157.8v1M102.1 142.5l-2 2.1M103.7 155.9l-2 2M103.7 153.3l-2 2.1M103.7 158.4l-2 2M103.7 150.8l-2 2M104.7 142.5l-2.1 2.1M107.2 142.5l-2 2.1M107.5 150.8l-2 2"/>
<path d="M107.5 153.3l-2 2.1M107.5 155.9l-2 2M107.5 158.4l-2 2M109.7 142.5l-2 2.1M111.5 146.1l1-1 1.1 1-1.1 1zM112.3 142.5l-2 2.1M112.5 145.1v1M114.8 142.5l-2 2.1M115.1 153.3l-2 2.1M115.1 158.4l-2 2M115.1 155.9l-2 2M115.1 150.8l-2 2"/>
<path d="M117.4 142.5l-2.1 2.1M119 153.3l-2.1 2.1M119 150.8l-2.1 2M119 155.9l-2.1 2M119 158.4l-2.1 2M119.9 142.5l-2 2.1M122.4 142.5l-2 2.1M125 142.5l-2 2.1M126.6 153.3l-2.1 2.1M126.6 158.4l-2.1 2M126.6 155.9l-2.1 2M126.6 150.8l-2.1 2"/>
<path d="M127.5 142.5l-2 2.1M127.8 145.7v1M127.8 145.7l1 1-1 1-1-1zM130.1 142.5l-2.1 2.1M131 150.8l-2 2M131 153.3l-2 2.1M131 155.9l-2 2M131 158.4l-2 2M132.6 142.5l-2 2.1M135.1 142.5l-2 2.1M137.7 142.5l-2 2.1M138.6 153.3l-2 2.1"/>
<path d="M138.6 158.4l-2 2M138.6 155.9l-2 2M138.6 150.8l-2 2M140.2 142.5l-2 2.1M142.1 145.7l-2 2M142.1 148.3l-2 2M142.1 150.8l-2 2M142.1 153.3l-2 2.1M142.1 158.4l-2 2M142.1 155.9l-2 2M142.7 142.5l-2 2.1M145.3 142.5l-2 2.1"/>
<path d="M147.8 142.5l-2 2.1M149.7 158.4l-2 2M149.7 155.9l-2 2M149.7 153.3l-2 2.1M149.7 150.8l-2 2M149.7 148.3l-2 2M149.7 145.7l-2 2M150.4 142.5l-2.1 2.1M153.5 159l-2 2.1M153.5 156.5l-2 2M153.5 154l-2 2M153.5 151.4l-2 2.1"/>
<path d="M153.5 148.9l-2 2M153.5 146.3l-2 2.1M153.5 143.2l-2 2M153.5 140.6l-2 2.1M58.3 164.1l-2 2M58.3 161.6l-2 2M59.3 169.5l-2 2M62.1 160.9l-2 2.1M62.1 163.5l-2 2M62.1 166l-2 2M69.8 166l-2.1 2M69.8 163.5l-2.1 2"/>
<path d="M69.8 160.9l-2.1 2.1M72.3 163.5l-2 2M72.3 160.9l-2 2.1M72.3 166l-2 2M72.3 168.6l-2 2M79.9 160.9l-2 2.1M79.9 168.6l-2 2M79.9 166l-2 2M79.9 163.5l-2 2M84 166l-2 2M84 168.6l-2 2M84 163.5l-2 2"/>
<path d="M84 160.9l-2 2.1M91.7 168.6l-2.1 2M91.7 166l-2.1 2M91.7 163.5l-2.1 2M91.7 160.9l-2.1 2.1M96.1 166l-2 2M96.1 168.6l-2 2M96.1 163.5l-2 2M96.1 160.9l-2 2.1M103.7 160.9l-2 2.1M103.7 168.6l-2 2M103.7 166l-2 2"/>
<path d="M103.7 163.5l-2 2M107.5 166l-2 2M107.5 168.6l-2 2M107.5 163.5l-2 2M107.5 160.9l-2 2.1M115.1 160.9l-2 2.1M115.1 168.6l-2 2M115.1 166l-2 2M115.1 163.5l-2 2M119 166l-2.1 2M119 168.6l-2.1 2M119 163.5l-2.1 2"/>
<path d="M119 160.9l-2.1 2.1M122.3 160.9l1 1-1 1.1-1-1.1zM122.3 160.9v1M126.6 160.9l-2.1 2.1M126.6 168.6l-2.1 2M126.6 166l-2.1 2M126.6 163.5l-2.1 2M131 166l-2 2M131 168.6l-2 2M131 163.5l-2 2M131 160.9l-2 2.1M138.6 160.9l-2 2.1"/>
<path d="M138.6 168.6l-2 2M138.6 166l-2 2M138.6 163.5l-2 2M142.1 160.9l-2 2.1M142.1 163.5l-2 2M142.1 166l-2 2M149.7 166l-2 2M149.7 163.5l-2 2M149.7 160.9l-2 2.1M152.6 169.5l-2 2M153.5 164.1l-2 2M153.5 161.6l-2 2"/>
<circle cx="57.3" cy="136.6" r=".99"/>
<circle cx="57.3" cy="139.1" r=".99"/>
<circle cx="58.3" cy="130.8" r=".99"/>
<circle cx="60.5" cy="135.9" r=".99"/>
<circle cx="63" cy="132.8" r=".99"/>
<circle cx="63" cy="130.2" r=".99"/>
<circle cx="63" cy="135.9" r=".99"/>
<circle cx="65.6" cy="135.9" r=".99"/>
<circle cx="65.6" cy="130.2" r=".99"/>
<circle cx="68.1" cy="130.2" r=".99"/>
<circle cx="68.1" cy="135.9" r=".99"/>
<circle cx="70.7" cy="130.2" r=".99"/>
<circle cx="70.7" cy="135.9" r=".99"/>
<circle cx="73.2" cy="130.2" r=".99"/>
<circle cx="73.2" cy="135.9" r=".99"/>
<circle cx="75.7" cy="130.2" r=".99"/>
<circle cx="75.7" cy="135.9" r=".99"/>
<circle cx="78.3" cy="135.9" r=".99"/>
<circle cx="78.3" cy="130.2" r=".99"/>
<circle cx="80.8" cy="135.9" r=".99"/>
<circle cx="80.8" cy="130.2" r=".99"/>
<circle cx="83.4" cy="130.2" r=".99"/>
<circle cx="83.4" cy="135.9" r=".99"/>
<circle cx="85.9" cy="135.9" r=".99"/>
<circle cx="85.9" cy="130.2" r=".99"/>
<circle cx="88.4" cy="130.2" r=".99"/>
<circle cx="88.4" cy="135.9" r=".99"/>
<circle cx="91" cy="135.9" r=".99"/>
<circle cx="91" cy="130.2" r=".99"/>
<circle cx="93.5" cy="135.9" r=".99"/>
<circle cx="93.5" cy="130.2" r=".99"/>
<circle cx="96" cy="130.2" r=".99"/>
<circle cx="96" cy="135.9" r=".99"/>
<circle cx="98.6" cy="130.2" r=".99"/>
<circle cx="98.6" cy="135.9" r=".99"/>
<circle cx="101.1" cy="130.2" r=".99"/>
<circle cx="101.1" cy="135.9" r=".99"/>
<circle cx="103.7" cy="135.9" r=".99"/>
<circle cx="103.7" cy="130.2" r=".99"/>
<circle cx="106.2" cy="130.2" r=".99"/>
<circle cx="106.2" cy="135.9" r=".99"/>
<circle cx="108.7" cy="130.2" r=".99"/>
<circle cx="108.7" cy="135.9" r=".99"/>
<circle cx="111.3" cy="130.2" r=".99"/>
<circle cx="111.3" cy="135.9" r=".99"/>
<circle cx="113.8" cy="135.9" r=".99"/>
<circle cx="113.8" cy="130.2" r=".99"/>
<circle cx="116.4" cy="130.2" r=".99"/>
<circle cx="116.4" cy="135.9" r=".99"/>
<circle cx="118.9" cy="130.2" r=".99"/>
<circle cx="118.9" cy="135.9" r=".99"/>
<circle cx="121.4" cy="130.2" r=".99"/>
<circle cx="121.4" cy="135.9" r=".99"/>
<circle cx="124" cy="130.2" r=".99"/>
<circle cx="124" cy="135.9" r=".99"/>
<circle cx="126.5" cy="130.2" r=".99"/>
<circle cx="126.5" cy="135.9" r=".99"/>
<circle cx="129.1" cy="130.2" r=".99"/>
<circle cx="129.1" cy="135.9" r=".99"/>
<circle cx="131.6" cy="135.9" r=".99"/>
<circle cx="131.6" cy="130.2" r=".99"/>
<circle cx="134.1" cy="130.2" r=".99"/>
<circle cx="134.1" cy="135.9" r=".99"/>
<circle cx="136.7" cy="130.2" r=".99"/>
<circle cx="136.7" cy="135.9" r=".99"/>
<circle cx="139.2" cy="130.2" r=".99"/>
<circle cx="139.2" cy="135.9" r=".99"/>
<circle cx="141.7" cy="135.9" r=".99"/>
<circle cx="141.7" cy="130.2" r=".99"/>
<circle cx="144.3" cy="130.2" r=".99"/>
<circle cx="144.3" cy="135.9" r=".99"/>
<circle cx="146.8" cy="132.8" r=".99"/>
<circle cx="146.8" cy="135.9" r=".99"/>
<circle cx="146.8" cy="130.2" r=".99"/>
<circle cx="149.4" cy="135.9" r=".99"/>
<circle cx="151.6" cy="130.8" r=".99"/>
<circle cx="152.5" cy="136.6" r=".99"/>
<circle cx="152.5" cy="139.1" r=".99"/>
<circle cx="57.3" cy="147.4" r=".99"/>
<circle cx="57.3" cy="141.6" r=".99"/>
<circle cx="57.3" cy="155" r=".99"/>
<circle cx="57.3" cy="157.5" r=".99"/>
<circle cx="57.3" cy="152.4" r=".99"/>
<circle cx="57.3" cy="149.9" r=".99"/>
<circle cx="57.3" cy="144.2" r=".99"/>
<circle cx="60.5" cy="143.6" r=".99"/>
<circle cx="61.1" cy="149.3" r=".99"/>
<circle cx="61.1" cy="151.8" r=".99"/>
<circle cx="61.1" cy="156.9" r=".99"/>
<circle cx="61.1" cy="146.7" r=".99"/>
<circle cx="61.1" cy="154.3" r=".99"/>
<circle cx="61.1" cy="159.4" r=".99"/>
<circle cx="63" cy="143.6" r=".99"/>
<circle cx="65.6" cy="143.6" r=".99"/>
<circle cx="68.1" cy="143.6" r=".99"/>
<circle cx="68.7" cy="151.8" r=".99"/>
<circle cx="68.7" cy="149.3" r=".99"/>
<circle cx="68.7" cy="156.9" r=".99"/>
<circle cx="68.7" cy="159.4" r=".99"/>
<circle cx="68.7" cy="154.3" r=".99"/>
<circle cx="68.7" cy="146.7" r=".99"/>
<circle cx="70.7" cy="143.6" r=".99"/>
<circle cx="71.3" cy="151.8" r=".99"/>
<circle cx="71.3" cy="154.3" r=".99"/>
<circle cx="71.3" cy="156.9" r=".99"/>
<circle cx="71.3" cy="159.4" r=".99"/>
<circle cx="73.2" cy="143.6" r=".99"/>
<circle cx="75.7" cy="143.6" r=".99"/>
<circle cx="78.3" cy="143.6" r=".99"/>
<circle cx="78.9" cy="151.8" r=".99"/>
<circle cx="78.9" cy="159.4" r=".99"/>
<circle cx="78.9" cy="156.9" r=".99"/>
<circle cx="78.9" cy="154.3" r=".99"/>
<circle cx="80.8" cy="143.6" r=".99"/>
<circle cx="83" cy="151.8" r=".99"/>
<circle cx="83" cy="156.9" r=".99"/>
<circle cx="83" cy="154.3" r=".99"/>
<circle cx="83" cy="159.4" r=".99"/>
<circle cx="83.4" cy="143.6" r=".99"/>
<circle cx="85.9" cy="143.6" r=".99"/>
<circle cx="88.4" cy="143.6" r=".99"/>
<circle cx="90.6" cy="156.9" r=".99"/>
<circle cx="90.6" cy="151.8" r=".99"/>
<circle cx="90.6" cy="159.4" r=".99"/>
<circle cx="90.6" cy="154.3" r=".99"/>
<circle cx="91" cy="143.6" r=".99"/>
<circle cx="93.5" cy="143.6" r=".99"/>
<circle cx="95.1" cy="151.8" r=".99"/>
<circle cx="95.1" cy="156.9" r=".99"/>
<circle cx="95.1" cy="159.4" r=".99"/>
<circle cx="95.1" cy="154.3" r=".99"/>
<circle cx="96" cy="143.6" r=".99"/>
<circle cx="98.6" cy="143.6" r=".99"/>
<circle cx="101.1" cy="143.6" r=".99"/>
<circle cx="102.7" cy="154.3" r=".99"/>
<circle cx="102.7" cy="151.8" r=".99"/>
<circle cx="102.7" cy="156.9" r=".99"/>
<circle cx="102.7" cy="159.4" r=".99"/>
<circle cx="103.7" cy="143.6" r=".99"/>
<circle cx="106.2" cy="143.6" r=".99"/>
<circle cx="106.5" cy="151.8" r=".99"/>
<circle cx="106.5" cy="156.9" r=".99"/>
<circle cx="106.5" cy="154.3" r=".99"/>
<circle cx="106.5" cy="159.4" r=".99"/>
<circle cx="108.7" cy="143.6" r=".99"/>
<circle cx="111.3" cy="143.6" r=".99"/>
<circle cx="113.8" cy="143.6" r=".99"/>
<circle cx="114.1" cy="156.9" r=".99"/>
<circle cx="114.1" cy="154.3" r=".99"/>
<circle cx="114.1" cy="151.8" r=".99"/>
<circle cx="114.1" cy="159.4" r=".99"/>
<circle cx="116.4" cy="143.6" r=".99"/>
<circle cx="117.9" cy="151.8" r=".99"/>
<circle cx="117.9" cy="156.9" r=".99"/>
<circle cx="117.9" cy="159.4" r=".99"/>
<circle cx="117.9" cy="154.3" r=".99"/>
<circle cx="118.9" cy="143.6" r=".99"/>
<circle cx="121.4" cy="143.6" r=".99"/>
<circle cx="124" cy="143.6" r=".99"/>
<circle cx="125.6" cy="159.4" r=".99"/>
<circle cx="125.6" cy="151.8" r=".99"/>
<circle cx="125.6" cy="154.3" r=".99"/>
<circle cx="125.6" cy="156.9" r=".99"/>
<circle cx="126.5" cy="143.6" r=".99"/>
<circle cx="129.1" cy="143.6" r=".99"/>
<circle cx="130" cy="151.8" r=".99"/>
<circle cx="130" cy="154.3" r=".99"/>
<circle cx="130" cy="156.9" r=".99"/>
<circle cx="130" cy="159.4" r=".99"/>
<circle cx="131.6" cy="143.6" r=".99"/>
<circle cx="134.1" cy="143.6" r=".99"/>
<circle cx="136.7" cy="143.6" r=".99"/>
<circle cx="137.6" cy="156.9" r=".99"/>
<circle cx="137.6" cy="159.4" r=".99"/>
<circle cx="137.6" cy="154.3" r=".99"/>
<circle cx="137.6" cy="151.8" r=".99"/>
<circle cx="139.2" cy="143.6" r=".99"/>
<circle cx="141.1" cy="149.3" r=".99"/>
<circle cx="141.1" cy="154.3" r=".99"/>
<circle cx="141.1" cy="146.7" r=".99"/>
<circle cx="141.1" cy="151.8" r=".99"/>
<circle cx="141.1" cy="159.4" r=".99"/>
<circle cx="141.1" cy="156.9" r=".99"/>
<circle cx="141.7" cy="143.6" r=".99"/>
<circle cx="144.3" cy="143.6" r=".99"/>
<circle cx="146.8" cy="143.6" r=".99"/>
<circle cx="148.7" cy="154.3" r=".99"/>
<circle cx="148.7" cy="149.3" r=".99"/>
<circle cx="148.7" cy="146.7" r=".99"/>
<circle cx="148.7" cy="159.4" r=".99"/>
<circle cx="148.7" cy="156.9" r=".99"/>
<circle cx="148.7" cy="151.8" r=".99"/>
<circle cx="149.4" cy="143.6" r=".99"/>
<circle cx="152.5" cy="157.5" r=".99"/>
<circle cx="152.5" cy="152.4" r=".99"/>
<circle cx="152.5" cy="149.9" r=".99"/>
<circle cx="152.5" cy="147.4" r=".99"/>
<circle cx="152.5" cy="144.2" r=".99"/>
<circle cx="152.5" cy="141.6" r=".99"/>
<circle cx="152.5" cy="155" r=".99"/>
<circle cx="57.3" cy="165.1" r=".99"/>
<circle cx="57.3" cy="160" r=".99"/>
<circle cx="57.3" cy="162.6" r=".99"/>
<circle cx="58.3" cy="170.5" r=".99"/>
<circle cx="61.1" cy="164.5" r=".99"/>
<circle cx="61.1" cy="161.9" r=".99"/>
<circle cx="61.1" cy="167" r=".99"/>
<circle cx="68.7" cy="167" r=".99"/>
<circle cx="68.7" cy="161.9" r=".99"/>
<circle cx="68.7" cy="164.5" r=".99"/>
<circle cx="71.3" cy="167" r=".99"/>
<circle cx="71.3" cy="169.6" r=".99"/>
<circle cx="71.3" cy="164.5" r=".99"/>
<circle cx="71.3" cy="161.9" r=".99"/>
<circle cx="78.9" cy="169.6" r=".99"/>
<circle cx="78.9" cy="167" r=".99"/>
<circle cx="78.9" cy="164.5" r=".99"/>
<circle cx="78.9" cy="161.9" r=".99"/>
<circle cx="83" cy="161.9" r=".99"/>
<circle cx="83" cy="169.6" r=".99"/>
<circle cx="83" cy="167" r=".99"/>
<circle cx="83" cy="164.5" r=".99"/>
<circle cx="90.6" cy="169.6" r=".99"/>
<circle cx="90.6" cy="167" r=".99"/>
<circle cx="90.6" cy="164.5" r=".99"/>
<circle cx="90.6" cy="161.9" r=".99"/>
<circle cx="95.1" cy="167" r=".99"/>
<circle cx="95.1" cy="169.6" r=".99"/>
<circle cx="95.1" cy="164.5" r=".99"/>
<circle cx="95.1" cy="161.9" r=".99"/>
<circle cx="102.7" cy="167" r=".99"/>
<circle cx="102.7" cy="164.5" r=".99"/>
<circle cx="102.7" cy="161.9" r=".99"/>
<circle cx="102.7" cy="169.6" r=".99"/>
<circle cx="106.5" cy="167" r=".99"/>
<circle cx="106.5" cy="161.9" r=".99"/>
<circle cx="106.5" cy="169.6" r=".99"/>
<circle cx="106.5" cy="164.5" r=".99"/>
<circle cx="114.1" cy="169.6" r=".99"/>
<circle cx="114.1" cy="167" r=".99"/>
<circle cx="114.1" cy="164.5" r=".99"/>
<circle cx="114.1" cy="161.9" r=".99"/>
<circle cx="117.9" cy="169.6" r=".99"/>
<circle cx="117.9" cy="167" r=".99"/>
<circle cx="117.9" cy="161.9" r=".99"/>
<circle cx="117.9" cy="164.5" r=".99"/>
<circle cx="125.6" cy="164.5" r=".99"/>
<circle cx="125.6" cy="161.9" r=".99"/>
<circle cx="125.6" cy="169.6" r=".99"/>
<circle cx="125.6" cy="167" r=".99"/>
<circle cx="130" cy="161.9" r=".99"/>
<circle cx="130" cy="167" r=".99"/>
<circle cx="130" cy="169.6" r=".99"/>
<circle cx="130" cy="164.5" r=".99"/>
<circle cx="137.6" cy="169.6" r=".99"/>
<circle cx="137.6" cy="167" r=".99"/>
<circle cx="137.6" cy="164.5" r=".99"/>
<circle cx="137.6" cy="161.9" r=".99"/>
<circle cx="141.1" cy="164.5" r=".99"/>
<circle cx="141.1" cy="161.9" r=".99"/>
<circle cx="141.1" cy="167" r=".99"/>
<circle cx="148.7" cy="167" r=".99"/>
<circle cx="148.7" cy="164.5" r=".99"/>
<circle cx="148.7" cy="161.9" r=".99"/>
<circle cx="151.6" cy="170.5" r=".99"/>
<circle cx="152.5" cy="165.1" r=".99"/>
<circle cx="152.5" cy="162.6" r=".99"/>
<circle cx="152.5" cy="160" r=".99"/>
</g>
<use href="#words"/>
</svg>
